VERSION 5.7 ;
NAMESCASESENSITIVE ON ;
BUSBITCHARS "[]" ;
DIVIDERCHAR "|" ;

PROPERTYDEFINITIONS
    LAYER LEF58_TYPE STRING ;
END PROPERTYDEFINITIONS


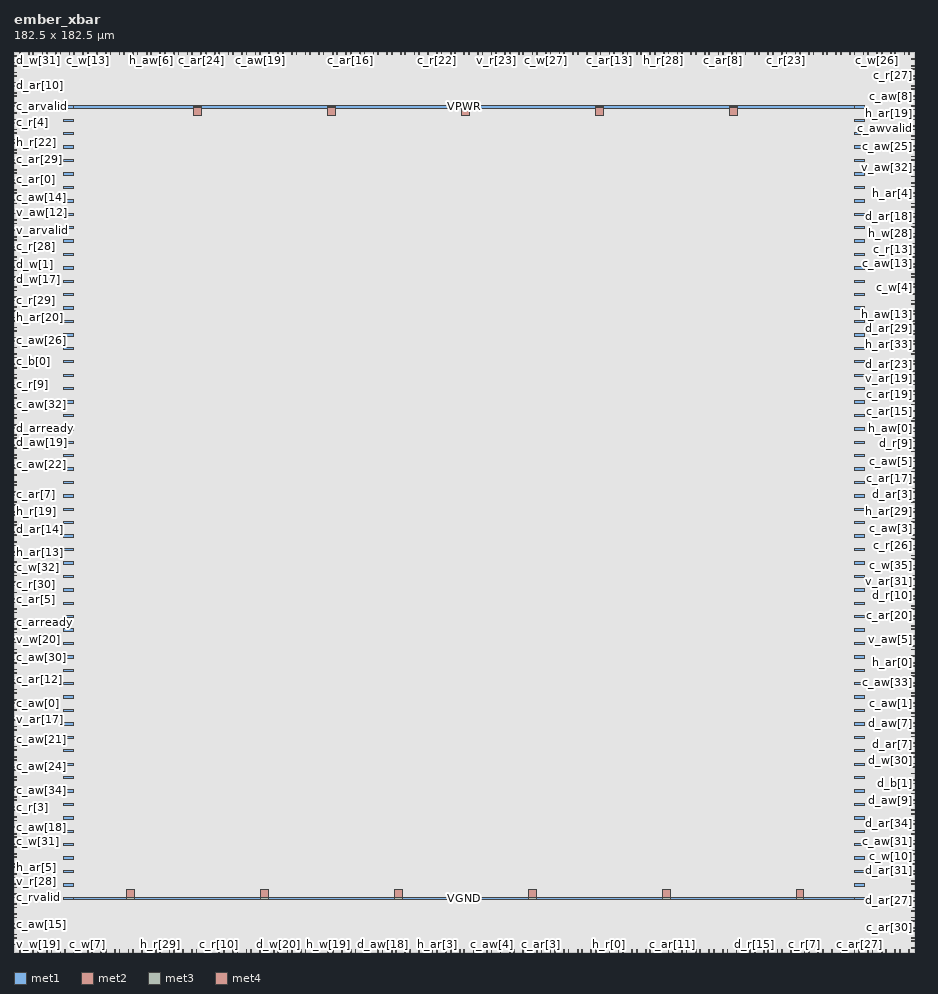
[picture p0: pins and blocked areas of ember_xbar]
MACRO ember_xbar
    CLASS BLOCK ;
    SIZE 182.5 BY 182.5 ;
    SYMMETRY Y ;
    PIN c_ar[0]
        DIRECTION OUTPUT ; 
        USE SIGNAL ; 
        PORT
            LAYER met1 ;
              RECT  0 156.5 0.595 156.64 ;
        END
    END c_ar[0]
    PIN c_ar[10]
        DIRECTION OUTPUT ; 
        USE SIGNAL ; 
        PORT
            LAYER met2 ;
              RECT  21.32 0 21.46 0.485 ;
        END
    END c_ar[10]
    PIN c_ar[11]
        DIRECTION OUTPUT ; 
        USE SIGNAL ; 
        PORT
            LAYER met2 ;
              RECT  133.56 0 133.7 0.485 ;
        END
    END c_ar[11]
    PIN c_ar[12]
        DIRECTION OUTPUT ; 
        USE SIGNAL ; 
        PORT
            LAYER met1 ;
              RECT  0 55.18 0.595 55.32 ;
        END
    END c_ar[12]
    PIN c_ar[13]
        DIRECTION OUTPUT ; 
        USE SIGNAL ; 
        PORT
            LAYER met2 ;
              RECT  120.68 182.015 120.82 182.5 ;
        END
    END c_ar[13]
    PIN c_ar[14]
        DIRECTION OUTPUT ; 
        USE SIGNAL ; 
        PORT
            LAYER met1 ;
              RECT  0 130.66 0.595 130.8 ;
        END
    END c_ar[14]
    PIN c_ar[15]
        DIRECTION OUTPUT ; 
        USE SIGNAL ; 
        PORT
            LAYER met1 ;
              RECT  181.905 109.58 182.5 109.72 ;
        END
    END c_ar[15]
    PIN c_ar[16]
        DIRECTION OUTPUT ; 
        USE SIGNAL ; 
        PORT
            LAYER met2 ;
              RECT  68.24 182.015 68.38 182.5 ;
        END
    END c_ar[16]
    PIN c_ar[17]
        DIRECTION OUTPUT ; 
        USE SIGNAL ; 
        PORT
            LAYER met1 ;
              RECT  181.905 95.98 182.5 96.12 ;
        END
    END c_ar[17]
    PIN c_ar[18]
        DIRECTION OUTPUT ; 
        USE SIGNAL ; 
        PORT
            LAYER met2 ;
              RECT  169.44 182.015 169.58 182.5 ;
        END
    END c_ar[18]
    PIN c_ar[19]
        DIRECTION OUTPUT ; 
        USE SIGNAL ; 
        PORT
            LAYER met1 ;
              RECT  181.905 112.98 182.5 113.12 ;
        END
    END c_ar[19]
    PIN c_ar[1]
        DIRECTION OUTPUT ; 
        USE SIGNAL ; 
        PORT
            LAYER met1 ;
              RECT  181.905 147.66 182.5 147.8 ;
        END
    END c_ar[1]
    PIN c_ar[20]
        DIRECTION OUTPUT ; 
        USE SIGNAL ; 
        PORT
            LAYER met1 ;
              RECT  181.905 68.1 182.5 68.24 ;
        END
    END c_ar[20]
    PIN c_ar[21]
        DIRECTION OUTPUT ; 
        USE SIGNAL ; 
        PORT
            LAYER met2 ;
              RECT  146.44 0 146.58 0.485 ;
        END
    END c_ar[21]
    PIN c_ar[22]
        DIRECTION OUTPUT ; 
        USE SIGNAL ; 
        PORT
            LAYER met2 ;
              RECT  61.8 182.015 61.94 182.5 ;
        END
    END c_ar[22]
    PIN c_ar[23]
        DIRECTION OUTPUT ; 
        USE SIGNAL ; 
        PORT
            LAYER met2 ;
              RECT  2.92 182.015 3.06 182.5 ;
        END
    END c_ar[23]
    PIN c_ar[24]
        DIRECTION OUTPUT ; 
        USE SIGNAL ; 
        PORT
            LAYER met2 ;
              RECT  37.88 182.015 38.02 182.5 ;
        END
    END c_ar[24]
    PIN c_ar[25]
        DIRECTION OUTPUT ; 
        USE SIGNAL ; 
        PORT
            LAYER met2 ;
              RECT  28.68 0 28.82 0.485 ;
        END
    END c_ar[25]
    PIN c_ar[26]
        DIRECTION OUTPUT ; 
        USE SIGNAL ; 
        PORT
            LAYER met2 ;
              RECT  2 0 2.14 0.485 ;
        END
    END c_ar[26]
    PIN c_ar[27]
        DIRECTION OUTPUT ; 
        USE SIGNAL ; 
        PORT
            LAYER met2 ;
              RECT  171.28 0 171.42 0.485 ;
        END
    END c_ar[27]
    PIN c_ar[28]
        DIRECTION OUTPUT ; 
        USE SIGNAL ; 
        PORT
            LAYER met1 ;
              RECT  181.905 89.86 182.5 90 ;
        END
    END c_ar[28]
    PIN c_ar[29]
        DIRECTION OUTPUT ; 
        USE SIGNAL ; 
        PORT
            LAYER met1 ;
              RECT  0 160.58 0.595 160.72 ;
        END
    END c_ar[29]
    PIN c_ar[2]
        DIRECTION OUTPUT ; 
        USE SIGNAL ; 
        PORT
            LAYER met2 ;
              RECT  24.08 0 24.22 0.485 ;
        END
    END c_ar[2]
    PIN c_ar[30]
        DIRECTION OUTPUT ; 
        USE SIGNAL ; 
        PORT
            LAYER met1 ;
              RECT  181.905 4.86 182.5 5 ;
        END
    END c_ar[30]
    PIN c_ar[31]
        DIRECTION OUTPUT ; 
        USE SIGNAL ; 
        PORT
            LAYER met2 ;
              RECT  6.6 182.015 6.74 182.5 ;
        END
    END c_ar[31]
    PIN c_ar[32]
        DIRECTION OUTPUT ; 
        USE SIGNAL ; 
        PORT
            LAYER met1 ;
              RECT  181.905 141.54 182.5 141.68 ;
        END
    END c_ar[32]
    PIN c_ar[33]
        DIRECTION OUTPUT ; 
        USE SIGNAL ; 
        PORT
            LAYER met2 ;
              RECT  94.92 182.015 95.06 182.5 ;
        END
    END c_ar[33]
    PIN c_ar[34]
        DIRECTION OUTPUT ; 
        USE SIGNAL ; 
        PORT
            LAYER met1 ;
              RECT  181.905 113.66 182.5 113.8 ;
        END
    END c_ar[34]
    PIN c_ar[3]
        DIRECTION OUTPUT ; 
        USE SIGNAL ; 
        PORT
            LAYER met2 ;
              RECT  106.88 0 107.02 0.485 ;
        END
    END c_ar[3]
    PIN c_ar[4]
        DIRECTION OUTPUT ; 
        USE SIGNAL ; 
        PORT
            LAYER met2 ;
              RECT  105.96 0 106.1 0.485 ;
        END
    END c_ar[4]
    PIN c_ar[5]
        DIRECTION OUTPUT ; 
        USE SIGNAL ; 
        PORT
            LAYER met1 ;
              RECT  0 71.5 0.595 71.64 ;
        END
    END c_ar[5]
    PIN c_ar[6]
        DIRECTION OUTPUT ; 
        USE SIGNAL ; 
        PORT
            LAYER met2 ;
              RECT  5.68 182.015 5.82 182.5 ;
        END
    END c_ar[6]
    PIN c_ar[7]
        DIRECTION OUTPUT ; 
        USE SIGNAL ; 
        PORT
            LAYER met1 ;
              RECT  0 91.22 0.595 91.36 ;
        END
    END c_ar[7]
    PIN c_ar[8]
        DIRECTION OUTPUT ; 
        USE SIGNAL ; 
        PORT
            LAYER met2 ;
              RECT  143.68 182.015 143.82 182.5 ;
        END
    END c_ar[8]
    PIN c_ar[9]
        DIRECTION OUTPUT ; 
        USE SIGNAL ; 
        PORT
            LAYER met2 ;
              RECT  79.28 0 79.42 0.485 ;
        END
    END c_ar[9]
    PIN c_arready
        DIRECTION INPUT ; 
        USE SIGNAL ; 
        PORT
            LAYER met1 ;
              RECT  0 66.74 0.595 66.88 ;
        END
    END c_arready
    PIN c_arvalid
        DIRECTION OUTPUT ; 
        USE SIGNAL ; 
        PORT
            LAYER met1 ;
              RECT  0 171.46 0.595 171.6 ;
        END
    END c_arvalid
    PIN c_aw[0]
        DIRECTION OUTPUT ; 
        USE SIGNAL ; 
        PORT
            LAYER met1 ;
              RECT  0 50.42 0.595 50.56 ;
        END
    END c_aw[0]
    PIN c_aw[10]
        DIRECTION OUTPUT ; 
        USE SIGNAL ; 
        PORT
            LAYER met1 ;
              RECT  181.905 67.42 182.5 67.56 ;
        END
    END c_aw[10]
    PIN c_aw[11]
        DIRECTION OUTPUT ; 
        USE SIGNAL ; 
        PORT
            LAYER met2 ;
              RECT  167.6 182.015 167.74 182.5 ;
        END
    END c_aw[11]
    PIN c_aw[12]
        DIRECTION OUTPUT ; 
        USE SIGNAL ; 
        PORT
            LAYER met2 ;
              RECT  67.32 182.015 67.46 182.5 ;
        END
    END c_aw[12]
    PIN c_aw[13]
        DIRECTION OUTPUT ; 
        USE SIGNAL ; 
        PORT
            LAYER met1 ;
              RECT  181.905 139.5 182.5 139.64 ;
        END
    END c_aw[13]
    PIN c_aw[14]
        DIRECTION OUTPUT ; 
        USE SIGNAL ; 
        PORT
            LAYER met1 ;
              RECT  0 154.46 0.595 154.6 ;
        END
    END c_aw[14]
    PIN c_aw[15]
        DIRECTION OUTPUT ; 
        USE SIGNAL ; 
        PORT
            LAYER met1 ;
              RECT  0 5.54 0.595 5.68 ;
        END
    END c_aw[15]
    PIN c_aw[16]
        DIRECTION OUTPUT ; 
        USE SIGNAL ; 
        PORT
            LAYER met2 ;
              RECT  163.92 182.015 164.06 182.5 ;
        END
    END c_aw[16]
    PIN c_aw[17]
        DIRECTION OUTPUT ; 
        USE SIGNAL ; 
        PORT
            LAYER met1 ;
              RECT  0 13.7 0.595 13.84 ;
        END
    END c_aw[17]
    PIN c_aw[18]
        DIRECTION OUTPUT ; 
        USE SIGNAL ; 
        PORT
            LAYER met1 ;
              RECT  0 25.26 0.595 25.4 ;
        END
    END c_aw[18]
    PIN c_aw[19]
        DIRECTION OUTPUT ; 
        USE SIGNAL ; 
        PORT
            LAYER met2 ;
              RECT  49.84 182.015 49.98 182.5 ;
        END
    END c_aw[19]
    PIN c_aw[1]
        DIRECTION OUTPUT ; 
        USE SIGNAL ; 
        PORT
            LAYER met1 ;
              RECT  181.905 50.42 182.5 50.56 ;
        END
    END c_aw[1]
    PIN c_aw[20]
        DIRECTION OUTPUT ; 
        USE SIGNAL ; 
        PORT
            LAYER met2 ;
              RECT  94 182.015 94.14 182.5 ;
        END
    END c_aw[20]
    PIN c_aw[21]
        DIRECTION OUTPUT ; 
        USE SIGNAL ; 
        PORT
            LAYER met1 ;
              RECT  0 42.94 0.595 43.08 ;
        END
    END c_aw[21]
    PIN c_aw[22]
        DIRECTION OUTPUT ; 
        USE SIGNAL ; 
        PORT
            LAYER met1 ;
              RECT  0 98.7 0.595 98.84 ;
        END
    END c_aw[22]
    PIN c_aw[23]
        DIRECTION OUTPUT ; 
        USE SIGNAL ; 
        PORT
            LAYER met1 ;
              RECT  181.905 6.9 182.5 7.04 ;
        END
    END c_aw[23]
    PIN c_aw[24]
        DIRECTION OUTPUT ; 
        USE SIGNAL ; 
        PORT
            LAYER met1 ;
              RECT  0 37.5 0.595 37.64 ;
        END
    END c_aw[24]
    PIN c_aw[25]
        DIRECTION OUTPUT ; 
        USE SIGNAL ; 
        PORT
            LAYER met1 ;
              RECT  181.905 163.3 182.5 163.44 ;
        END
    END c_aw[25]
    PIN c_aw[26]
        DIRECTION OUTPUT ; 
        USE SIGNAL ; 
        PORT
            LAYER met1 ;
              RECT  0 123.86 0.595 124 ;
        END
    END c_aw[26]
    PIN c_aw[27]
        DIRECTION OUTPUT ; 
        USE SIGNAL ; 
        PORT
            LAYER met1 ;
              RECT  0 179.62 0.595 179.76 ;
        END
    END c_aw[27]
    PIN c_aw[28]
        DIRECTION OUTPUT ; 
        USE SIGNAL ; 
        PORT
            LAYER met2 ;
              RECT  8.44 182.015 8.58 182.5 ;
        END
    END c_aw[28]
    PIN c_aw[29]
        DIRECTION OUTPUT ; 
        USE SIGNAL ; 
        PORT
            LAYER met2 ;
              RECT  125.28 0 125.42 0.485 ;
        END
    END c_aw[29]
    PIN c_aw[2]
        DIRECTION OUTPUT ; 
        USE SIGNAL ; 
        PORT
            LAYER met1 ;
              RECT  181.905 166.7 182.5 166.84 ;
        END
    END c_aw[2]
    PIN c_aw[30]
        DIRECTION OUTPUT ; 
        USE SIGNAL ; 
        PORT
            LAYER met1 ;
              RECT  0 61.3 0.595 61.44 ;
        END
    END c_aw[30]
    PIN c_aw[31]
        DIRECTION OUTPUT ; 
        USE SIGNAL ; 
        PORT
            LAYER met1 ;
              RECT  181.905 23.9 182.5 24.04 ;
        END
    END c_aw[31]
    PIN c_aw[32]
        DIRECTION OUTPUT ; 
        USE SIGNAL ; 
        PORT
            LAYER met1 ;
              RECT  0 110.94 0.595 111.08 ;
        END
    END c_aw[32]
    PIN c_aw[33]
        DIRECTION OUTPUT ; 
        USE SIGNAL ; 
        PORT
            LAYER met1 ;
              RECT  181.905 54.5 182.5 54.64 ;
        END
    END c_aw[33]
    PIN c_aw[34]
        DIRECTION OUTPUT ; 
        USE SIGNAL ; 
        PORT
            LAYER met1 ;
              RECT  0 32.74 0.595 32.88 ;
        END
    END c_aw[34]
    PIN c_aw[3]
        DIRECTION OUTPUT ; 
        USE SIGNAL ; 
        PORT
            LAYER met1 ;
              RECT  181.905 85.78 182.5 85.92 ;
        END
    END c_aw[3]
    PIN c_aw[4]
        DIRECTION OUTPUT ; 
        USE SIGNAL ; 
        PORT
            LAYER met2 ;
              RECT  96.76 0 96.9 0.485 ;
        END
    END c_aw[4]
    PIN c_aw[5]
        DIRECTION OUTPUT ; 
        USE SIGNAL ; 
        PORT
            LAYER met1 ;
              RECT  181.905 99.38 182.5 99.52 ;
        END
    END c_aw[5]
    PIN c_aw[6]
        DIRECTION OUTPUT ; 
        USE SIGNAL ; 
        PORT
            LAYER met2 ;
              RECT  89.4 182.015 89.54 182.5 ;
        END
    END c_aw[6]
    PIN c_aw[7]
        DIRECTION OUTPUT ; 
        USE SIGNAL ; 
        PORT
            LAYER met2 ;
              RECT  101.36 0 101.5 0.485 ;
        END
    END c_aw[7]
    PIN c_aw[8]
        DIRECTION OUTPUT ; 
        USE SIGNAL ; 
        PORT
            LAYER met1 ;
              RECT  181.905 173.5 182.5 173.64 ;
        END
    END c_aw[8]
    PIN c_aw[9]
        DIRECTION OUTPUT ; 
        USE SIGNAL ; 
        PORT
            LAYER met1 ;
              RECT  181.905 19.82 182.5 19.96 ;
        END
    END c_aw[9]
    PIN c_awready
        DIRECTION INPUT ; 
        USE SIGNAL ; 
        PORT
            LAYER met1 ;
              RECT  181.905 100.06 182.5 100.2 ;
        END
    END c_awready
    PIN c_awvalid
        DIRECTION OUTPUT ; 
        USE SIGNAL ; 
        PORT
            LAYER met1 ;
              RECT  181.905 165.34 182.5 165.48 ;
        END
    END c_awvalid
    PIN c_b[0]
        DIRECTION INPUT ; 
        USE SIGNAL ; 
        PORT
            LAYER met1 ;
              RECT  0 121.14 0.595 121.28 ;
        END
    END c_b[0]
    PIN c_b[1]
        DIRECTION INPUT ; 
        USE SIGNAL ; 
        PORT
            LAYER met1 ;
              RECT  181.905 26.62 182.5 26.76 ;
        END
    END c_b[1]
    PIN c_bready
        DIRECTION OUTPUT ; 
        USE SIGNAL ; 
        PORT
            LAYER met1 ;
              RECT  0 136.1 0.595 136.24 ;
        END
    END c_bready
    PIN c_bvalid
        DIRECTION INPUT ; 
        USE SIGNAL ; 
        PORT
            LAYER met2 ;
              RECT  78.36 182.015 78.5 182.5 ;
        END
    END c_bvalid
    PIN c_r[0]
        DIRECTION INPUT ; 
        USE SIGNAL ; 
        PORT
            LAYER met1 ;
              RECT  0 118.42 0.595 118.56 ;
        END
    END c_r[0]
    PIN c_r[10]
        DIRECTION INPUT ; 
        USE SIGNAL ; 
        PORT
            LAYER met2 ;
              RECT  41.56 0 41.7 0.485 ;
        END
    END c_r[10]
    PIN c_r[11]
        DIRECTION INPUT ; 
        USE SIGNAL ; 
        PORT
            LAYER met2 ;
              RECT  113.32 182.015 113.46 182.5 ;
        END
    END c_r[11]
    PIN c_r[12]
        DIRECTION INPUT ; 
        USE SIGNAL ; 
        PORT
            LAYER met1 ;
              RECT  0 44.98 0.595 45.12 ;
        END
    END c_r[12]
    PIN c_r[13]
        DIRECTION INPUT ; 
        USE SIGNAL ; 
        PORT
            LAYER met1 ;
              RECT  181.905 140.86 182.5 141 ;
        END
    END c_r[13]
    PIN c_r[14]
        DIRECTION INPUT ; 
        USE SIGNAL ; 
        PORT
            LAYER met2 ;
              RECT  137.24 182.015 137.38 182.5 ;
        END
    END c_r[14]
    PIN c_r[15]
        DIRECTION INPUT ; 
        USE SIGNAL ; 
        PORT
            LAYER met2 ;
              RECT  20.4 0 20.54 0.485 ;
        END
    END c_r[15]
    PIN c_r[16]
        DIRECTION INPUT ; 
        USE SIGNAL ; 
        PORT
            LAYER met2 ;
              RECT  123.44 182.015 123.58 182.5 ;
        END
    END c_r[16]
    PIN c_r[17]
        DIRECTION INPUT ; 
        USE SIGNAL ; 
        PORT
            LAYER met2 ;
              RECT  68.24 0 68.38 0.485 ;
        END
    END c_r[17]
    PIN c_r[18]
        DIRECTION INPUT ; 
        USE SIGNAL ; 
        PORT
            LAYER met1 ;
              RECT  0 39.54 0.595 39.68 ;
        END
    END c_r[18]
    PIN c_r[19]
        DIRECTION INPUT ; 
        USE SIGNAL ; 
        PORT
            LAYER met1 ;
              RECT  181.905 127.26 182.5 127.4 ;
        END
    END c_r[19]
    PIN c_r[1]
        DIRECTION INPUT ; 
        USE SIGNAL ; 
        PORT
            LAYER met1 ;
              RECT  0 69.46 0.595 69.6 ;
        END
    END c_r[1]
    PIN c_r[20]
        DIRECTION INPUT ; 
        USE SIGNAL ; 
        PORT
            LAYER met1 ;
              RECT  0 94.62 0.595 94.76 ;
        END
    END c_r[20]
    PIN c_r[21]
        DIRECTION INPUT ; 
        USE SIGNAL ; 
        PORT
            LAYER met2 ;
              RECT  163.92 0 164.06 0.485 ;
        END
    END c_r[21]
    PIN c_r[22]
        DIRECTION INPUT ; 
        USE SIGNAL ; 
        PORT
            LAYER met2 ;
              RECT  85.72 182.015 85.86 182.5 ;
        END
    END c_r[22]
    PIN c_r[23]
        DIRECTION INPUT ; 
        USE SIGNAL ; 
        PORT
            LAYER met2 ;
              RECT  156.56 182.015 156.7 182.5 ;
        END
    END c_r[23]
    PIN c_r[24]
        DIRECTION INPUT ; 
        USE SIGNAL ; 
        PORT
            LAYER met2 ;
              RECT  95.84 0 95.98 0.485 ;
        END
    END c_r[24]
    PIN c_r[25]
        DIRECTION INPUT ; 
        USE SIGNAL ; 
        PORT
            LAYER met2 ;
              RECT  81.12 182.015 81.26 182.5 ;
        END
    END c_r[25]
    PIN c_r[26]
        DIRECTION INPUT ; 
        USE SIGNAL ; 
        PORT
            LAYER met1 ;
              RECT  181.905 82.38 182.5 82.52 ;
        END
    END c_r[26]
    PIN c_r[27]
        DIRECTION INPUT ; 
        USE SIGNAL ; 
        PORT
            LAYER met1 ;
              RECT  181.905 177.58 182.5 177.72 ;
        END
    END c_r[27]
    PIN c_r[28]
        DIRECTION INPUT ; 
        USE SIGNAL ; 
        PORT
            LAYER met1 ;
              RECT  0 142.9 0.595 143.04 ;
        END
    END c_r[28]
    PIN c_r[29]
        DIRECTION INPUT ; 
        USE SIGNAL ; 
        PORT
            LAYER met1 ;
              RECT  0 132.02 0.595 132.16 ;
        END
    END c_r[29]
    PIN c_r[2]
        DIRECTION INPUT ; 
        USE SIGNAL ; 
        PORT
            LAYER met1 ;
              RECT  0 51.1 0.595 51.24 ;
        END
    END c_r[2]
    PIN c_r[30]
        DIRECTION INPUT ; 
        USE SIGNAL ; 
        PORT
            LAYER met1 ;
              RECT  0 72.86 0.595 73 ;
        END
    END c_r[30]
    PIN c_r[31]
        DIRECTION INPUT ; 
        USE SIGNAL ; 
        PORT
            LAYER met2 ;
              RECT  56.28 182.015 56.42 182.5 ;
        END
    END c_r[31]
    PIN c_r[32]
        DIRECTION INPUT ; 
        USE SIGNAL ; 
        PORT
            LAYER met2 ;
              RECT  13.04 0 13.18 0.485 ;
        END
    END c_r[32]
    PIN c_r[33]
        DIRECTION INPUT ; 
        USE SIGNAL ; 
        PORT
            LAYER met1 ;
              RECT  181.905 125.9 182.5 126.04 ;
        END
    END c_r[33]
    PIN c_r[3]
        DIRECTION INPUT ; 
        USE SIGNAL ; 
        PORT
            LAYER met1 ;
              RECT  0 30.7 0.595 30.84 ;
        END
    END c_r[3]
    PIN c_r[4]
        DIRECTION INPUT ; 
        USE SIGNAL ; 
        PORT
            LAYER met1 ;
              RECT  0 168.06 0.595 168.2 ;
        END
    END c_r[4]
    PIN c_r[5]
        DIRECTION INPUT ; 
        USE SIGNAL ; 
        PORT
            LAYER met1 ;
              RECT  181.905 13.7 182.5 13.84 ;
        END
    END c_r[5]
    PIN c_r[6]
        DIRECTION INPUT ; 
        USE SIGNAL ; 
        PORT
            LAYER met1 ;
              RECT  181.905 123.86 182.5 124 ;
        END
    END c_r[6]
    PIN c_r[7]
        DIRECTION INPUT ; 
        USE SIGNAL ; 
        PORT
            LAYER met2 ;
              RECT  160.24 0 160.38 0.485 ;
        END
    END c_r[7]
    PIN c_r[8]
        DIRECTION INPUT ; 
        USE SIGNAL ; 
        PORT
            LAYER met1 ;
              RECT  181.905 97.34 182.5 97.48 ;
        END
    END c_r[8]
    PIN c_r[9]
        DIRECTION INPUT ; 
        USE SIGNAL ; 
        PORT
            LAYER met1 ;
              RECT  0 115.02 0.595 115.16 ;
        END
    END c_r[9]
    PIN c_rready
        DIRECTION OUTPUT ; 
        USE SIGNAL ; 
        PORT
            LAYER met1 ;
              RECT  0 88.5 0.595 88.64 ;
        END
    END c_rready
    PIN c_rvalid
        DIRECTION INPUT ; 
        USE SIGNAL ; 
        PORT
            LAYER met1 ;
              RECT  0 10.98 0.595 11.12 ;
        END
    END c_rvalid
    PIN c_w[0]
        DIRECTION OUTPUT ; 
        USE SIGNAL ; 
        PORT
            LAYER met2 ;
              RECT  108.72 0 108.86 0.485 ;
        END
    END c_w[0]
    PIN c_w[10]
        DIRECTION OUTPUT ; 
        USE SIGNAL ; 
        PORT
            LAYER met1 ;
              RECT  181.905 17.78 182.5 17.92 ;
        END
    END c_w[10]
    PIN c_w[11]
        DIRECTION OUTPUT ; 
        USE SIGNAL ; 
        PORT
            LAYER met1 ;
              RECT  181.905 51.78 182.5 51.92 ;
        END
    END c_w[11]
    PIN c_w[12]
        DIRECTION OUTPUT ; 
        USE SIGNAL ; 
        PORT
            LAYER met1 ;
              RECT  0 6.9 0.595 7.04 ;
        END
    END c_w[12]
    PIN c_w[13]
        DIRECTION OUTPUT ; 
        USE SIGNAL ; 
        PORT
            LAYER met2 ;
              RECT  14.88 182.015 15.02 182.5 ;
        END
    END c_w[13]
    PIN c_w[14]
        DIRECTION OUTPUT ; 
        USE SIGNAL ; 
        PORT
            LAYER met1 ;
              RECT  0 178.26 0.595 178.4 ;
        END
    END c_w[14]
    PIN c_w[15]
        DIRECTION OUTPUT ; 
        USE SIGNAL ; 
        PORT
            LAYER met1 ;
              RECT  181.905 24.58 182.5 24.72 ;
        END
    END c_w[15]
    PIN c_w[16]
        DIRECTION OUTPUT ; 
        USE SIGNAL ; 
        PORT
            LAYER met2 ;
              RECT  82.04 182.015 82.18 182.5 ;
        END
    END c_w[16]
    PIN c_w[17]
        DIRECTION OUTPUT ; 
        USE SIGNAL ; 
        PORT
            LAYER met2 ;
              RECT  76.52 182.015 76.66 182.5 ;
        END
    END c_w[17]
    PIN c_w[18]
        DIRECTION OUTPUT ; 
        USE SIGNAL ; 
        PORT
            LAYER met2 ;
              RECT  163 0 163.14 0.485 ;
        END
    END c_w[18]
    PIN c_w[19]
        DIRECTION OUTPUT ; 
        USE SIGNAL ; 
        PORT
            LAYER met2 ;
              RECT  88.48 182.015 88.62 182.5 ;
        END
    END c_w[19]
    PIN c_w[1]
        DIRECTION OUTPUT ; 
        USE SIGNAL ; 
        PORT
            LAYER met1 ;
              RECT  181.905 174.86 182.5 175 ;
        END
    END c_w[1]
    PIN c_w[20]
        DIRECTION OUTPUT ; 
        USE SIGNAL ; 
        PORT
            LAYER met1 ;
              RECT  0 170.1 0.595 170.24 ;
        END
    END c_w[20]
    PIN c_w[21]
        DIRECTION OUTPUT ; 
        USE SIGNAL ; 
        PORT
            LAYER met2 ;
              RECT  142.76 182.015 142.9 182.5 ;
        END
    END c_w[21]
    PIN c_w[22]
        DIRECTION OUTPUT ; 
        USE SIGNAL ; 
        PORT
            LAYER met2 ;
              RECT  98.6 0 98.74 0.485 ;
        END
    END c_w[22]
    PIN c_w[23]
        DIRECTION OUTPUT ; 
        USE SIGNAL ; 
        PORT
            LAYER met1 ;
              RECT  181.905 179.62 182.5 179.76 ;
        END
    END c_w[23]
    PIN c_w[24]
        DIRECTION OUTPUT ; 
        USE SIGNAL ; 
        PORT
            LAYER met2 ;
              RECT  145.52 182.015 145.66 182.5 ;
        END
    END c_w[24]
    PIN c_w[25]
        DIRECTION OUTPUT ; 
        USE SIGNAL ; 
        PORT
            LAYER met2 ;
              RECT  51.68 182.015 51.82 182.5 ;
        END
    END c_w[25]
    PIN c_w[26]
        DIRECTION OUTPUT ; 
        USE SIGNAL ; 
        PORT
            LAYER met2 ;
              RECT  174.96 182.015 175.1 182.5 ;
        END
    END c_w[26]
    PIN c_w[27]
        DIRECTION OUTPUT ; 
        USE SIGNAL ; 
        PORT
            LAYER met2 ;
              RECT  107.8 182.015 107.94 182.5 ;
        END
    END c_w[27]
    PIN c_w[28]
        DIRECTION OUTPUT ; 
        USE SIGNAL ; 
        PORT
            LAYER met2 ;
              RECT  87.56 0 87.7 0.485 ;
        END
    END c_w[28]
    PIN c_w[29]
        DIRECTION OUTPUT ; 
        USE SIGNAL ; 
        PORT
            LAYER met2 ;
              RECT  158.4 0 158.54 0.485 ;
        END
    END c_w[29]
    PIN c_w[2]
        DIRECTION OUTPUT ; 
        USE SIGNAL ; 
        PORT
            LAYER met2 ;
              RECT  42.48 0 42.62 0.485 ;
        END
    END c_w[2]
    PIN c_w[30]
        DIRECTION OUTPUT ; 
        USE SIGNAL ; 
        PORT
            LAYER met2 ;
              RECT  126.2 0 126.34 0.485 ;
        END
    END c_w[30]
    PIN c_w[31]
        DIRECTION OUTPUT ; 
        USE SIGNAL ; 
        PORT
            LAYER met1 ;
              RECT  0 23.9 0.595 24.04 ;
        END
    END c_w[31]
    PIN c_w[32]
        DIRECTION OUTPUT ; 
        USE SIGNAL ; 
        PORT
            LAYER met1 ;
              RECT  0 76.26 0.595 76.4 ;
        END
    END c_w[32]
    PIN c_w[33]
        DIRECTION OUTPUT ; 
        USE SIGNAL ; 
        PORT
            LAYER met2 ;
              RECT  18.56 182.015 18.7 182.5 ;
        END
    END c_w[33]
    PIN c_w[34]
        DIRECTION OUTPUT ; 
        USE SIGNAL ; 
        PORT
            LAYER met1 ;
              RECT  0 114.34 0.595 114.48 ;
        END
    END c_w[34]
    PIN c_w[35]
        DIRECTION OUTPUT ; 
        USE SIGNAL ; 
        PORT
            LAYER met1 ;
              RECT  181.905 78.3 182.5 78.44 ;
        END
    END c_w[35]
    PIN c_w[3]
        DIRECTION OUTPUT ; 
        USE SIGNAL ; 
        PORT
            LAYER met2 ;
              RECT  178.64 0 178.78 0.485 ;
        END
    END c_w[3]
    PIN c_w[4]
        DIRECTION OUTPUT ; 
        USE SIGNAL ; 
        PORT
            LAYER met1 ;
              RECT  181.905 134.74 182.5 134.88 ;
        END
    END c_w[4]
    PIN c_w[5]
        DIRECTION OUTPUT ; 
        USE SIGNAL ; 
        PORT
            LAYER met1 ;
              RECT  0 21.86 0.595 22 ;
        END
    END c_w[5]
    PIN c_w[6]
        DIRECTION OUTPUT ; 
        USE SIGNAL ; 
        PORT
            LAYER met1 ;
              RECT  0 117.06 0.595 117.2 ;
        END
    END c_w[6]
    PIN c_w[7]
        DIRECTION OUTPUT ; 
        USE SIGNAL ; 
        PORT
            LAYER met2 ;
              RECT  14.88 0 15.02 0.485 ;
        END
    END c_w[7]
    PIN c_w[8]
        DIRECTION OUTPUT ; 
        USE SIGNAL ; 
        PORT
            LAYER met1 ;
              RECT  181.905 49.74 182.5 49.88 ;
        END
    END c_w[8]
    PIN c_w[9]
        DIRECTION OUTPUT ; 
        USE SIGNAL ; 
        PORT
            LAYER met1 ;
              RECT  181.905 91.9 182.5 92.04 ;
        END
    END c_w[9]
    PIN c_wready
        DIRECTION INPUT ; 
        USE SIGNAL ; 
        PORT
            LAYER met2 ;
              RECT  178.64 182.015 178.78 182.5 ;
        END
    END c_wready
    PIN c_wvalid
        DIRECTION OUTPUT ; 
        USE SIGNAL ; 
        PORT
            LAYER met1 ;
              RECT  181.905 20.5 182.5 20.64 ;
        END
    END c_wvalid
    PIN clk
        DIRECTION INPUT ; 
        USE SIGNAL ; 
        PORT
            LAYER met2 ;
              RECT  177.72 182.015 177.86 182.5 ;
        END
    END clk
    PIN d_ar[0]
        DIRECTION INPUT ; 
        USE SIGNAL ; 
        PORT
            LAYER met2 ;
              RECT  170.36 182.015 170.5 182.5 ;
        END
    END d_ar[0]
    PIN d_ar[10]
        DIRECTION INPUT ; 
        USE SIGNAL ; 
        PORT
            LAYER met1 ;
              RECT  0 174.18 0.595 174.32 ;
        END
    END d_ar[10]
    PIN d_ar[11]
        DIRECTION INPUT ; 
        USE SIGNAL ; 
        PORT
            LAYER met2 ;
              RECT  11.2 182.015 11.34 182.5 ;
        END
    END d_ar[11]
    PIN d_ar[12]
        DIRECTION INPUT ; 
        USE SIGNAL ; 
        PORT
            LAYER met1 ;
              RECT  0 158.54 0.595 158.68 ;
        END
    END d_ar[12]
    PIN d_ar[13]
        DIRECTION INPUT ; 
        USE SIGNAL ; 
        PORT
            LAYER met2 ;
              RECT  72.84 182.015 72.98 182.5 ;
        END
    END d_ar[13]
    PIN d_ar[14]
        DIRECTION INPUT ; 
        USE SIGNAL ; 
        PORT
            LAYER met1 ;
              RECT  0 87.14 0.595 87.28 ;
        END
    END d_ar[14]
    PIN d_ar[15]
        DIRECTION INPUT ; 
        USE SIGNAL ; 
        PORT
            LAYER met2 ;
              RECT  88.48 0 88.62 0.485 ;
        END
    END d_ar[15]
    PIN d_ar[16]
        DIRECTION INPUT ; 
        USE SIGNAL ; 
        PORT
            LAYER met1 ;
              RECT  181.905 75.58 182.5 75.72 ;
        END
    END d_ar[16]
    PIN d_ar[17]
        DIRECTION INPUT ; 
        USE SIGNAL ; 
        PORT
            LAYER met2 ;
              RECT  50.76 0 50.9 0.485 ;
        END
    END d_ar[17]
    PIN d_ar[18]
        DIRECTION INPUT ; 
        USE SIGNAL ; 
        PORT
            LAYER met1 ;
              RECT  181.905 149.02 182.5 149.16 ;
        END
    END d_ar[18]
    PIN d_ar[19]
        DIRECTION INPUT ; 
        USE SIGNAL ; 
        PORT
            LAYER met1 ;
              RECT  0 124.54 0.595 124.68 ;
        END
    END d_ar[19]
    PIN d_ar[1]
        DIRECTION INPUT ; 
        USE SIGNAL ; 
        PORT
            LAYER met2 ;
              RECT  140.92 0 141.06 0.485 ;
        END
    END d_ar[1]
    PIN d_ar[20]
        DIRECTION INPUT ; 
        USE SIGNAL ; 
        PORT
            LAYER met1 ;
              RECT  0 15.06 0.595 15.2 ;
        END
    END d_ar[20]
    PIN d_ar[21]
        DIRECTION INPUT ; 
        USE SIGNAL ; 
        PORT
            LAYER met1 ;
              RECT  0 49.06 0.595 49.2 ;
        END
    END d_ar[21]
    PIN d_ar[22]
        DIRECTION INPUT ; 
        USE SIGNAL ; 
        PORT
            LAYER met1 ;
              RECT  181.905 4.18 182.5 4.32 ;
        END
    END d_ar[22]
    PIN d_ar[23]
        DIRECTION INPUT ; 
        USE SIGNAL ; 
        PORT
            LAYER met1 ;
              RECT  181.905 119.1 182.5 119.24 ;
        END
    END d_ar[23]
    PIN d_ar[24]
        DIRECTION INPUT ; 
        USE SIGNAL ; 
        PORT
            LAYER met1 ;
              RECT  0 125.9 0.595 126.04 ;
        END
    END d_ar[24]
    PIN d_ar[25]
        DIRECTION INPUT ; 
        USE SIGNAL ; 
        PORT
            LAYER met2 ;
              RECT  12.12 182.015 12.26 182.5 ;
        END
    END d_ar[25]
    PIN d_ar[26]
        DIRECTION INPUT ; 
        USE SIGNAL ; 
        PORT
            LAYER met2 ;
              RECT  111.48 182.015 111.62 182.5 ;
        END
    END d_ar[26]
    PIN d_ar[27]
        DIRECTION INPUT ; 
        USE SIGNAL ; 
        PORT
            LAYER met1 ;
              RECT  181.905 10.3 182.5 10.44 ;
        END
    END d_ar[27]
    PIN d_ar[28]
        DIRECTION INPUT ; 
        USE SIGNAL ; 
        PORT
            LAYER met1 ;
              RECT  0 181.66 0.595 181.8 ;
        END
    END d_ar[28]
    PIN d_ar[29]
        DIRECTION INPUT ; 
        USE SIGNAL ; 
        PORT
            LAYER met1 ;
              RECT  181.905 127.94 182.5 128.08 ;
        END
    END d_ar[29]
    PIN d_ar[2]
        DIRECTION INPUT ; 
        USE SIGNAL ; 
        PORT
            LAYER met1 ;
              RECT  181.905 162.62 182.5 162.76 ;
        END
    END d_ar[2]
    PIN d_ar[30]
        DIRECTION INPUT ; 
        USE SIGNAL ; 
        PORT
            LAYER met1 ;
              RECT  181.905 15.74 182.5 15.88 ;
        END
    END d_ar[30]
    PIN d_ar[31]
        DIRECTION INPUT ; 
        USE SIGNAL ; 
        PORT
            LAYER met1 ;
              RECT  181.905 16.42 182.5 16.56 ;
        END
    END d_ar[31]
    PIN d_ar[32]
        DIRECTION INPUT ; 
        USE SIGNAL ; 
        PORT
            LAYER met1 ;
              RECT  181.905 119.78 182.5 119.92 ;
        END
    END d_ar[32]
    PIN d_ar[33]
        DIRECTION INPUT ; 
        USE SIGNAL ; 
        PORT
            LAYER met2 ;
              RECT  57.2 182.015 57.34 182.5 ;
        END
    END d_ar[33]
    PIN d_ar[34]
        DIRECTION INPUT ; 
        USE SIGNAL ; 
        PORT
            LAYER met1 ;
              RECT  181.905 25.94 182.5 26.08 ;
        END
    END d_ar[34]
    PIN d_ar[3]
        DIRECTION INPUT ; 
        USE SIGNAL ; 
        PORT
            LAYER met1 ;
              RECT  181.905 91.22 182.5 91.36 ;
        END
    END d_ar[3]
    PIN d_ar[4]
        DIRECTION INPUT ; 
        USE SIGNAL ; 
        PORT
            LAYER met2 ;
              RECT  172.2 182.015 172.34 182.5 ;
        END
    END d_ar[4]
    PIN d_ar[5]
        DIRECTION INPUT ; 
        USE SIGNAL ; 
        PORT
            LAYER met1 ;
              RECT  181.905 65.38 182.5 65.52 ;
        END
    END d_ar[5]
    PIN d_ar[6]
        DIRECTION INPUT ; 
        USE SIGNAL ; 
        PORT
            LAYER met1 ;
              RECT  0 138.14 0.595 138.28 ;
        END
    END d_ar[6]
    PIN d_ar[7]
        DIRECTION INPUT ; 
        USE SIGNAL ; 
        PORT
            LAYER met1 ;
              RECT  181.905 43.62 182.5 43.76 ;
        END
    END d_ar[7]
    PIN d_ar[8]
        DIRECTION INPUT ; 
        USE SIGNAL ; 
        PORT
            LAYER met1 ;
              RECT  0 45.66 0.595 45.8 ;
        END
    END d_ar[8]
    PIN d_ar[9]
        DIRECTION INPUT ; 
        USE SIGNAL ; 
        PORT
            LAYER met2 ;
              RECT  100.44 0 100.58 0.485 ;
        END
    END d_ar[9]
    PIN d_arready
        DIRECTION OUTPUT ; 
        USE SIGNAL ; 
        PORT
            LAYER met1 ;
              RECT  0 106.18 0.595 106.32 ;
        END
    END d_arready
    PIN d_arvalid
        DIRECTION INPUT ; 
        USE SIGNAL ; 
        PORT
            LAYER met2 ;
              RECT  60.88 0 61.02 0.485 ;
        END
    END d_arvalid
    PIN d_aw[0]
        DIRECTION INPUT ; 
        USE SIGNAL ; 
        PORT
            LAYER met1 ;
              RECT  181.905 103.46 182.5 103.6 ;
        END
    END d_aw[0]
    PIN d_aw[10]
        DIRECTION INPUT ; 
        USE SIGNAL ; 
        PORT
            LAYER met2 ;
              RECT  36.04 182.015 36.18 182.5 ;
        END
    END d_aw[10]
    PIN d_aw[11]
        DIRECTION INPUT ; 
        USE SIGNAL ; 
        PORT
            LAYER met1 ;
              RECT  181.905 48.38 182.5 48.52 ;
        END
    END d_aw[11]
    PIN d_aw[12]
        DIRECTION INPUT ; 
        USE SIGNAL ; 
        PORT
            LAYER met2 ;
              RECT  122.52 0 122.66 0.485 ;
        END
    END d_aw[12]
    PIN d_aw[13]
        DIRECTION INPUT ; 
        USE SIGNAL ; 
        PORT
            LAYER met1 ;
              RECT  181.905 138.82 182.5 138.96 ;
        END
    END d_aw[13]
    PIN d_aw[14]
        DIRECTION INPUT ; 
        USE SIGNAL ; 
        PORT
            LAYER met1 ;
              RECT  181.905 129.98 182.5 130.12 ;
        END
    END d_aw[14]
    PIN d_aw[15]
        DIRECTION INPUT ; 
        USE SIGNAL ; 
        PORT
            LAYER met2 ;
              RECT  26.84 0 26.98 0.485 ;
        END
    END d_aw[15]
    PIN d_aw[16]
        DIRECTION INPUT ; 
        USE SIGNAL ; 
        PORT
            LAYER met1 ;
              RECT  0 95.3 0.595 95.44 ;
        END
    END d_aw[16]
    PIN d_aw[17]
        DIRECTION INPUT ; 
        USE SIGNAL ; 
        PORT
            LAYER met1 ;
              RECT  0 151.74 0.595 151.88 ;
        END
    END d_aw[17]
    PIN d_aw[18]
        DIRECTION INPUT ; 
        USE SIGNAL ; 
        PORT
            LAYER met2 ;
              RECT  74.68 0 74.82 0.485 ;
        END
    END d_aw[18]
    PIN d_aw[19]
        DIRECTION INPUT ; 
        USE SIGNAL ; 
        PORT
            LAYER met1 ;
              RECT  0 104.82 0.595 104.96 ;
        END
    END d_aw[19]
    PIN d_aw[1]
        DIRECTION INPUT ; 
        USE SIGNAL ; 
        PORT
            LAYER met2 ;
              RECT  93.08 0 93.22 0.485 ;
        END
    END d_aw[1]
    PIN d_aw[20]
        DIRECTION INPUT ; 
        USE SIGNAL ; 
        PORT
            LAYER met1 ;
              RECT  0 59.26 0.595 59.4 ;
        END
    END d_aw[20]
    PIN d_aw[21]
        DIRECTION INPUT ; 
        USE SIGNAL ; 
        PORT
            LAYER met2 ;
              RECT  41.56 182.015 41.7 182.5 ;
        END
    END d_aw[21]
    PIN d_aw[22]
        DIRECTION INPUT ; 
        USE SIGNAL ; 
        PORT
            LAYER met2 ;
              RECT  165.76 0 165.9 0.485 ;
        END
    END d_aw[22]
    PIN d_aw[23]
        DIRECTION INPUT ; 
        USE SIGNAL ; 
        PORT
            LAYER met2 ;
              RECT  124.36 182.015 124.5 182.5 ;
        END
    END d_aw[23]
    PIN d_aw[24]
        DIRECTION INPUT ; 
        USE SIGNAL ; 
        PORT
            LAYER met2 ;
              RECT  52.6 0 52.74 0.485 ;
        END
    END d_aw[24]
    PIN d_aw[25]
        DIRECTION INPUT ; 
        USE SIGNAL ; 
        PORT
            LAYER met1 ;
              RECT  0 19.82 0.595 19.96 ;
        END
    END d_aw[25]
    PIN d_aw[26]
        DIRECTION INPUT ; 
        USE SIGNAL ; 
        PORT
            LAYER met2 ;
              RECT  69.16 0 69.3 0.485 ;
        END
    END d_aw[26]
    PIN d_aw[27]
        DIRECTION INPUT ; 
        USE SIGNAL ; 
        PORT
            LAYER met1 ;
              RECT  0 152.42 0.595 152.56 ;
        END
    END d_aw[27]
    PIN d_aw[28]
        DIRECTION INPUT ; 
        USE SIGNAL ; 
        PORT
            LAYER met1 ;
              RECT  0 38.86 0.595 39 ;
        END
    END d_aw[28]
    PIN d_aw[29]
        DIRECTION INPUT ; 
        USE SIGNAL ; 
        PORT
            LAYER met1 ;
              RECT  0 112.98 0.595 113.12 ;
        END
    END d_aw[29]
    PIN d_aw[2]
        DIRECTION INPUT ; 
        USE SIGNAL ; 
        PORT
            LAYER met1 ;
              RECT  181.905 70.14 182.5 70.28 ;
        END
    END d_aw[2]
    PIN d_aw[30]
        DIRECTION INPUT ; 
        USE SIGNAL ; 
        PORT
            LAYER met1 ;
              RECT  0 74.22 0.595 74.36 ;
        END
    END d_aw[30]
    PIN d_aw[31]
        DIRECTION INPUT ; 
        USE SIGNAL ; 
        PORT
            LAYER met2 ;
              RECT  44.32 182.015 44.46 182.5 ;
        END
    END d_aw[31]
    PIN d_aw[32]
        DIRECTION INPUT ; 
        USE SIGNAL ; 
        PORT
            LAYER met1 ;
              RECT  0 159.9 0.595 160.04 ;
        END
    END d_aw[32]
    PIN d_aw[33]
        DIRECTION INPUT ; 
        USE SIGNAL ; 
        PORT
            LAYER met1 ;
              RECT  0 76.94 0.595 77.08 ;
        END
    END d_aw[33]
    PIN d_aw[34]
        DIRECTION INPUT ; 
        USE SIGNAL ; 
        PORT
            LAYER met1 ;
              RECT  181.905 22.54 182.5 22.68 ;
        END
    END d_aw[34]
    PIN d_aw[3]
        DIRECTION INPUT ; 
        USE SIGNAL ; 
        PORT
            LAYER met1 ;
              RECT  0 28.66 0.595 28.8 ;
        END
    END d_aw[3]
    PIN d_aw[4]
        DIRECTION INPUT ; 
        USE SIGNAL ; 
        PORT
            LAYER met1 ;
              RECT  0 176.22 0.595 176.36 ;
        END
    END d_aw[4]
    PIN d_aw[5]
        DIRECTION INPUT ; 
        USE SIGNAL ; 
        PORT
            LAYER met1 ;
              RECT  181.905 21.86 182.5 22 ;
        END
    END d_aw[5]
    PIN d_aw[6]
        DIRECTION INPUT ; 
        USE SIGNAL ; 
        PORT
            LAYER met2 ;
              RECT  157.48 0 157.62 0.485 ;
        END
    END d_aw[6]
    PIN d_aw[7]
        DIRECTION INPUT ; 
        USE SIGNAL ; 
        PORT
            LAYER met1 ;
              RECT  181.905 46.34 182.5 46.48 ;
        END
    END d_aw[7]
    PIN d_aw[8]
        DIRECTION INPUT ; 
        USE SIGNAL ; 
        PORT
            LAYER met1 ;
              RECT  0 52.46 0.595 52.6 ;
        END
    END d_aw[8]
    PIN d_aw[9]
        DIRECTION INPUT ; 
        USE SIGNAL ; 
        PORT
            LAYER met1 ;
              RECT  181.905 30.7 182.5 30.84 ;
        END
    END d_aw[9]
    PIN d_awready
        DIRECTION OUTPUT ; 
        USE SIGNAL ; 
        PORT
            LAYER met1 ;
              RECT  181.905 117.06 182.5 117.2 ;
        END
    END d_awready
    PIN d_awvalid
        DIRECTION INPUT ; 
        USE SIGNAL ; 
        PORT
            LAYER met2 ;
              RECT  110.56 182.015 110.7 182.5 ;
        END
    END d_awvalid
    PIN d_b[0]
        DIRECTION OUTPUT ; 
        USE SIGNAL ; 
        PORT
            LAYER met1 ;
              RECT  181.905 159.22 182.5 159.36 ;
        END
    END d_b[0]
    PIN d_b[1]
        DIRECTION OUTPUT ; 
        USE SIGNAL ; 
        PORT
            LAYER met1 ;
              RECT  181.905 34.1 182.5 34.24 ;
        END
    END d_b[1]
    PIN d_bready
        DIRECTION INPUT ; 
        USE SIGNAL ; 
        PORT
            LAYER met1 ;
              RECT  0 144.94 0.595 145.08 ;
        END
    END d_bready
    PIN d_bvalid
        DIRECTION OUTPUT ; 
        USE SIGNAL ; 
        PORT
            LAYER met2 ;
              RECT  138.16 182.015 138.3 182.5 ;
        END
    END d_bvalid
    PIN d_r[0]
        DIRECTION OUTPUT ; 
        USE SIGNAL ; 
        PORT
            LAYER met1 ;
              RECT  0 149.7 0.595 149.84 ;
        END
    END d_r[0]
    PIN d_r[10]
        DIRECTION OUTPUT ; 
        USE SIGNAL ; 
        PORT
            LAYER met1 ;
              RECT  181.905 72.18 182.5 72.32 ;
        END
    END d_r[10]
    PIN d_r[11]
        DIRECTION OUTPUT ; 
        USE SIGNAL ; 
        PORT
            LAYER met1 ;
              RECT  0 1.46 0.595 1.6 ;
        END
    END d_r[11]
    PIN d_r[12]
        DIRECTION OUTPUT ; 
        USE SIGNAL ; 
        PORT
            LAYER met2 ;
              RECT  9.36 182.015 9.5 182.5 ;
        END
    END d_r[12]
    PIN d_r[13]
        DIRECTION OUTPUT ; 
        USE SIGNAL ; 
        PORT
            LAYER met2 ;
              RECT  23.16 0 23.3 0.485 ;
        END
    END d_r[13]
    PIN d_r[14]
        DIRECTION OUTPUT ; 
        USE SIGNAL ; 
        PORT
            LAYER met1 ;
              RECT  181.905 167.38 182.5 167.52 ;
        END
    END d_r[14]
    PIN d_r[15]
        DIRECTION OUTPUT ; 
        USE SIGNAL ; 
        PORT
            LAYER met2 ;
              RECT  150.12 0 150.26 0.485 ;
        END
    END d_r[15]
    PIN d_r[16]
        DIRECTION OUTPUT ; 
        USE SIGNAL ; 
        PORT
            LAYER met1 ;
              RECT  181.905 93.26 182.5 93.4 ;
        END
    END d_r[16]
    PIN d_r[17]
        DIRECTION OUTPUT ; 
        USE SIGNAL ; 
        PORT
            LAYER met2 ;
              RECT  59.96 182.015 60.1 182.5 ;
        END
    END d_r[17]
    PIN d_r[18]
        DIRECTION OUTPUT ; 
        USE SIGNAL ; 
        PORT
            LAYER met2 ;
              RECT  132.64 0 132.78 0.485 ;
        END
    END d_r[18]
    PIN d_r[19]
        DIRECTION OUTPUT ; 
        USE SIGNAL ; 
        PORT
            LAYER met1 ;
              RECT  181.905 77.62 182.5 77.76 ;
        END
    END d_r[19]
    PIN d_r[1]
        DIRECTION OUTPUT ; 
        USE SIGNAL ; 
        PORT
            LAYER met2 ;
              RECT  128.04 0 128.18 0.485 ;
        END
    END d_r[1]
    PIN d_r[20]
        DIRECTION OUTPUT ; 
        USE SIGNAL ; 
        PORT
            LAYER met1 ;
              RECT  0 53.14 0.595 53.28 ;
        END
    END d_r[20]
    PIN d_r[21]
        DIRECTION OUTPUT ; 
        USE SIGNAL ; 
        PORT
            LAYER met2 ;
              RECT  158.4 182.015 158.54 182.5 ;
        END
    END d_r[21]
    PIN d_r[22]
        DIRECTION OUTPUT ; 
        USE SIGNAL ; 
        PORT
            LAYER met2 ;
              RECT  102.28 182.015 102.42 182.5 ;
        END
    END d_r[22]
    PIN d_r[23]
        DIRECTION OUTPUT ; 
        USE SIGNAL ; 
        PORT
            LAYER met2 ;
              RECT  179.56 0 179.7 0.485 ;
        END
    END d_r[23]
    PIN d_r[24]
        DIRECTION OUTPUT ; 
        USE SIGNAL ; 
        PORT
            LAYER met2 ;
              RECT  173.12 0 173.26 0.485 ;
        END
    END d_r[24]
    PIN d_r[25]
        DIRECTION OUTPUT ; 
        USE SIGNAL ; 
        PORT
            LAYER met2 ;
              RECT  12.12 0 12.26 0.485 ;
        END
    END d_r[25]
    PIN d_r[26]
        DIRECTION OUTPUT ; 
        USE SIGNAL ; 
        PORT
            LAYER met1 ;
              RECT  181.905 80.34 182.5 80.48 ;
        END
    END d_r[26]
    PIN d_r[27]
        DIRECTION OUTPUT ; 
        USE SIGNAL ; 
        PORT
            LAYER met1 ;
              RECT  181.905 180.98 182.5 181.12 ;
        END
    END d_r[27]
    PIN d_r[28]
        DIRECTION OUTPUT ; 
        USE SIGNAL ; 
        PORT
            LAYER met1 ;
              RECT  0 102.78 0.595 102.92 ;
        END
    END d_r[28]
    PIN d_r[29]
        DIRECTION OUTPUT ; 
        USE SIGNAL ; 
        PORT
            LAYER met2 ;
              RECT  10.28 0 10.42 0.485 ;
        END
    END d_r[29]
    PIN d_r[2]
        DIRECTION OUTPUT ; 
        USE SIGNAL ; 
        PORT
            LAYER met1 ;
              RECT  181.905 121.14 182.5 121.28 ;
        END
    END d_r[2]
    PIN d_r[30]
        DIRECTION OUTPUT ; 
        USE SIGNAL ; 
        PORT
            LAYER met2 ;
              RECT  86.64 182.015 86.78 182.5 ;
        END
    END d_r[30]
    PIN d_r[31]
        DIRECTION OUTPUT ; 
        USE SIGNAL ; 
        PORT
            LAYER met1 ;
              RECT  0 142.22 0.595 142.36 ;
        END
    END d_r[31]
    PIN d_r[32]
        DIRECTION OUTPUT ; 
        USE SIGNAL ; 
        PORT
            LAYER met1 ;
              RECT  181.905 133.38 182.5 133.52 ;
        END
    END d_r[32]
    PIN d_r[33]
        DIRECTION OUTPUT ; 
        USE SIGNAL ; 
        PORT
            LAYER met1 ;
              RECT  0 67.42 0.595 67.56 ;
        END
    END d_r[33]
    PIN d_r[3]
        DIRECTION OUTPUT ; 
        USE SIGNAL ; 
        PORT
            LAYER met1 ;
              RECT  181.905 87.14 182.5 87.28 ;
        END
    END d_r[3]
    PIN d_r[4]
        DIRECTION OUTPUT ; 
        USE SIGNAL ; 
        PORT
            LAYER met2 ;
              RECT  126.2 182.015 126.34 182.5 ;
        END
    END d_r[4]
    PIN d_r[5]
        DIRECTION OUTPUT ; 
        USE SIGNAL ; 
        PORT
            LAYER met2 ;
              RECT  71 0 71.14 0.485 ;
        END
    END d_r[5]
    PIN d_r[6]
        DIRECTION OUTPUT ; 
        USE SIGNAL ; 
        PORT
            LAYER met1 ;
              RECT  181.905 2.14 182.5 2.28 ;
        END
    END d_r[6]
    PIN d_r[7]
        DIRECTION OUTPUT ; 
        USE SIGNAL ; 
        PORT
            LAYER met1 ;
              RECT  0 62.66 0.595 62.8 ;
        END
    END d_r[7]
    PIN d_r[8]
        DIRECTION OUTPUT ; 
        USE SIGNAL ; 
        PORT
            LAYER met2 ;
              RECT  36.96 0 37.1 0.485 ;
        END
    END d_r[8]
    PIN d_r[9]
        DIRECTION OUTPUT ; 
        USE SIGNAL ; 
        PORT
            LAYER met1 ;
              RECT  181.905 101.42 182.5 101.56 ;
        END
    END d_r[9]
    PIN d_rready
        DIRECTION INPUT ; 
        USE SIGNAL ; 
        PORT
            LAYER met2 ;
              RECT  38.8 182.015 38.94 182.5 ;
        END
    END d_rready
    PIN d_rvalid
        DIRECTION OUTPUT ; 
        USE SIGNAL ; 
        PORT
            LAYER met2 ;
              RECT  154.72 0 154.86 0.485 ;
        END
    END d_rvalid
    PIN d_w[0]
        DIRECTION INPUT ; 
        USE SIGNAL ; 
        PORT
            LAYER met2 ;
              RECT  161.16 0 161.3 0.485 ;
        END
    END d_w[0]
    PIN d_w[10]
        DIRECTION INPUT ; 
        USE SIGNAL ; 
        PORT
            LAYER met1 ;
              RECT  0 122.5 0.595 122.64 ;
        END
    END d_w[10]
    PIN d_w[11]
        DIRECTION INPUT ; 
        USE SIGNAL ; 
        PORT
            LAYER met1 ;
              RECT  0 57.22 0.595 57.36 ;
        END
    END d_w[11]
    PIN d_w[12]
        DIRECTION INPUT ; 
        USE SIGNAL ; 
        PORT
            LAYER met2 ;
              RECT  53.52 182.015 53.66 182.5 ;
        END
    END d_w[12]
    PIN d_w[13]
        DIRECTION INPUT ; 
        USE SIGNAL ; 
        PORT
            LAYER met1 ;
              RECT  181.905 74.22 182.5 74.36 ;
        END
    END d_w[13]
    PIN d_w[14]
        DIRECTION INPUT ; 
        USE SIGNAL ; 
        PORT
            LAYER met1 ;
              RECT  181.905 83.74 182.5 83.88 ;
        END
    END d_w[14]
    PIN d_w[15]
        DIRECTION INPUT ; 
        USE SIGNAL ; 
        PORT
            LAYER met2 ;
              RECT  32.36 0 32.5 0.485 ;
        END
    END d_w[15]
    PIN d_w[16]
        DIRECTION INPUT ; 
        USE SIGNAL ; 
        PORT
            LAYER met2 ;
              RECT  7.52 0 7.66 0.485 ;
        END
    END d_w[16]
    PIN d_w[17]
        DIRECTION INPUT ; 
        USE SIGNAL ; 
        PORT
            LAYER met1 ;
              RECT  0 134.74 0.595 134.88 ;
        END
    END d_w[17]
    PIN d_w[18]
        DIRECTION INPUT ; 
        USE SIGNAL ; 
        PORT
            LAYER met1 ;
              RECT  0 161.94 0.595 162.08 ;
        END
    END d_w[18]
    PIN d_w[19]
        DIRECTION INPUT ; 
        USE SIGNAL ; 
        PORT
            LAYER met1 ;
              RECT  181.905 52.46 182.5 52.6 ;
        END
    END d_w[19]
    PIN d_w[1]
        DIRECTION INPUT ; 
        USE SIGNAL ; 
        PORT
            LAYER met1 ;
              RECT  0 140.86 0.595 141 ;
        END
    END d_w[1]
    PIN d_w[20]
        DIRECTION INPUT ; 
        USE SIGNAL ; 
        PORT
            LAYER met2 ;
              RECT  53.52 0 53.66 0.485 ;
        END
    END d_w[20]
    PIN d_w[21]
        DIRECTION INPUT ; 
        USE SIGNAL ; 
        PORT
            LAYER met1 ;
              RECT  181.905 169.42 182.5 169.56 ;
        END
    END d_w[21]
    PIN d_w[22]
        DIRECTION INPUT ; 
        USE SIGNAL ; 
        PORT
            LAYER met2 ;
              RECT  141.84 0 141.98 0.485 ;
        END
    END d_w[22]
    PIN d_w[23]
        DIRECTION INPUT ; 
        USE SIGNAL ; 
        PORT
            LAYER met1 ;
              RECT  181.905 144.94 182.5 145.08 ;
        END
    END d_w[23]
    PIN d_w[24]
        DIRECTION INPUT ; 
        USE SIGNAL ; 
        PORT
            LAYER met2 ;
              RECT  38.8 0 38.94 0.485 ;
        END
    END d_w[24]
    PIN d_w[25]
        DIRECTION INPUT ; 
        USE SIGNAL ; 
        PORT
            LAYER met1 ;
              RECT  181.905 42.26 182.5 42.4 ;
        END
    END d_w[25]
    PIN d_w[26]
        DIRECTION INPUT ; 
        USE SIGNAL ; 
        PORT
            LAYER met1 ;
              RECT  0 3.5 0.595 3.64 ;
        END
    END d_w[26]
    PIN d_w[27]
        DIRECTION INPUT ; 
        USE SIGNAL ; 
        PORT
            LAYER met2 ;
              RECT  135.4 0 135.54 0.485 ;
        END
    END d_w[27]
    PIN d_w[28]
        DIRECTION INPUT ; 
        USE SIGNAL ; 
        PORT
            LAYER met2 ;
              RECT  47.08 182.015 47.22 182.5 ;
        END
    END d_w[28]
    PIN d_w[29]
        DIRECTION INPUT ; 
        USE SIGNAL ; 
        PORT
            LAYER met1 ;
              RECT  0 70.82 0.595 70.96 ;
        END
    END d_w[29]
    PIN d_w[2]
        DIRECTION INPUT ; 
        USE SIGNAL ; 
        PORT
            LAYER met1 ;
              RECT  0 2.82 0.595 2.96 ;
        END
    END d_w[2]
    PIN d_w[30]
        DIRECTION INPUT ; 
        USE SIGNAL ; 
        PORT
            LAYER met1 ;
              RECT  181.905 40.22 182.5 40.36 ;
        END
    END d_w[30]
    PIN d_w[31]
        DIRECTION INPUT ; 
        USE SIGNAL ; 
        PORT
            LAYER met2 ;
              RECT  1.08 182.015 1.22 182.5 ;
        END
    END d_w[31]
    PIN d_w[32]
        DIRECTION INPUT ; 
        USE SIGNAL ; 
        PORT
            LAYER met2 ;
              RECT  91.24 0 91.38 0.485 ;
        END
    END d_w[32]
    PIN d_w[33]
        DIRECTION INPUT ; 
        USE SIGNAL ; 
        PORT
            LAYER met1 ;
              RECT  181.905 39.54 182.5 39.68 ;
        END
    END d_w[33]
    PIN d_w[34]
        DIRECTION INPUT ; 
        USE SIGNAL ; 
        PORT
            LAYER met1 ;
              RECT  181.905 8.94 182.5 9.08 ;
        END
    END d_w[34]
    PIN d_w[35]
        DIRECTION INPUT ; 
        USE SIGNAL ; 
        PORT
            LAYER met1 ;
              RECT  0 175.54 0.595 175.68 ;
        END
    END d_w[35]
    PIN d_w[3]
        DIRECTION INPUT ; 
        USE SIGNAL ; 
        PORT
            LAYER met2 ;
              RECT  43.4 182.015 43.54 182.5 ;
        END
    END d_w[3]
    PIN d_w[4]
        DIRECTION INPUT ; 
        USE SIGNAL ; 
        PORT
            LAYER met1 ;
              RECT  181.905 93.94 182.5 94.08 ;
        END
    END d_w[4]
    PIN d_w[5]
        DIRECTION INPUT ; 
        USE SIGNAL ; 
        PORT
            LAYER met1 ;
              RECT  181.905 28.66 182.5 28.8 ;
        END
    END d_w[5]
    PIN d_w[6]
        DIRECTION INPUT ; 
        USE SIGNAL ; 
        PORT
            LAYER met2 ;
              RECT  25 182.015 25.14 182.5 ;
        END
    END d_w[6]
    PIN d_w[7]
        DIRECTION INPUT ; 
        USE SIGNAL ; 
        PORT
            LAYER met1 ;
              RECT  0 65.38 0.595 65.52 ;
        END
    END d_w[7]
    PIN d_w[8]
        DIRECTION INPUT ; 
        USE SIGNAL ; 
        PORT
            LAYER met2 ;
              RECT  55.36 0 55.5 0.485 ;
        END
    END d_w[8]
    PIN d_w[9]
        DIRECTION INPUT ; 
        USE SIGNAL ; 
        PORT
            LAYER met2 ;
              RECT  100.44 182.015 100.58 182.5 ;
        END
    END d_w[9]
    PIN d_wready
        DIRECTION OUTPUT ; 
        USE SIGNAL ; 
        PORT
            LAYER met2 ;
              RECT  117.92 182.015 118.06 182.5 ;
        END
    END d_wready
    PIN d_wvalid
        DIRECTION INPUT ; 
        USE SIGNAL ; 
        PORT
            LAYER met2 ;
              RECT  144.6 0 144.74 0.485 ;
        END
    END d_wvalid
    PIN h_ar[0]
        DIRECTION INPUT ; 
        USE SIGNAL ; 
        PORT
            LAYER met1 ;
              RECT  181.905 58.58 182.5 58.72 ;
        END
    END h_ar[0]
    PIN h_ar[10]
        DIRECTION INPUT ; 
        USE SIGNAL ; 
        PORT
            LAYER met1 ;
              RECT  0 106.86 0.595 107 ;
        END
    END h_ar[10]
    PIN h_ar[11]
        DIRECTION INPUT ; 
        USE SIGNAL ; 
        PORT
            LAYER met1 ;
              RECT  0 164.66 0.595 164.8 ;
        END
    END h_ar[11]
    PIN h_ar[12]
        DIRECTION INPUT ; 
        USE SIGNAL ; 
        PORT
            LAYER met1 ;
              RECT  0 168.74 0.595 168.88 ;
        END
    END h_ar[12]
    PIN h_ar[13]
        DIRECTION INPUT ; 
        USE SIGNAL ; 
        PORT
            LAYER met1 ;
              RECT  0 81.02 0.595 81.16 ;
        END
    END h_ar[13]
    PIN h_ar[14]
        DIRECTION INPUT ; 
        USE SIGNAL ; 
        PORT
            LAYER met1 ;
              RECT  0 84.42 0.595 84.56 ;
        END
    END h_ar[14]
    PIN h_ar[15]
        DIRECTION INPUT ; 
        USE SIGNAL ; 
        PORT
            LAYER met2 ;
              RECT  44.32 0 44.46 0.485 ;
        END
    END h_ar[15]
    PIN h_ar[16]
        DIRECTION INPUT ; 
        USE SIGNAL ; 
        PORT
            LAYER met1 ;
              RECT  0 166.7 0.595 166.84 ;
        END
    END h_ar[16]
    PIN h_ar[17]
        DIRECTION INPUT ; 
        USE SIGNAL ; 
        PORT
            LAYER met2 ;
              RECT  4.76 0 4.9 0.485 ;
        END
    END h_ar[17]
    PIN h_ar[18]
        DIRECTION INPUT ; 
        USE SIGNAL ; 
        PORT
            LAYER met2 ;
              RECT  45.24 0 45.38 0.485 ;
        END
    END h_ar[18]
    PIN h_ar[19]
        DIRECTION INPUT ; 
        USE SIGNAL ; 
        PORT
            LAYER met1 ;
              RECT  181.905 171.46 182.5 171.6 ;
        END
    END h_ar[19]
    PIN h_ar[1]
        DIRECTION INPUT ; 
        USE SIGNAL ; 
        PORT
            LAYER met2 ;
              RECT  129.88 182.015 130.02 182.5 ;
        END
    END h_ar[1]
    PIN h_ar[20]
        DIRECTION INPUT ; 
        USE SIGNAL ; 
        PORT
            LAYER met1 ;
              RECT  0 128.62 0.595 128.76 ;
        END
    END h_ar[20]
    PIN h_ar[21]
        DIRECTION INPUT ; 
        USE SIGNAL ; 
        PORT
            LAYER met1 ;
              RECT  0 31.38 0.595 31.52 ;
        END
    END h_ar[21]
    PIN h_ar[22]
        DIRECTION INPUT ; 
        USE SIGNAL ; 
        PORT
            LAYER met2 ;
              RECT  76.52 0 76.66 0.485 ;
        END
    END h_ar[22]
    PIN h_ar[23]
        DIRECTION INPUT ; 
        USE SIGNAL ; 
        PORT
            LAYER met1 ;
              RECT  0 56.54 0.595 56.68 ;
        END
    END h_ar[23]
    PIN h_ar[24]
        DIRECTION INPUT ; 
        USE SIGNAL ; 
        PORT
            LAYER met1 ;
              RECT  0 147.66 0.595 147.8 ;
        END
    END h_ar[24]
    PIN h_ar[25]
        DIRECTION INPUT ; 
        USE SIGNAL ; 
        PORT
            LAYER met2 ;
              RECT  135.4 182.015 135.54 182.5 ;
        END
    END h_ar[25]
    PIN h_ar[26]
        DIRECTION INPUT ; 
        USE SIGNAL ; 
        PORT
            LAYER met2 ;
              RECT  128.96 182.015 129.1 182.5 ;
        END
    END h_ar[26]
    PIN h_ar[27]
        DIRECTION INPUT ; 
        USE SIGNAL ; 
        PORT
            LAYER met1 ;
              RECT  181.905 164.66 182.5 164.8 ;
        END
    END h_ar[27]
    PIN h_ar[28]
        DIRECTION INPUT ; 
        USE SIGNAL ; 
        PORT
            LAYER met1 ;
              RECT  181.905 146.98 182.5 147.12 ;
        END
    END h_ar[28]
    PIN h_ar[29]
        DIRECTION INPUT ; 
        USE SIGNAL ; 
        PORT
            LAYER met1 ;
              RECT  181.905 89.18 182.5 89.32 ;
        END
    END h_ar[29]
    PIN h_ar[2]
        DIRECTION INPUT ; 
        USE SIGNAL ; 
        PORT
            LAYER met2 ;
              RECT  92.16 182.015 92.3 182.5 ;
        END
    END h_ar[2]
    PIN h_ar[30]
        DIRECTION INPUT ; 
        USE SIGNAL ; 
        PORT
            LAYER met2 ;
              RECT  118.84 182.015 118.98 182.5 ;
        END
    END h_ar[30]
    PIN h_ar[31]
        DIRECTION INPUT ; 
        USE SIGNAL ; 
        PORT
            LAYER met2 ;
              RECT  173.12 182.015 173.26 182.5 ;
        END
    END h_ar[31]
    PIN h_ar[32]
        DIRECTION INPUT ; 
        USE SIGNAL ; 
        PORT
            LAYER met1 ;
              RECT  181.905 56.54 182.5 56.68 ;
        END
    END h_ar[32]
    PIN h_ar[33]
        DIRECTION INPUT ; 
        USE SIGNAL ; 
        PORT
            LAYER met1 ;
              RECT  181.905 123.18 182.5 123.32 ;
        END
    END h_ar[33]
    PIN h_ar[34]
        DIRECTION INPUT ; 
        USE SIGNAL ; 
        PORT
            LAYER met1 ;
              RECT  0 8.94 0.595 9.08 ;
        END
    END h_ar[34]
    PIN h_ar[3]
        DIRECTION INPUT ; 
        USE SIGNAL ; 
        PORT
            LAYER met2 ;
              RECT  85.72 0 85.86 0.485 ;
        END
    END h_ar[3]
    PIN h_ar[4]
        DIRECTION INPUT ; 
        USE SIGNAL ; 
        PORT
            LAYER met1 ;
              RECT  181.905 153.78 182.5 153.92 ;
        END
    END h_ar[4]
    PIN h_ar[5]
        DIRECTION INPUT ; 
        USE SIGNAL ; 
        PORT
            LAYER met1 ;
              RECT  0 17.1 0.595 17.24 ;
        END
    END h_ar[5]
    PIN h_ar[6]
        DIRECTION INPUT ; 
        USE SIGNAL ; 
        PORT
            LAYER met2 ;
              RECT  176.8 0 176.94 0.485 ;
        END
    END h_ar[6]
    PIN h_ar[7]
        DIRECTION INPUT ; 
        USE SIGNAL ; 
        PORT
            LAYER met1 ;
              RECT  181.905 95.3 182.5 95.44 ;
        END
    END h_ar[7]
    PIN h_ar[8]
        DIRECTION INPUT ; 
        USE SIGNAL ; 
        PORT
            LAYER met1 ;
              RECT  181.905 104.14 182.5 104.28 ;
        END
    END h_ar[8]
    PIN h_ar[9]
        DIRECTION INPUT ; 
        USE SIGNAL ; 
        PORT
            LAYER met2 ;
              RECT  84.8 0 84.94 0.485 ;
        END
    END h_ar[9]
    PIN h_arready
        DIRECTION OUTPUT ; 
        USE SIGNAL ; 
        PORT
            LAYER met1 ;
              RECT  0 78.98 0.595 79.12 ;
        END
    END h_arready
    PIN h_arvalid
        DIRECTION INPUT ; 
        USE SIGNAL ; 
        PORT
            LAYER met1 ;
              RECT  0 64.7 0.595 64.84 ;
        END
    END h_arvalid
    PIN h_aw[0]
        DIRECTION INPUT ; 
        USE SIGNAL ; 
        PORT
            LAYER met1 ;
              RECT  181.905 106.18 182.5 106.32 ;
        END
    END h_aw[0]
    PIN h_aw[10]
        DIRECTION INPUT ; 
        USE SIGNAL ; 
        PORT
            LAYER met1 ;
              RECT  0 54.5 0.595 54.64 ;
        END
    END h_aw[10]
    PIN h_aw[11]
        DIRECTION INPUT ; 
        USE SIGNAL ; 
        PORT
            LAYER met2 ;
              RECT  48.92 182.015 49.06 182.5 ;
        END
    END h_aw[11]
    PIN h_aw[12]
        DIRECTION INPUT ; 
        USE SIGNAL ; 
        PORT
            LAYER met1 ;
              RECT  181.905 125.22 182.5 125.36 ;
        END
    END h_aw[12]
    PIN h_aw[13]
        DIRECTION INPUT ; 
        USE SIGNAL ; 
        PORT
            LAYER met1 ;
              RECT  181.905 129.3 182.5 129.44 ;
        END
    END h_aw[13]
    PIN h_aw[14]
        DIRECTION INPUT ; 
        USE SIGNAL ; 
        PORT
            LAYER met1 ;
              RECT  181.905 151.06 182.5 151.2 ;
        END
    END h_aw[14]
    PIN h_aw[15]
        DIRECTION INPUT ; 
        USE SIGNAL ; 
        PORT
            LAYER met1 ;
              RECT  181.905 55.86 182.5 56 ;
        END
    END h_aw[15]
    PIN h_aw[16]
        DIRECTION INPUT ; 
        USE SIGNAL ; 
        PORT
            LAYER met1 ;
              RECT  0 86.46 0.595 86.6 ;
        END
    END h_aw[16]
    PIN h_aw[17]
        DIRECTION INPUT ; 
        USE SIGNAL ; 
        PORT
            LAYER met1 ;
              RECT  181.905 84.42 182.5 84.56 ;
        END
    END h_aw[17]
    PIN h_aw[18]
        DIRECTION INPUT ; 
        USE SIGNAL ; 
        PORT
            LAYER met1 ;
              RECT  0 136.78 0.595 136.92 ;
        END
    END h_aw[18]
    PIN h_aw[19]
        DIRECTION INPUT ; 
        USE SIGNAL ; 
        PORT
            LAYER met2 ;
              RECT  143.68 0 143.82 0.485 ;
        END
    END h_aw[19]
    PIN h_aw[1]
        DIRECTION INPUT ; 
        USE SIGNAL ; 
        PORT
            LAYER met2 ;
              RECT  3.84 182.015 3.98 182.5 ;
        END
    END h_aw[1]
    PIN h_aw[20]
        DIRECTION INPUT ; 
        USE SIGNAL ; 
        PORT
            LAYER met2 ;
              RECT  166.68 182.015 166.82 182.5 ;
        END
    END h_aw[20]
    PIN h_aw[21]
        DIRECTION INPUT ; 
        USE SIGNAL ; 
        PORT
            LAYER met2 ;
              RECT  159.32 182.015 159.46 182.5 ;
        END
    END h_aw[21]
    PIN h_aw[22]
        DIRECTION INPUT ; 
        USE SIGNAL ; 
        PORT
            LAYER met2 ;
              RECT  54.44 182.015 54.58 182.5 ;
        END
    END h_aw[22]
    PIN h_aw[23]
        DIRECTION INPUT ; 
        USE SIGNAL ; 
        PORT
            LAYER met1 ;
              RECT  181.905 61.98 182.5 62.12 ;
        END
    END h_aw[23]
    PIN h_aw[24]
        DIRECTION INPUT ; 
        USE SIGNAL ; 
        PORT
            LAYER met1 ;
              RECT  0 13.02 0.595 13.16 ;
        END
    END h_aw[24]
    PIN h_aw[25]
        DIRECTION INPUT ; 
        USE SIGNAL ; 
        PORT
            LAYER met2 ;
              RECT  123.44 0 123.58 0.485 ;
        END
    END h_aw[25]
    PIN h_aw[26]
        DIRECTION INPUT ; 
        USE SIGNAL ; 
        PORT
            LAYER met2 ;
              RECT  62.72 182.015 62.86 182.5 ;
        END
    END h_aw[26]
    PIN h_aw[27]
        DIRECTION INPUT ; 
        USE SIGNAL ; 
        PORT
            LAYER met1 ;
              RECT  181.905 64.02 182.5 64.16 ;
        END
    END h_aw[27]
    PIN h_aw[28]
        DIRECTION INPUT ; 
        USE SIGNAL ; 
        PORT
            LAYER met1 ;
              RECT  181.905 10.98 182.5 11.12 ;
        END
    END h_aw[28]
    PIN h_aw[29]
        DIRECTION INPUT ; 
        USE SIGNAL ; 
        PORT
            LAYER met1 ;
              RECT  0 172.14 0.595 172.28 ;
        END
    END h_aw[29]
    PIN h_aw[2]
        DIRECTION INPUT ; 
        USE SIGNAL ; 
        PORT
            LAYER met1 ;
              RECT  181.905 98.02 182.5 98.16 ;
        END
    END h_aw[2]
    PIN h_aw[30]
        DIRECTION INPUT ; 
        USE SIGNAL ; 
        PORT
            LAYER met2 ;
              RECT  13.96 182.015 14.1 182.5 ;
        END
    END h_aw[30]
    PIN h_aw[31]
        DIRECTION INPUT ; 
        USE SIGNAL ; 
        PORT
            LAYER met2 ;
              RECT  73.76 182.015 73.9 182.5 ;
        END
    END h_aw[31]
    PIN h_aw[32]
        DIRECTION INPUT ; 
        USE SIGNAL ; 
        PORT
            LAYER met1 ;
              RECT  181.905 158.54 182.5 158.68 ;
        END
    END h_aw[32]
    PIN h_aw[33]
        DIRECTION INPUT ; 
        USE SIGNAL ; 
        PORT
            LAYER met1 ;
              RECT  0 36.82 0.595 36.96 ;
        END
    END h_aw[33]
    PIN h_aw[34]
        DIRECTION INPUT ; 
        USE SIGNAL ; 
        PORT
            LAYER met2 ;
              RECT  105.04 182.015 105.18 182.5 ;
        END
    END h_aw[34]
    PIN h_aw[3]
        DIRECTION INPUT ; 
        USE SIGNAL ; 
        PORT
            LAYER met2 ;
              RECT  83.88 182.015 84.02 182.5 ;
        END
    END h_aw[3]
    PIN h_aw[4]
        DIRECTION INPUT ; 
        USE SIGNAL ; 
        PORT
            LAYER met2 ;
              RECT  134.48 182.015 134.62 182.5 ;
        END
    END h_aw[4]
    PIN h_aw[5]
        DIRECTION INPUT ; 
        USE SIGNAL ; 
        PORT
            LAYER met2 ;
              RECT  34.2 0 34.34 0.485 ;
        END
    END h_aw[5]
    PIN h_aw[6]
        DIRECTION INPUT ; 
        USE SIGNAL ; 
        PORT
            LAYER met2 ;
              RECT  27.76 182.015 27.9 182.5 ;
        END
    END h_aw[6]
    PIN h_aw[7]
        DIRECTION INPUT ; 
        USE SIGNAL ; 
        PORT
            LAYER met1 ;
              RECT  0 40.9 0.595 41.04 ;
        END
    END h_aw[7]
    PIN h_aw[8]
        DIRECTION INPUT ; 
        USE SIGNAL ; 
        PORT
            LAYER met1 ;
              RECT  0 27.3 0.595 27.44 ;
        END
    END h_aw[8]
    PIN h_aw[9]
        DIRECTION INPUT ; 
        USE SIGNAL ; 
        PORT
            LAYER met1 ;
              RECT  0 96.66 0.595 96.8 ;
        END
    END h_aw[9]
    PIN h_awready
        DIRECTION OUTPUT ; 
        USE SIGNAL ; 
        PORT
            LAYER met2 ;
              RECT  33.28 182.015 33.42 182.5 ;
        END
    END h_awready
    PIN h_awvalid
        DIRECTION INPUT ; 
        USE SIGNAL ; 
        PORT
            LAYER met1 ;
              RECT  181.905 81.7 182.5 81.84 ;
        END
    END h_awvalid
    PIN h_b[0]
        DIRECTION OUTPUT ; 
        USE SIGNAL ; 
        PORT
            LAYER met2 ;
              RECT  103.2 0 103.34 0.485 ;
        END
    END h_b[0]
    PIN h_b[1]
        DIRECTION OUTPUT ; 
        USE SIGNAL ; 
        PORT
            LAYER met1 ;
              RECT  181.905 69.46 182.5 69.6 ;
        END
    END h_b[1]
    PIN h_bready
        DIRECTION INPUT ; 
        USE SIGNAL ; 
        PORT
            LAYER met1 ;
              RECT  0 100.74 0.595 100.88 ;
        END
    END h_bready
    PIN h_bvalid
        DIRECTION OUTPUT ; 
        USE SIGNAL ; 
        PORT
            LAYER met2 ;
              RECT  21.32 182.015 21.46 182.5 ;
        END
    END h_bvalid
    PIN h_r[0]
        DIRECTION OUTPUT ; 
        USE SIGNAL ; 
        PORT
            LAYER met2 ;
              RECT  120.68 0 120.82 0.485 ;
        END
    END h_r[0]
    PIN h_r[10]
        DIRECTION OUTPUT ; 
        USE SIGNAL ; 
        PORT
            LAYER met2 ;
              RECT  30.52 182.015 30.66 182.5 ;
        END
    END h_r[10]
    PIN h_r[11]
        DIRECTION OUTPUT ; 
        USE SIGNAL ; 
        PORT
            LAYER met2 ;
              RECT  24.08 182.015 24.22 182.5 ;
        END
    END h_r[11]
    PIN h_r[12]
        DIRECTION OUTPUT ; 
        USE SIGNAL ; 
        PORT
            LAYER met2 ;
              RECT  181.4 0 181.54 0.485 ;
        END
    END h_r[12]
    PIN h_r[13]
        DIRECTION OUTPUT ; 
        USE SIGNAL ; 
        PORT
            LAYER met1 ;
              RECT  181.905 30.02 182.5 30.16 ;
        END
    END h_r[13]
    PIN h_r[14]
        DIRECTION OUTPUT ; 
        USE SIGNAL ; 
        PORT
            LAYER met2 ;
              RECT  175.88 182.015 176.02 182.5 ;
        END
    END h_r[14]
    PIN h_r[15]
        DIRECTION OUTPUT ; 
        USE SIGNAL ; 
        PORT
            LAYER met2 ;
              RECT  40.64 182.015 40.78 182.5 ;
        END
    END h_r[15]
    PIN h_r[16]
        DIRECTION OUTPUT ; 
        USE SIGNAL ; 
        PORT
            LAYER met2 ;
              RECT  119.76 0 119.9 0.485 ;
        END
    END h_r[16]
    PIN h_r[17]
        DIRECTION OUTPUT ; 
        USE SIGNAL ; 
        PORT
            LAYER met2 ;
              RECT  15.8 0 15.94 0.485 ;
        END
    END h_r[17]
    PIN h_r[18]
        DIRECTION OUTPUT ; 
        USE SIGNAL ; 
        PORT
            LAYER met2 ;
              RECT  161.16 182.015 161.3 182.5 ;
        END
    END h_r[18]
    PIN h_r[19]
        DIRECTION OUTPUT ; 
        USE SIGNAL ; 
        PORT
            LAYER met1 ;
              RECT  0 89.18 0.595 89.32 ;
        END
    END h_r[19]
    PIN h_r[1]
        DIRECTION OUTPUT ; 
        USE SIGNAL ; 
        PORT
            LAYER met2 ;
              RECT  66.4 0 66.54 0.485 ;
        END
    END h_r[1]
    PIN h_r[20]
        DIRECTION OUTPUT ; 
        USE SIGNAL ; 
        PORT
            LAYER met1 ;
              RECT  0 119.1 0.595 119.24 ;
        END
    END h_r[20]
    PIN h_r[21]
        DIRECTION OUTPUT ; 
        USE SIGNAL ; 
        PORT
            LAYER met1 ;
              RECT  181.905 105.5 182.5 105.64 ;
        END
    END h_r[21]
    PIN h_r[22]
        DIRECTION OUTPUT ; 
        USE SIGNAL ; 
        PORT
            LAYER met1 ;
              RECT  0 162.62 0.595 162.76 ;
        END
    END h_r[22]
    PIN h_r[23]
        DIRECTION OUTPUT ; 
        USE SIGNAL ; 
        PORT
            LAYER met1 ;
              RECT  0 43.62 0.595 43.76 ;
        END
    END h_r[23]
    PIN h_r[24]
        DIRECTION OUTPUT ; 
        USE SIGNAL ; 
        PORT
            LAYER met1 ;
              RECT  0 7.58 0.595 7.72 ;
        END
    END h_r[24]
    PIN h_r[25]
        DIRECTION OUTPUT ; 
        USE SIGNAL ; 
        PORT
            LAYER met2 ;
              RECT  114.24 0 114.38 0.485 ;
        END
    END h_r[25]
    PIN h_r[26]
        DIRECTION OUTPUT ; 
        USE SIGNAL ; 
        PORT
            LAYER met2 ;
              RECT  164.84 182.015 164.98 182.5 ;
        END
    END h_r[26]
    PIN h_r[27]
        DIRECTION OUTPUT ; 
        USE SIGNAL ; 
        PORT
            LAYER met1 ;
              RECT  0 19.14 0.595 19.28 ;
        END
    END h_r[27]
    PIN h_r[28]
        DIRECTION OUTPUT ; 
        USE SIGNAL ; 
        PORT
            LAYER met2 ;
              RECT  131.72 182.015 131.86 182.5 ;
        END
    END h_r[28]
    PIN h_r[29]
        DIRECTION OUTPUT ; 
        USE SIGNAL ; 
        PORT
            LAYER met2 ;
              RECT  29.6 0 29.74 0.485 ;
        END
    END h_r[29]
    PIN h_r[2]
        DIRECTION OUTPUT ; 
        USE SIGNAL ; 
        PORT
            LAYER met2 ;
              RECT  170.36 0 170.5 0.485 ;
        END
    END h_r[2]
    PIN h_r[30]
        DIRECTION OUTPUT ; 
        USE SIGNAL ; 
        PORT
            LAYER met1 ;
              RECT  0 134.06 0.595 134.2 ;
        END
    END h_r[30]
    PIN h_r[31]
        DIRECTION OUTPUT ; 
        USE SIGNAL ; 
        PORT
            LAYER met1 ;
              RECT  181.905 110.94 182.5 111.08 ;
        END
    END h_r[31]
    PIN h_r[32]
        DIRECTION OUTPUT ; 
        USE SIGNAL ; 
        PORT
            LAYER met1 ;
              RECT  181.905 61.3 182.5 61.44 ;
        END
    END h_r[32]
    PIN h_r[33]
        DIRECTION OUTPUT ; 
        USE SIGNAL ; 
        PORT
            LAYER met1 ;
              RECT  0 34.78 0.595 34.92 ;
        END
    END h_r[33]
    PIN h_r[3]
        DIRECTION OUTPUT ; 
        USE SIGNAL ; 
        PORT
            LAYER met2 ;
              RECT  104.12 0 104.26 0.485 ;
        END
    END h_r[3]
    PIN h_r[4]
        DIRECTION OUTPUT ; 
        USE SIGNAL ; 
        PORT
            LAYER met2 ;
              RECT  152.88 0 153.02 0.485 ;
        END
    END h_r[4]
    PIN h_r[5]
        DIRECTION OUTPUT ; 
        USE SIGNAL ; 
        PORT
            LAYER met2 ;
              RECT  80.2 0 80.34 0.485 ;
        END
    END h_r[5]
    PIN h_r[6]
        DIRECTION OUTPUT ; 
        USE SIGNAL ; 
        PORT
            LAYER met1 ;
              RECT  0 85.1 0.595 85.24 ;
        END
    END h_r[6]
    PIN h_r[7]
        DIRECTION OUTPUT ; 
        USE SIGNAL ; 
        PORT
            LAYER met2 ;
              RECT  117 0 117.14 0.485 ;
        END
    END h_r[7]
    PIN h_r[8]
        DIRECTION OUTPUT ; 
        USE SIGNAL ; 
        PORT
            LAYER met1 ;
              RECT  0 126.58 0.595 126.72 ;
        END
    END h_r[8]
    PIN h_r[9]
        DIRECTION OUTPUT ; 
        USE SIGNAL ; 
        PORT
            LAYER met1 ;
              RECT  0 153.78 0.595 153.92 ;
        END
    END h_r[9]
    PIN h_rready
        DIRECTION INPUT ; 
        USE SIGNAL ; 
        PORT
            LAYER met2 ;
              RECT  58.12 0 58.26 0.485 ;
        END
    END h_rready
    PIN h_rvalid
        DIRECTION OUTPUT ; 
        USE SIGNAL ; 
        PORT
            LAYER met1 ;
              RECT  0 21.18 0.595 21.32 ;
        END
    END h_rvalid
    PIN h_w[0]
        DIRECTION INPUT ; 
        USE SIGNAL ; 
        PORT
            LAYER met1 ;
              RECT  181.905 41.58 182.5 41.72 ;
        END
    END h_w[0]
    PIN h_w[10]
        DIRECTION INPUT ; 
        USE SIGNAL ; 
        PORT
            LAYER met1 ;
              RECT  181.905 59.94 182.5 60.08 ;
        END
    END h_w[10]
    PIN h_w[11]
        DIRECTION INPUT ; 
        USE SIGNAL ; 
        PORT
            LAYER met2 ;
              RECT  82.04 0 82.18 0.485 ;
        END
    END h_w[11]
    PIN h_w[12]
        DIRECTION INPUT ; 
        USE SIGNAL ; 
        PORT
            LAYER met2 ;
              RECT  151.96 0 152.1 0.485 ;
        END
    END h_w[12]
    PIN h_w[13]
        DIRECTION INPUT ; 
        USE SIGNAL ; 
        PORT
            LAYER met2 ;
              RECT  175.88 0 176.02 0.485 ;
        END
    END h_w[13]
    PIN h_w[14]
        DIRECTION INPUT ; 
        USE SIGNAL ; 
        PORT
            LAYER met1 ;
              RECT  0 29.34 0.595 29.48 ;
        END
    END h_w[14]
    PIN h_w[15]
        DIRECTION INPUT ; 
        USE SIGNAL ; 
        PORT
            LAYER met1 ;
              RECT  181.905 107.54 182.5 107.68 ;
        END
    END h_w[15]
    PIN h_w[16]
        DIRECTION INPUT ; 
        USE SIGNAL ; 
        PORT
            LAYER met2 ;
              RECT  138.16 0 138.3 0.485 ;
        END
    END h_w[16]
    PIN h_w[17]
        DIRECTION INPUT ; 
        USE SIGNAL ; 
        PORT
            LAYER met2 ;
              RECT  146.44 182.015 146.58 182.5 ;
        END
    END h_w[17]
    PIN h_w[18]
        DIRECTION INPUT ; 
        USE SIGNAL ; 
        PORT
            LAYER met1 ;
              RECT  181.905 0.78 182.5 0.92 ;
        END
    END h_w[18]
    PIN h_w[19]
        DIRECTION INPUT ; 
        USE SIGNAL ; 
        PORT
            LAYER met2 ;
              RECT  63.64 0 63.78 0.485 ;
        END
    END h_w[19]
    PIN h_w[1]
        DIRECTION INPUT ; 
        USE SIGNAL ; 
        PORT
            LAYER met2 ;
              RECT  168.52 0 168.66 0.485 ;
        END
    END h_w[1]
    PIN h_w[20]
        DIRECTION INPUT ; 
        USE SIGNAL ; 
        PORT
            LAYER met2 ;
              RECT  148.28 182.015 148.42 182.5 ;
        END
    END h_w[20]
    PIN h_w[21]
        DIRECTION INPUT ; 
        USE SIGNAL ; 
        PORT
            LAYER met1 ;
              RECT  181.905 27.98 182.5 28.12 ;
        END
    END h_w[21]
    PIN h_w[22]
        DIRECTION INPUT ; 
        USE SIGNAL ; 
        PORT
            LAYER met2 ;
              RECT  35.12 182.015 35.26 182.5 ;
        END
    END h_w[22]
    PIN h_w[23]
        DIRECTION INPUT ; 
        USE SIGNAL ; 
        PORT
            LAYER met1 ;
              RECT  181.905 45.66 182.5 45.8 ;
        END
    END h_w[23]
    PIN h_w[24]
        DIRECTION INPUT ; 
        USE SIGNAL ; 
        PORT
            LAYER met2 ;
              RECT  56.28 0 56.42 0.485 ;
        END
    END h_w[24]
    PIN h_w[25]
        DIRECTION INPUT ; 
        USE SIGNAL ; 
        PORT
            LAYER met2 ;
              RECT  64.56 182.015 64.7 182.5 ;
        END
    END h_w[25]
    PIN h_w[26]
        DIRECTION INPUT ; 
        USE SIGNAL ; 
        PORT
            LAYER met1 ;
              RECT  181.905 115.02 182.5 115.16 ;
        END
    END h_w[26]
    PIN h_w[27]
        DIRECTION INPUT ; 
        USE SIGNAL ; 
        PORT
            LAYER met2 ;
              RECT  132.64 182.015 132.78 182.5 ;
        END
    END h_w[27]
    PIN h_w[28]
        DIRECTION INPUT ; 
        USE SIGNAL ; 
        PORT
            LAYER met1 ;
              RECT  181.905 145.62 182.5 145.76 ;
        END
    END h_w[28]
    PIN h_w[29]
        DIRECTION INPUT ; 
        USE SIGNAL ; 
        PORT
            LAYER met1 ;
              RECT  0 82.38 0.595 82.52 ;
        END
    END h_w[29]
    PIN h_w[2]
        DIRECTION INPUT ; 
        USE SIGNAL ; 
        PORT
            LAYER met2 ;
              RECT  91.24 182.015 91.38 182.5 ;
        END
    END h_w[2]
    PIN h_w[30]
        DIRECTION INPUT ; 
        USE SIGNAL ; 
        PORT
            LAYER met2 ;
              RECT  112.4 0 112.54 0.485 ;
        END
    END h_w[30]
    PIN h_w[31]
        DIRECTION INPUT ; 
        USE SIGNAL ; 
        PORT
            LAYER met1 ;
              RECT  181.905 87.82 182.5 87.96 ;
        END
    END h_w[31]
    PIN h_w[32]
        DIRECTION INPUT ; 
        USE SIGNAL ; 
        PORT
            LAYER met1 ;
              RECT  181.905 115.7 182.5 115.84 ;
        END
    END h_w[32]
    PIN h_w[33]
        DIRECTION INPUT ; 
        USE SIGNAL ; 
        PORT
            LAYER met2 ;
              RECT  77.44 0 77.58 0.485 ;
        END
    END h_w[33]
    PIN h_w[34]
        DIRECTION INPUT ; 
        USE SIGNAL ; 
        PORT
            LAYER met1 ;
              RECT  181.905 155.82 182.5 155.96 ;
        END
    END h_w[34]
    PIN h_w[35]
        DIRECTION INPUT ; 
        USE SIGNAL ; 
        PORT
            LAYER met1 ;
              RECT  0 108.22 0.595 108.36 ;
        END
    END h_w[35]
    PIN h_w[3]
        DIRECTION INPUT ; 
        USE SIGNAL ; 
        PORT
            LAYER met1 ;
              RECT  181.905 66.06 182.5 66.2 ;
        END
    END h_w[3]
    PIN h_w[4]
        DIRECTION INPUT ; 
        USE SIGNAL ; 
        PORT
            LAYER met2 ;
              RECT  96.76 182.015 96.9 182.5 ;
        END
    END h_w[4]
    PIN h_w[5]
        DIRECTION INPUT ; 
        USE SIGNAL ; 
        PORT
            LAYER met2 ;
              RECT  115.16 0 115.3 0.485 ;
        END
    END h_w[5]
    PIN h_w[6]
        DIRECTION INPUT ; 
        USE SIGNAL ; 
        PORT
            LAYER met1 ;
              RECT  181.905 53.82 182.5 53.96 ;
        END
    END h_w[6]
    PIN h_w[7]
        DIRECTION INPUT ; 
        USE SIGNAL ; 
        PORT
            LAYER met2 ;
              RECT  64.56 0 64.7 0.485 ;
        END
    END h_w[7]
    PIN h_w[8]
        DIRECTION INPUT ; 
        USE SIGNAL ; 
        PORT
            LAYER met1 ;
              RECT  181.905 172.82 182.5 172.96 ;
        END
    END h_w[8]
    PIN h_w[9]
        DIRECTION INPUT ; 
        USE SIGNAL ; 
        PORT
            LAYER met1 ;
              RECT  0 104.14 0.595 104.28 ;
        END
    END h_w[9]
    PIN h_wready
        DIRECTION OUTPUT ; 
        USE SIGNAL ; 
        PORT
            LAYER met1 ;
              RECT  0 74.9 0.595 75.04 ;
        END
    END h_wready
    PIN h_wvalid
        DIRECTION INPUT ; 
        USE SIGNAL ; 
        PORT
            LAYER met1 ;
              RECT  0 100.06 0.595 100.2 ;
        END
    END h_wvalid
    PIN rst_n
        DIRECTION INPUT ; 
        USE SIGNAL ; 
        PORT
            LAYER met2 ;
              RECT  153.8 182.015 153.94 182.5 ;
        END
    END rst_n
    PIN v_ar[0]
        DIRECTION OUTPUT ; 
        USE SIGNAL ; 
        PORT
            LAYER met2 ;
              RECT  139.08 0 139.22 0.485 ;
        END
    END v_ar[0]
    PIN v_ar[10]
        DIRECTION OUTPUT ; 
        USE SIGNAL ; 
        PORT
            LAYER met1 ;
              RECT  181.905 111.62 182.5 111.76 ;
        END
    END v_ar[10]
    PIN v_ar[11]
        DIRECTION OUTPUT ; 
        USE SIGNAL ; 
        PORT
            LAYER met2 ;
              RECT  180.48 182.015 180.62 182.5 ;
        END
    END v_ar[11]
    PIN v_ar[12]
        DIRECTION OUTPUT ; 
        USE SIGNAL ; 
        PORT
            LAYER met2 ;
              RECT  155.64 182.015 155.78 182.5 ;
        END
    END v_ar[12]
    PIN v_ar[13]
        DIRECTION OUTPUT ; 
        USE SIGNAL ; 
        PORT
            LAYER met1 ;
              RECT  0 157.86 0.595 158 ;
        END
    END v_ar[13]
    PIN v_ar[14]
        DIRECTION OUTPUT ; 
        USE SIGNAL ; 
        PORT
            LAYER met2 ;
              RECT  181.4 182.015 181.54 182.5 ;
        END
    END v_ar[14]
    PIN v_ar[15]
        DIRECTION OUTPUT ; 
        USE SIGNAL ; 
        PORT
            LAYER met2 ;
              RECT  26.84 182.015 26.98 182.5 ;
        END
    END v_ar[15]
    PIN v_ar[16]
        DIRECTION OUTPUT ; 
        USE SIGNAL ; 
        PORT
            LAYER met2 ;
              RECT  71.92 0 72.06 0.485 ;
        END
    END v_ar[16]
    PIN v_ar[17]
        DIRECTION OUTPUT ; 
        USE SIGNAL ; 
        PORT
            LAYER met1 ;
              RECT  0 47.02 0.595 47.16 ;
        END
    END v_ar[17]
    PIN v_ar[18]
        DIRECTION OUTPUT ; 
        USE SIGNAL ; 
        PORT
            LAYER met1 ;
              RECT  181.905 76.26 182.5 76.4 ;
        END
    END v_ar[18]
    PIN v_ar[19]
        DIRECTION OUTPUT ; 
        USE SIGNAL ; 
        PORT
            LAYER met1 ;
              RECT  181.905 117.74 182.5 117.88 ;
        END
    END v_ar[19]
    PIN v_ar[1]
        DIRECTION OUTPUT ; 
        USE SIGNAL ; 
        PORT
            LAYER met2 ;
              RECT  70.08 182.015 70.22 182.5 ;
        END
    END v_ar[1]
    PIN v_ar[20]
        DIRECTION OUTPUT ; 
        USE SIGNAL ; 
        PORT
            LAYER met2 ;
              RECT  167.6 0 167.74 0.485 ;
        END
    END v_ar[20]
    PIN v_ar[21]
        DIRECTION OUTPUT ; 
        USE SIGNAL ; 
        PORT
            LAYER met1 ;
              RECT  181.905 153.1 182.5 153.24 ;
        END
    END v_ar[21]
    PIN v_ar[22]
        DIRECTION OUTPUT ; 
        USE SIGNAL ; 
        PORT
            LAYER met1 ;
              RECT  0 60.62 0.595 60.76 ;
        END
    END v_ar[22]
    PIN v_ar[23]
        DIRECTION OUTPUT ; 
        USE SIGNAL ; 
        PORT
            LAYER met2 ;
              RECT  162.08 182.015 162.22 182.5 ;
        END
    END v_ar[23]
    PIN v_ar[24]
        DIRECTION OUTPUT ; 
        USE SIGNAL ; 
        PORT
            LAYER met1 ;
              RECT  181.905 168.74 182.5 168.88 ;
        END
    END v_ar[24]
    PIN v_ar[25]
        DIRECTION OUTPUT ; 
        USE SIGNAL ; 
        PORT
            LAYER met1 ;
              RECT  181.905 14.38 182.5 14.52 ;
        END
    END v_ar[25]
    PIN v_ar[26]
        DIRECTION OUTPUT ; 
        USE SIGNAL ; 
        PORT
            LAYER met1 ;
              RECT  0 163.98 0.595 164.12 ;
        END
    END v_ar[26]
    PIN v_ar[27]
        DIRECTION OUTPUT ; 
        USE SIGNAL ; 
        PORT
            LAYER met1 ;
              RECT  0 132.7 0.595 132.84 ;
        END
    END v_ar[27]
    PIN v_ar[28]
        DIRECTION OUTPUT ; 
        USE SIGNAL ; 
        PORT
            LAYER met1 ;
              RECT  181.905 36.14 182.5 36.28 ;
        END
    END v_ar[28]
    PIN v_ar[29]
        DIRECTION OUTPUT ; 
        USE SIGNAL ; 
        PORT
            LAYER met2 ;
              RECT  39.72 0 39.86 0.485 ;
        END
    END v_ar[29]
    PIN v_ar[2]
        DIRECTION OUTPUT ; 
        USE SIGNAL ; 
        PORT
            LAYER met2 ;
              RECT  59.04 0 59.18 0.485 ;
        END
    END v_ar[2]
    PIN v_ar[30]
        DIRECTION OUTPUT ; 
        USE SIGNAL ; 
        PORT
            LAYER met1 ;
              RECT  181.905 18.46 182.5 18.6 ;
        END
    END v_ar[30]
    PIN v_ar[31]
        DIRECTION OUTPUT ; 
        USE SIGNAL ; 
        PORT
            LAYER met1 ;
              RECT  181.905 73.54 182.5 73.68 ;
        END
    END v_ar[31]
    PIN v_ar[32]
        DIRECTION OUTPUT ; 
        USE SIGNAL ; 
        PORT
            LAYER met1 ;
              RECT  181.905 155.14 182.5 155.28 ;
        END
    END v_ar[32]
    PIN v_ar[33]
        DIRECTION OUTPUT ; 
        USE SIGNAL ; 
        PORT
            LAYER met1 ;
              RECT  0 108.9 0.595 109.04 ;
        END
    END v_ar[33]
    PIN v_ar[34]
        DIRECTION OUTPUT ; 
        USE SIGNAL ; 
        PORT
            LAYER met2 ;
              RECT  65.48 182.015 65.62 182.5 ;
        END
    END v_ar[34]
    PIN v_ar[3]
        DIRECTION OUTPUT ; 
        USE SIGNAL ; 
        PORT
            LAYER met2 ;
              RECT  32.36 182.015 32.5 182.5 ;
        END
    END v_ar[3]
    PIN v_ar[4]
        DIRECTION OUTPUT ; 
        USE SIGNAL ; 
        PORT
            LAYER met1 ;
              RECT  0 78.3 0.595 78.44 ;
        END
    END v_ar[4]
    PIN v_ar[5]
        DIRECTION OUTPUT ; 
        USE SIGNAL ; 
        PORT
            LAYER met1 ;
              RECT  181.905 170.78 182.5 170.92 ;
        END
    END v_ar[5]
    PIN v_ar[6]
        DIRECTION OUTPUT ; 
        USE SIGNAL ; 
        PORT
            LAYER met1 ;
              RECT  0 116.38 0.595 116.52 ;
        END
    END v_ar[6]
    PIN v_ar[7]
        DIRECTION OUTPUT ; 
        USE SIGNAL ; 
        PORT
            LAYER met2 ;
              RECT  19.48 182.015 19.62 182.5 ;
        END
    END v_ar[7]
    PIN v_ar[8]
        DIRECTION OUTPUT ; 
        USE SIGNAL ; 
        PORT
            LAYER met1 ;
              RECT  0 23.22 0.595 23.36 ;
        END
    END v_ar[8]
    PIN v_ar[9]
        DIRECTION OUTPUT ; 
        USE SIGNAL ; 
        PORT
            LAYER met1 ;
              RECT  181.905 151.74 182.5 151.88 ;
        END
    END v_ar[9]
    PIN v_arready
        DIRECTION INPUT ; 
        USE SIGNAL ; 
        PORT
            LAYER met2 ;
              RECT  114.24 182.015 114.38 182.5 ;
        END
    END v_arready
    PIN v_arvalid
        DIRECTION OUTPUT ; 
        USE SIGNAL ; 
        PORT
            LAYER met1 ;
              RECT  0 146.3 0.595 146.44 ;
        END
    END v_arvalid
    PIN v_aw[0]
        DIRECTION OUTPUT ; 
        USE SIGNAL ; 
        PORT
            LAYER met2 ;
              RECT  140 182.015 140.14 182.5 ;
        END
    END v_aw[0]
    PIN v_aw[10]
        DIRECTION OUTPUT ; 
        USE SIGNAL ; 
        PORT
            LAYER met2 ;
              RECT  151.04 182.015 151.18 182.5 ;
        END
    END v_aw[10]
    PIN v_aw[11]
        DIRECTION OUTPUT ; 
        USE SIGNAL ; 
        PORT
            LAYER met2 ;
              RECT  152.88 182.015 153.02 182.5 ;
        END
    END v_aw[11]
    PIN v_aw[12]
        DIRECTION OUTPUT ; 
        USE SIGNAL ; 
        PORT
            LAYER met1 ;
              RECT  0 148.34 0.595 148.48 ;
        END
    END v_aw[12]
    PIN v_aw[13]
        DIRECTION OUTPUT ; 
        USE SIGNAL ; 
        PORT
            LAYER met2 ;
              RECT  79.28 182.015 79.42 182.5 ;
        END
    END v_aw[13]
    PIN v_aw[14]
        DIRECTION OUTPUT ; 
        USE SIGNAL ; 
        PORT
            LAYER met2 ;
              RECT  9.36 0 9.5 0.485 ;
        END
    END v_aw[14]
    PIN v_aw[15]
        DIRECTION OUTPUT ; 
        USE SIGNAL ; 
        PORT
            LAYER met2 ;
              RECT  3.84 0 3.98 0.485 ;
        END
    END v_aw[15]
    PIN v_aw[16]
        DIRECTION OUTPUT ; 
        USE SIGNAL ; 
        PORT
            LAYER met1 ;
              RECT  181.905 8.26 182.5 8.4 ;
        END
    END v_aw[16]
    PIN v_aw[17]
        DIRECTION OUTPUT ; 
        USE SIGNAL ; 
        PORT
            LAYER met2 ;
              RECT  128.96 0 129.1 0.485 ;
        END
    END v_aw[17]
    PIN v_aw[18]
        DIRECTION OUTPUT ; 
        USE SIGNAL ; 
        PORT
            LAYER met1 ;
              RECT  181.905 57.9 182.5 58.04 ;
        END
    END v_aw[18]
    PIN v_aw[19]
        DIRECTION OUTPUT ; 
        USE SIGNAL ; 
        PORT
            LAYER met1 ;
              RECT  0 83.06 0.595 83.2 ;
        END
    END v_aw[19]
    PIN v_aw[1]
        DIRECTION OUTPUT ; 
        USE SIGNAL ; 
        PORT
            LAYER met1 ;
              RECT  0 110.26 0.595 110.4 ;
        END
    END v_aw[1]
    PIN v_aw[20]
        DIRECTION OUTPUT ; 
        USE SIGNAL ; 
        PORT
            LAYER met1 ;
              RECT  0 150.38 0.595 150.52 ;
        END
    END v_aw[20]
    PIN v_aw[21]
        DIRECTION OUTPUT ; 
        USE SIGNAL ; 
        PORT
            LAYER met1 ;
              RECT  0 68.78 0.595 68.92 ;
        END
    END v_aw[21]
    PIN v_aw[22]
        DIRECTION OUTPUT ; 
        USE SIGNAL ; 
        PORT
            LAYER met1 ;
              RECT  0 58.58 0.595 58.72 ;
        END
    END v_aw[22]
    PIN v_aw[23]
        DIRECTION OUTPUT ; 
        USE SIGNAL ; 
        PORT
            LAYER met2 ;
              RECT  109.64 0 109.78 0.485 ;
        END
    END v_aw[23]
    PIN v_aw[24]
        DIRECTION OUTPUT ; 
        USE SIGNAL ; 
        PORT
            LAYER met2 ;
              RECT  75.6 182.015 75.74 182.5 ;
        END
    END v_aw[24]
    PIN v_aw[25]
        DIRECTION OUTPUT ; 
        USE SIGNAL ; 
        PORT
            LAYER met1 ;
              RECT  181.905 12.34 182.5 12.48 ;
        END
    END v_aw[25]
    PIN v_aw[26]
        DIRECTION OUTPUT ; 
        USE SIGNAL ; 
        PORT
            LAYER met2 ;
              RECT  94 0 94.14 0.485 ;
        END
    END v_aw[26]
    PIN v_aw[27]
        DIRECTION OUTPUT ; 
        USE SIGNAL ; 
        PORT
            LAYER met1 ;
              RECT  0 26.62 0.595 26.76 ;
        END
    END v_aw[27]
    PIN v_aw[28]
        DIRECTION OUTPUT ; 
        USE SIGNAL ; 
        PORT
            LAYER met1 ;
              RECT  181.905 135.42 182.5 135.56 ;
        END
    END v_aw[28]
    PIN v_aw[29]
        DIRECTION OUTPUT ; 
        USE SIGNAL ; 
        PORT
            LAYER met1 ;
              RECT  0 102.1 0.595 102.24 ;
        END
    END v_aw[29]
    PIN v_aw[2]
        DIRECTION OUTPUT ; 
        USE SIGNAL ; 
        PORT
            LAYER met1 ;
              RECT  0 92.58 0.595 92.72 ;
        END
    END v_aw[2]
    PIN v_aw[30]
        DIRECTION OUTPUT ; 
        USE SIGNAL ; 
        PORT
            LAYER met1 ;
              RECT  0 112.3 0.595 112.44 ;
        END
    END v_aw[30]
    PIN v_aw[31]
        DIRECTION OUTPUT ; 
        USE SIGNAL ; 
        PORT
            LAYER met1 ;
              RECT  181.905 44.3 182.5 44.44 ;
        END
    END v_aw[31]
    PIN v_aw[32]
        DIRECTION OUTPUT ; 
        USE SIGNAL ; 
        PORT
            LAYER met1 ;
              RECT  181.905 160.58 182.5 160.72 ;
        END
    END v_aw[32]
    PIN v_aw[33]
        DIRECTION OUTPUT ; 
        USE SIGNAL ; 
        PORT
            LAYER met2 ;
              RECT  46.16 182.015 46.3 182.5 ;
        END
    END v_aw[33]
    PIN v_aw[34]
        DIRECTION OUTPUT ; 
        USE SIGNAL ; 
        PORT
            LAYER met1 ;
              RECT  181.905 137.46 182.5 137.6 ;
        END
    END v_aw[34]
    PIN v_aw[3]
        DIRECTION OUTPUT ; 
        USE SIGNAL ; 
        PORT
            LAYER met1 ;
              RECT  181.905 2.82 182.5 2.96 ;
        END
    END v_aw[3]
    PIN v_aw[4]
        DIRECTION OUTPUT ; 
        USE SIGNAL ; 
        PORT
            LAYER met1 ;
              RECT  0 80.34 0.595 80.48 ;
        END
    END v_aw[4]
    PIN v_aw[5]
        DIRECTION OUTPUT ; 
        USE SIGNAL ; 
        PORT
            LAYER met1 ;
              RECT  181.905 63.34 182.5 63.48 ;
        END
    END v_aw[5]
    PIN v_aw[6]
        DIRECTION OUTPUT ; 
        USE SIGNAL ; 
        PORT
            LAYER met2 ;
              RECT  29.6 182.015 29.74 182.5 ;
        END
    END v_aw[6]
    PIN v_aw[7]
        DIRECTION OUTPUT ; 
        USE SIGNAL ; 
        PORT
            LAYER met1 ;
              RECT  181.905 32.06 182.5 32.2 ;
        END
    END v_aw[7]
    PIN v_aw[8]
        DIRECTION OUTPUT ; 
        USE SIGNAL ; 
        PORT
            LAYER met1 ;
              RECT  0 47.7 0.595 47.84 ;
        END
    END v_aw[8]
    PIN v_aw[9]
        DIRECTION OUTPUT ; 
        USE SIGNAL ; 
        PORT
            LAYER met2 ;
              RECT  31.44 0 31.58 0.485 ;
        END
    END v_aw[9]
    PIN v_awready
        DIRECTION INPUT ; 
        USE SIGNAL ; 
        PORT
            LAYER met1 ;
              RECT  181.905 132.02 182.5 132.16 ;
        END
    END v_awready
    PIN v_awvalid
        DIRECTION OUTPUT ; 
        USE SIGNAL ; 
        PORT
            LAYER met2 ;
              RECT  136.32 0 136.46 0.485 ;
        END
    END v_awvalid
    PIN v_b[0]
        DIRECTION INPUT ; 
        USE SIGNAL ; 
        PORT
            LAYER met2 ;
              RECT  61.8 0 61.94 0.485 ;
        END
    END v_b[0]
    PIN v_b[1]
        DIRECTION INPUT ; 
        USE SIGNAL ; 
        PORT
            LAYER met1 ;
              RECT  0 155.82 0.595 155.96 ;
        END
    END v_b[1]
    PIN v_bready
        DIRECTION OUTPUT ; 
        USE SIGNAL ; 
        PORT
            LAYER met2 ;
              RECT  99.52 182.015 99.66 182.5 ;
        END
    END v_bready
    PIN v_bvalid
        DIRECTION INPUT ; 
        USE SIGNAL ; 
        PORT
            LAYER met1 ;
              RECT  181.905 176.9 182.5 177.04 ;
        END
    END v_bvalid
    PIN v_r[0]
        DIRECTION INPUT ; 
        USE SIGNAL ; 
        PORT
            LAYER met1 ;
              RECT  0 166.02 0.595 166.16 ;
        END
    END v_r[0]
    PIN v_r[10]
        DIRECTION INPUT ; 
        USE SIGNAL ; 
        PORT
            LAYER met1 ;
              RECT  0 140.18 0.595 140.32 ;
        END
    END v_r[10]
    PIN v_r[11]
        DIRECTION INPUT ; 
        USE SIGNAL ; 
        PORT
            LAYER met2 ;
              RECT  59.04 182.015 59.18 182.5 ;
        END
    END v_r[11]
    PIN v_r[12]
        DIRECTION INPUT ; 
        USE SIGNAL ; 
        PORT
            LAYER met1 ;
              RECT  0 120.46 0.595 120.6 ;
        END
    END v_r[12]
    PIN v_r[13]
        DIRECTION INPUT ; 
        USE SIGNAL ; 
        PORT
            LAYER met1 ;
              RECT  0 93.26 0.595 93.4 ;
        END
    END v_r[13]
    PIN v_r[14]
        DIRECTION INPUT ; 
        USE SIGNAL ; 
        PORT
            LAYER met1 ;
              RECT  181.905 157.18 182.5 157.32 ;
        END
    END v_r[14]
    PIN v_r[15]
        DIRECTION INPUT ; 
        USE SIGNAL ; 
        PORT
            LAYER met1 ;
              RECT  181.905 143.58 182.5 143.72 ;
        END
    END v_r[15]
    PIN v_r[16]
        DIRECTION INPUT ; 
        USE SIGNAL ; 
        PORT
            LAYER met1 ;
              RECT  181.905 32.74 182.5 32.88 ;
        END
    END v_r[16]
    PIN v_r[17]
        DIRECTION INPUT ; 
        USE SIGNAL ; 
        PORT
            LAYER met2 ;
              RECT  127.12 182.015 127.26 182.5 ;
        END
    END v_r[17]
    PIN v_r[18]
        DIRECTION INPUT ; 
        USE SIGNAL ; 
        PORT
            LAYER met1 ;
              RECT  181.905 6.22 182.5 6.36 ;
        END
    END v_r[18]
    PIN v_r[19]
        DIRECTION INPUT ; 
        USE SIGNAL ; 
        PORT
            LAYER met1 ;
              RECT  0 138.82 0.595 138.96 ;
        END
    END v_r[19]
    PIN v_r[1]
        DIRECTION INPUT ; 
        USE SIGNAL ; 
        PORT
            LAYER met2 ;
              RECT  25.92 0 26.06 0.485 ;
        END
    END v_r[1]
    PIN v_r[20]
        DIRECTION INPUT ; 
        USE SIGNAL ; 
        PORT
            LAYER met1 ;
              RECT  181.905 136.78 182.5 136.92 ;
        END
    END v_r[20]
    PIN v_r[21]
        DIRECTION INPUT ; 
        USE SIGNAL ; 
        PORT
            LAYER met2 ;
              RECT  90.32 0 90.46 0.485 ;
        END
    END v_r[21]
    PIN v_r[22]
        DIRECTION INPUT ; 
        USE SIGNAL ; 
        PORT
            LAYER met1 ;
              RECT  181.905 108.22 182.5 108.36 ;
        END
    END v_r[22]
    PIN v_r[23]
        DIRECTION INPUT ; 
        USE SIGNAL ; 
        PORT
            LAYER met2 ;
              RECT  97.68 182.015 97.82 182.5 ;
        END
    END v_r[23]
    PIN v_r[24]
        DIRECTION INPUT ; 
        USE SIGNAL ; 
        PORT
            LAYER met2 ;
              RECT  73.76 0 73.9 0.485 ;
        END
    END v_r[24]
    PIN v_r[25]
        DIRECTION INPUT ; 
        USE SIGNAL ; 
        PORT
            LAYER met1 ;
              RECT  181.905 34.78 182.5 34.92 ;
        END
    END v_r[25]
    PIN v_r[26]
        DIRECTION INPUT ; 
        USE SIGNAL ; 
        PORT
            LAYER met1 ;
              RECT  0 180.3 0.595 180.44 ;
        END
    END v_r[26]
    PIN v_r[27]
        DIRECTION INPUT ; 
        USE SIGNAL ; 
        PORT
            LAYER met1 ;
              RECT  0 90.54 0.595 90.68 ;
        END
    END v_r[27]
    PIN v_r[28]
        DIRECTION INPUT ; 
        USE SIGNAL ; 
        PORT
            LAYER met1 ;
              RECT  0 15.74 0.595 15.88 ;
        END
    END v_r[28]
    PIN v_r[29]
        DIRECTION INPUT ; 
        USE SIGNAL ; 
        PORT
            LAYER met2 ;
              RECT  49.84 0 49.98 0.485 ;
        END
    END v_r[29]
    PIN v_r[2]
        DIRECTION INPUT ; 
        USE SIGNAL ; 
        PORT
            LAYER met1 ;
              RECT  0 11.66 0.595 11.8 ;
        END
    END v_r[2]
    PIN v_r[30]
        DIRECTION INPUT ; 
        USE SIGNAL ; 
        PORT
            LAYER met2 ;
              RECT  140.92 182.015 141.06 182.5 ;
        END
    END v_r[30]
    PIN v_r[31]
        DIRECTION INPUT ; 
        USE SIGNAL ; 
        PORT
            LAYER met2 ;
              RECT  36.04 0 36.18 0.485 ;
        END
    END v_r[31]
    PIN v_r[32]
        DIRECTION INPUT ; 
        USE SIGNAL ; 
        PORT
            LAYER met2 ;
              RECT  150.12 182.015 150.26 182.5 ;
        END
    END v_r[32]
    PIN v_r[33]
        DIRECTION INPUT ; 
        USE SIGNAL ; 
        PORT
            LAYER met1 ;
              RECT  181.905 161.26 182.5 161.4 ;
        END
    END v_r[33]
    PIN v_r[3]
        DIRECTION INPUT ; 
        USE SIGNAL ; 
        PORT
            LAYER met1 ;
              RECT  0 4.86 0.595 5 ;
        END
    END v_r[3]
    PIN v_r[4]
        DIRECTION INPUT ; 
        USE SIGNAL ; 
        PORT
            LAYER met1 ;
              RECT  0 177.58 0.595 177.72 ;
        END
    END v_r[4]
    PIN v_r[5]
        DIRECTION INPUT ; 
        USE SIGNAL ; 
        PORT
            LAYER met1 ;
              RECT  181.905 131.34 182.5 131.48 ;
        END
    END v_r[5]
    PIN v_r[6]
        DIRECTION INPUT ; 
        USE SIGNAL ; 
        PORT
            LAYER met1 ;
              RECT  181.905 79.66 182.5 79.8 ;
        END
    END v_r[6]
    PIN v_r[7]
        DIRECTION INPUT ; 
        USE SIGNAL ; 
        PORT
            LAYER met1 ;
              RECT  181.905 37.5 182.5 37.64 ;
        END
    END v_r[7]
    PIN v_r[8]
        DIRECTION INPUT ; 
        USE SIGNAL ; 
        PORT
            LAYER met2 ;
              RECT  111.48 0 111.62 0.485 ;
        END
    END v_r[8]
    PIN v_r[9]
        DIRECTION INPUT ; 
        USE SIGNAL ; 
        PORT
            LAYER met2 ;
              RECT  121.6 182.015 121.74 182.5 ;
        END
    END v_r[9]
    PIN v_rready
        DIRECTION OUTPUT ; 
        USE SIGNAL ; 
        PORT
            LAYER met1 ;
              RECT  181.905 175.54 182.5 175.68 ;
        END
    END v_rready
    PIN v_rvalid
        DIRECTION INPUT ; 
        USE SIGNAL ; 
        PORT
            LAYER met1 ;
              RECT  181.905 38.18 182.5 38.32 ;
        END
    END v_rvalid
    PIN v_w[0]
        DIRECTION OUTPUT ; 
        USE SIGNAL ; 
        PORT
            LAYER met2 ;
              RECT  18.56 0 18.7 0.485 ;
        END
    END v_w[0]
    PIN v_w[10]
        DIRECTION OUTPUT ; 
        USE SIGNAL ; 
        PORT
            LAYER met1 ;
              RECT  181.905 121.82 182.5 121.96 ;
        END
    END v_w[10]
    PIN v_w[11]
        DIRECTION OUTPUT ; 
        USE SIGNAL ; 
        PORT
            LAYER met2 ;
              RECT  6.6 0 6.74 0.485 ;
        END
    END v_w[11]
    PIN v_w[12]
        DIRECTION OUTPUT ; 
        USE SIGNAL ; 
        PORT
            LAYER met1 ;
              RECT  181.905 178.94 182.5 179.08 ;
        END
    END v_w[12]
    PIN v_w[13]
        DIRECTION OUTPUT ; 
        USE SIGNAL ; 
        PORT
            LAYER met2 ;
              RECT  116.08 182.015 116.22 182.5 ;
        END
    END v_w[13]
    PIN v_w[14]
        DIRECTION OUTPUT ; 
        USE SIGNAL ; 
        PORT
            LAYER met1 ;
              RECT  181.905 47.7 182.5 47.84 ;
        END
    END v_w[14]
    PIN v_w[15]
        DIRECTION OUTPUT ; 
        USE SIGNAL ; 
        PORT
            LAYER met1 ;
              RECT  0 17.78 0.595 17.92 ;
        END
    END v_w[15]
    PIN v_w[16]
        DIRECTION OUTPUT ; 
        USE SIGNAL ; 
        PORT
            LAYER met2 ;
              RECT  149.2 0 149.34 0.485 ;
        END
    END v_w[16]
    PIN v_w[17]
        DIRECTION OUTPUT ; 
        USE SIGNAL ; 
        PORT
            LAYER met1 ;
              RECT  0 35.46 0.595 35.6 ;
        END
    END v_w[17]
    PIN v_w[18]
        DIRECTION OUTPUT ; 
        USE SIGNAL ; 
        PORT
            LAYER met2 ;
              RECT  147.36 0 147.5 0.485 ;
        END
    END v_w[18]
    PIN v_w[19]
        DIRECTION OUTPUT ; 
        USE SIGNAL ; 
        PORT
            LAYER met2 ;
              RECT  1.08 0 1.22 0.485 ;
        END
    END v_w[19]
    PIN v_w[1]
        DIRECTION OUTPUT ; 
        USE SIGNAL ; 
        PORT
            LAYER met2 ;
              RECT  174.04 0 174.18 0.485 ;
        END
    END v_w[1]
    PIN v_w[20]
        DIRECTION OUTPUT ; 
        USE SIGNAL ; 
        PORT
            LAYER met1 ;
              RECT  0 63.34 0.595 63.48 ;
        END
    END v_w[20]
    PIN v_w[21]
        DIRECTION OUTPUT ; 
        USE SIGNAL ; 
        PORT
            LAYER met1 ;
              RECT  0 127.94 0.595 128.08 ;
        END
    END v_w[21]
    PIN v_w[22]
        DIRECTION OUTPUT ; 
        USE SIGNAL ; 
        PORT
            LAYER met2 ;
              RECT  16.72 182.015 16.86 182.5 ;
        END
    END v_w[22]
    PIN v_w[23]
        DIRECTION OUTPUT ; 
        USE SIGNAL ; 
        PORT
            LAYER met1 ;
              RECT  0 41.58 0.595 41.72 ;
        END
    END v_w[23]
    PIN v_w[24]
        DIRECTION OUTPUT ; 
        USE SIGNAL ; 
        PORT
            LAYER met2 ;
              RECT  47.08 0 47.22 0.485 ;
        END
    END v_w[24]
    PIN v_w[25]
        DIRECTION OUTPUT ; 
        USE SIGNAL ; 
        PORT
            LAYER met2 ;
              RECT  17.64 0 17.78 0.485 ;
        END
    END v_w[25]
    PIN v_w[26]
        DIRECTION OUTPUT ; 
        USE SIGNAL ; 
        PORT
            LAYER met2 ;
              RECT  71 182.015 71.14 182.5 ;
        END
    END v_w[26]
    PIN v_w[27]
        DIRECTION OUTPUT ; 
        USE SIGNAL ; 
        PORT
            LAYER met2 ;
              RECT  22.24 182.015 22.38 182.5 ;
        END
    END v_w[27]
    PIN v_w[28]
        DIRECTION OUTPUT ; 
        USE SIGNAL ; 
        PORT
            LAYER met2 ;
              RECT  117.92 0 118.06 0.485 ;
        END
    END v_w[28]
    PIN v_w[29]
        DIRECTION OUTPUT ; 
        USE SIGNAL ; 
        PORT
            LAYER met2 ;
              RECT  108.72 182.015 108.86 182.5 ;
        END
    END v_w[29]
    PIN v_w[2]
        DIRECTION OUTPUT ; 
        USE SIGNAL ; 
        PORT
            LAYER met1 ;
              RECT  181.905 71.5 182.5 71.64 ;
        END
    END v_w[2]
    PIN v_w[30]
        DIRECTION OUTPUT ; 
        USE SIGNAL ; 
        PORT
            LAYER met1 ;
              RECT  0 98.02 0.595 98.16 ;
        END
    END v_w[30]
    PIN v_w[31]
        DIRECTION OUTPUT ; 
        USE SIGNAL ; 
        PORT
            LAYER met1 ;
              RECT  181.905 149.7 182.5 149.84 ;
        END
    END v_w[31]
    PIN v_w[32]
        DIRECTION OUTPUT ; 
        USE SIGNAL ; 
        PORT
            LAYER met2 ;
              RECT  48 0 48.14 0.485 ;
        END
    END v_w[32]
    PIN v_w[33]
        DIRECTION OUTPUT ; 
        USE SIGNAL ; 
        PORT
            LAYER met2 ;
              RECT  82.96 0 83.1 0.485 ;
        END
    END v_w[33]
    PIN v_w[34]
        DIRECTION OUTPUT ; 
        USE SIGNAL ; 
        PORT
            LAYER met1 ;
              RECT  0 9.62 0.595 9.76 ;
        END
    END v_w[34]
    PIN v_w[35]
        DIRECTION OUTPUT ; 
        USE SIGNAL ; 
        PORT
            LAYER met1 ;
              RECT  181.905 142.9 182.5 143.04 ;
        END
    END v_w[35]
    PIN v_w[3]
        DIRECTION OUTPUT ; 
        USE SIGNAL ; 
        PORT
            LAYER met2 ;
              RECT  130.8 0 130.94 0.485 ;
        END
    END v_w[3]
    PIN v_w[4]
        DIRECTION OUTPUT ; 
        USE SIGNAL ; 
        PORT
            LAYER met2 ;
              RECT  105.96 182.015 106.1 182.5 ;
        END
    END v_w[4]
    PIN v_w[5]
        DIRECTION OUTPUT ; 
        USE SIGNAL ; 
        PORT
            LAYER met2 ;
              RECT  103.2 182.015 103.34 182.5 ;
        END
    END v_w[5]
    PIN v_w[6]
        DIRECTION OUTPUT ; 
        USE SIGNAL ; 
        PORT
            LAYER met1 ;
              RECT  0 144.26 0.595 144.4 ;
        END
    END v_w[6]
    PIN v_w[7]
        DIRECTION OUTPUT ; 
        USE SIGNAL ; 
        PORT
            LAYER met1 ;
              RECT  0 173.5 0.595 173.64 ;
        END
    END v_w[7]
    PIN v_w[8]
        DIRECTION OUTPUT ; 
        USE SIGNAL ; 
        PORT
            LAYER met2 ;
              RECT  155.64 0 155.78 0.485 ;
        END
    END v_w[8]
    PIN v_w[9]
        DIRECTION OUTPUT ; 
        USE SIGNAL ; 
        PORT
            LAYER met1 ;
              RECT  0 33.42 0.595 33.56 ;
        END
    END v_w[9]
    PIN v_wready
        DIRECTION INPUT ; 
        USE SIGNAL ; 
        PORT
            LAYER met1 ;
              RECT  0 129.98 0.595 130.12 ;
        END
    END v_wready
    PIN v_wvalid
        DIRECTION OUTPUT ; 
        USE SIGNAL ; 
        PORT
            LAYER met1 ;
              RECT  181.905 102.1 182.5 102.24 ;
        END
    END v_wvalid
    PIN VGND
        DIRECTION INOUT ; 
        USE GROUND ; 
        PORT
            LAYER met2 ;
              RECT  22.92 10.695 24.46 11.065 ;
        END
        PORT
            LAYER met2 ;
              RECT  50.06 10.695 51.6 11.065 ;
        END
        PORT
            LAYER met2 ;
              RECT  77.2 10.695 78.74 11.065 ;
        END
        PORT
            LAYER met2 ;
              RECT  104.34 10.695 105.88 11.065 ;
        END
        PORT
            LAYER met2 ;
              RECT  131.48 10.695 133.02 11.065 ;
        END
        PORT
            LAYER met2 ;
              RECT  158.62 10.695 160.16 11.065 ;
        END
        PORT
            LAYER met3 ;
              RECT  22.9 10.715 24.48 11.045 ;
        END
        PORT
            LAYER met3 ;
              RECT  50.04 10.715 51.62 11.045 ;
        END
        PORT
            LAYER met3 ;
              RECT  77.18 10.715 78.76 11.045 ;
        END
        PORT
            LAYER met3 ;
              RECT  104.32 10.715 105.9 11.045 ;
        END
        PORT
            LAYER met3 ;
              RECT  131.46 10.715 133.04 11.045 ;
        END
        PORT
            LAYER met3 ;
              RECT  158.6 10.715 160.18 11.045 ;
        END
        PORT
            LAYER met1 ;
              RECT  10.12 10.64 172.5 11.12 ;
        END
        PORT
            LAYER met1 ;
              RECT  170.5 10.64 172.5 11.12 ;
        END
        PORT
            LAYER met1 ;
              RECT  10.12 10.64 12.12 11.12 ;
        END
        PORT
            LAYER met1 ;
              RECT  170.5 16.08 172.5 16.56 ;
        END
        PORT
            LAYER met1 ;
              RECT  10.12 16.08 12.12 16.56 ;
        END
        PORT
            LAYER met1 ;
              RECT  170.5 21.52 172.5 22 ;
        END
        PORT
            LAYER met1 ;
              RECT  10.12 21.52 12.12 22 ;
        END
        PORT
            LAYER met1 ;
              RECT  170.5 26.96 172.5 27.44 ;
        END
        PORT
            LAYER met1 ;
              RECT  10.12 26.96 12.12 27.44 ;
        END
        PORT
            LAYER met1 ;
              RECT  170.5 32.4 172.5 32.88 ;
        END
        PORT
            LAYER met1 ;
              RECT  10.12 32.4 12.12 32.88 ;
        END
        PORT
            LAYER met1 ;
              RECT  170.5 37.84 172.5 38.32 ;
        END
        PORT
            LAYER met1 ;
              RECT  10.12 37.84 12.12 38.32 ;
        END
        PORT
            LAYER met1 ;
              RECT  170.5 43.28 172.5 43.76 ;
        END
        PORT
            LAYER met1 ;
              RECT  10.12 43.28 12.12 43.76 ;
        END
        PORT
            LAYER met1 ;
              RECT  170.5 48.72 172.5 49.2 ;
        END
        PORT
            LAYER met1 ;
              RECT  10.12 48.72 12.12 49.2 ;
        END
        PORT
            LAYER met1 ;
              RECT  170.5 54.16 172.5 54.64 ;
        END
        PORT
            LAYER met1 ;
              RECT  10.12 54.16 12.12 54.64 ;
        END
        PORT
            LAYER met1 ;
              RECT  170.5 59.6 172.5 60.08 ;
        END
        PORT
            LAYER met1 ;
              RECT  10.12 59.6 12.12 60.08 ;
        END
        PORT
            LAYER met1 ;
              RECT  170.5 65.04 172.5 65.52 ;
        END
        PORT
            LAYER met1 ;
              RECT  10.12 65.04 12.12 65.52 ;
        END
        PORT
            LAYER met1 ;
              RECT  170.5 70.48 172.5 70.96 ;
        END
        PORT
            LAYER met1 ;
              RECT  10.12 70.48 12.12 70.96 ;
        END
        PORT
            LAYER met1 ;
              RECT  170.5 75.92 172.5 76.4 ;
        END
        PORT
            LAYER met1 ;
              RECT  10.12 75.92 12.12 76.4 ;
        END
        PORT
            LAYER met1 ;
              RECT  170.5 81.36 172.5 81.84 ;
        END
        PORT
            LAYER met1 ;
              RECT  10.12 81.36 12.12 81.84 ;
        END
        PORT
            LAYER met1 ;
              RECT  170.5 86.8 172.5 87.28 ;
        END
        PORT
            LAYER met1 ;
              RECT  10.12 86.8 12.12 87.28 ;
        END
        PORT
            LAYER met1 ;
              RECT  170.5 92.24 172.5 92.72 ;
        END
        PORT
            LAYER met1 ;
              RECT  10.12 92.24 12.12 92.72 ;
        END
        PORT
            LAYER met1 ;
              RECT  170.5 97.68 172.5 98.16 ;
        END
        PORT
            LAYER met1 ;
              RECT  10.12 97.68 12.12 98.16 ;
        END
        PORT
            LAYER met1 ;
              RECT  170.5 103.12 172.5 103.6 ;
        END
        PORT
            LAYER met1 ;
              RECT  10.12 103.12 12.12 103.6 ;
        END
        PORT
            LAYER met1 ;
              RECT  170.5 108.56 172.5 109.04 ;
        END
        PORT
            LAYER met1 ;
              RECT  10.12 108.56 12.12 109.04 ;
        END
        PORT
            LAYER met1 ;
              RECT  170.5 114 172.5 114.48 ;
        END
        PORT
            LAYER met1 ;
              RECT  10.12 114 12.12 114.48 ;
        END
        PORT
            LAYER met1 ;
              RECT  170.5 119.44 172.5 119.92 ;
        END
        PORT
            LAYER met1 ;
              RECT  10.12 119.44 12.12 119.92 ;
        END
        PORT
            LAYER met1 ;
              RECT  170.5 124.88 172.5 125.36 ;
        END
        PORT
            LAYER met1 ;
              RECT  10.12 124.88 12.12 125.36 ;
        END
        PORT
            LAYER met1 ;
              RECT  170.5 130.32 172.5 130.8 ;
        END
        PORT
            LAYER met1 ;
              RECT  10.12 130.32 12.12 130.8 ;
        END
        PORT
            LAYER met1 ;
              RECT  170.5 135.76 172.5 136.24 ;
        END
        PORT
            LAYER met1 ;
              RECT  10.12 135.76 12.12 136.24 ;
        END
        PORT
            LAYER met1 ;
              RECT  170.5 141.2 172.5 141.68 ;
        END
        PORT
            LAYER met1 ;
              RECT  10.12 141.2 12.12 141.68 ;
        END
        PORT
            LAYER met1 ;
              RECT  170.5 146.64 172.5 147.12 ;
        END
        PORT
            LAYER met1 ;
              RECT  10.12 146.64 12.12 147.12 ;
        END
        PORT
            LAYER met1 ;
              RECT  170.5 152.08 172.5 152.56 ;
        END
        PORT
            LAYER met1 ;
              RECT  10.12 152.08 12.12 152.56 ;
        END
        PORT
            LAYER met1 ;
              RECT  170.5 157.52 172.5 158 ;
        END
        PORT
            LAYER met1 ;
              RECT  10.12 157.52 12.12 158 ;
        END
        PORT
            LAYER met1 ;
              RECT  170.5 162.96 172.5 163.44 ;
        END
        PORT
            LAYER met1 ;
              RECT  10.12 162.96 12.12 163.44 ;
        END
        PORT
            LAYER met1 ;
              RECT  170.5 168.4 172.5 168.88 ;
        END
        PORT
            LAYER met1 ;
              RECT  10.12 168.4 12.12 168.88 ;
        END
        PORT
            LAYER met4 ;
              RECT  22.89 10.64 24.49 12.64 ;
        END
        PORT
            LAYER met4 ;
              RECT  50.03 10.64 51.63 12.64 ;
        END
        PORT
            LAYER met4 ;
              RECT  77.17 10.64 78.77 12.64 ;
        END
        PORT
            LAYER met4 ;
              RECT  104.31 10.64 105.91 12.64 ;
        END
        PORT
            LAYER met4 ;
              RECT  131.45 10.64 133.05 12.64 ;
        END
        PORT
            LAYER met4 ;
              RECT  158.59 10.64 160.19 12.64 ;
        END
    END VGND
    PIN VPWR
        DIRECTION INOUT ; 
        USE POWER ; 
        PORT
            LAYER met2 ;
              RECT  36.49 171.175 38.03 171.545 ;
        END
        PORT
            LAYER met2 ;
              RECT  63.63 171.175 65.17 171.545 ;
        END
        PORT
            LAYER met2 ;
              RECT  90.77 171.175 92.31 171.545 ;
        END
        PORT
            LAYER met2 ;
              RECT  117.91 171.175 119.45 171.545 ;
        END
        PORT
            LAYER met2 ;
              RECT  145.05 171.175 146.59 171.545 ;
        END
        PORT
            LAYER met3 ;
              RECT  36.47 171.195 38.05 171.525 ;
        END
        PORT
            LAYER met3 ;
              RECT  63.61 171.195 65.19 171.525 ;
        END
        PORT
            LAYER met3 ;
              RECT  90.75 171.195 92.33 171.525 ;
        END
        PORT
            LAYER met3 ;
              RECT  117.89 171.195 119.47 171.525 ;
        END
        PORT
            LAYER met3 ;
              RECT  145.03 171.195 146.61 171.525 ;
        END
        PORT
            LAYER met1 ;
              RECT  170.5 13.36 172.5 13.84 ;
        END
        PORT
            LAYER met1 ;
              RECT  10.12 13.36 12.12 13.84 ;
        END
        PORT
            LAYER met1 ;
              RECT  170.5 18.8 172.5 19.28 ;
        END
        PORT
            LAYER met1 ;
              RECT  10.12 18.8 12.12 19.28 ;
        END
        PORT
            LAYER met1 ;
              RECT  170.5 24.24 172.5 24.72 ;
        END
        PORT
            LAYER met1 ;
              RECT  10.12 24.24 12.12 24.72 ;
        END
        PORT
            LAYER met1 ;
              RECT  170.5 29.68 172.5 30.16 ;
        END
        PORT
            LAYER met1 ;
              RECT  10.12 29.68 12.12 30.16 ;
        END
        PORT
            LAYER met1 ;
              RECT  170.5 35.12 172.5 35.6 ;
        END
        PORT
            LAYER met1 ;
              RECT  10.12 35.12 12.12 35.6 ;
        END
        PORT
            LAYER met1 ;
              RECT  170.5 40.56 172.5 41.04 ;
        END
        PORT
            LAYER met1 ;
              RECT  10.12 40.56 12.12 41.04 ;
        END
        PORT
            LAYER met1 ;
              RECT  170.5 46 172.5 46.48 ;
        END
        PORT
            LAYER met1 ;
              RECT  10.12 46 12.12 46.48 ;
        END
        PORT
            LAYER met1 ;
              RECT  170.5 51.44 172.5 51.92 ;
        END
        PORT
            LAYER met1 ;
              RECT  10.12 51.44 12.12 51.92 ;
        END
        PORT
            LAYER met1 ;
              RECT  170.5 56.88 172.5 57.36 ;
        END
        PORT
            LAYER met1 ;
              RECT  10.12 56.88 12.12 57.36 ;
        END
        PORT
            LAYER met1 ;
              RECT  170.5 62.32 172.5 62.8 ;
        END
        PORT
            LAYER met1 ;
              RECT  10.12 62.32 12.12 62.8 ;
        END
        PORT
            LAYER met1 ;
              RECT  170.5 67.76 172.5 68.24 ;
        END
        PORT
            LAYER met1 ;
              RECT  10.12 67.76 12.12 68.24 ;
        END
        PORT
            LAYER met1 ;
              RECT  170.5 73.2 172.5 73.68 ;
        END
        PORT
            LAYER met1 ;
              RECT  10.12 73.2 12.12 73.68 ;
        END
        PORT
            LAYER met1 ;
              RECT  170.5 78.64 172.5 79.12 ;
        END
        PORT
            LAYER met1 ;
              RECT  10.12 78.64 12.12 79.12 ;
        END
        PORT
            LAYER met1 ;
              RECT  170.5 84.08 172.5 84.56 ;
        END
        PORT
            LAYER met1 ;
              RECT  10.12 84.08 12.12 84.56 ;
        END
        PORT
            LAYER met1 ;
              RECT  170.5 89.52 172.5 90 ;
        END
        PORT
            LAYER met1 ;
              RECT  10.12 89.52 12.12 90 ;
        END
        PORT
            LAYER met1 ;
              RECT  170.5 94.96 172.5 95.44 ;
        END
        PORT
            LAYER met1 ;
              RECT  10.12 94.96 12.12 95.44 ;
        END
        PORT
            LAYER met1 ;
              RECT  170.5 100.4 172.5 100.88 ;
        END
        PORT
            LAYER met1 ;
              RECT  10.12 100.4 12.12 100.88 ;
        END
        PORT
            LAYER met1 ;
              RECT  170.5 105.84 172.5 106.32 ;
        END
        PORT
            LAYER met1 ;
              RECT  10.12 105.84 12.12 106.32 ;
        END
        PORT
            LAYER met1 ;
              RECT  170.5 111.28 172.5 111.76 ;
        END
        PORT
            LAYER met1 ;
              RECT  10.12 111.28 12.12 111.76 ;
        END
        PORT
            LAYER met1 ;
              RECT  170.5 116.72 172.5 117.2 ;
        END
        PORT
            LAYER met1 ;
              RECT  10.12 116.72 12.12 117.2 ;
        END
        PORT
            LAYER met1 ;
              RECT  170.5 122.16 172.5 122.64 ;
        END
        PORT
            LAYER met1 ;
              RECT  10.12 122.16 12.12 122.64 ;
        END
        PORT
            LAYER met1 ;
              RECT  170.5 127.6 172.5 128.08 ;
        END
        PORT
            LAYER met1 ;
              RECT  10.12 127.6 12.12 128.08 ;
        END
        PORT
            LAYER met1 ;
              RECT  170.5 133.04 172.5 133.52 ;
        END
        PORT
            LAYER met1 ;
              RECT  10.12 133.04 12.12 133.52 ;
        END
        PORT
            LAYER met1 ;
              RECT  170.5 138.48 172.5 138.96 ;
        END
        PORT
            LAYER met1 ;
              RECT  10.12 138.48 12.12 138.96 ;
        END
        PORT
            LAYER met1 ;
              RECT  170.5 143.92 172.5 144.4 ;
        END
        PORT
            LAYER met1 ;
              RECT  10.12 143.92 12.12 144.4 ;
        END
        PORT
            LAYER met1 ;
              RECT  170.5 149.36 172.5 149.84 ;
        END
        PORT
            LAYER met1 ;
              RECT  10.12 149.36 12.12 149.84 ;
        END
        PORT
            LAYER met1 ;
              RECT  170.5 154.8 172.5 155.28 ;
        END
        PORT
            LAYER met1 ;
              RECT  10.12 154.8 12.12 155.28 ;
        END
        PORT
            LAYER met1 ;
              RECT  170.5 160.24 172.5 160.72 ;
        END
        PORT
            LAYER met1 ;
              RECT  10.12 160.24 12.12 160.72 ;
        END
        PORT
            LAYER met1 ;
              RECT  170.5 165.68 172.5 166.16 ;
        END
        PORT
            LAYER met1 ;
              RECT  10.12 165.68 12.12 166.16 ;
        END
        PORT
            LAYER met1 ;
              RECT  10.12 171.12 172.5 171.6 ;
        END
        PORT
            LAYER met1 ;
              RECT  170.5 171.12 172.5 171.6 ;
        END
        PORT
            LAYER met1 ;
              RECT  10.12 171.12 12.12 171.6 ;
        END
        PORT
            LAYER met4 ;
              RECT  36.46 169.6 38.06 171.6 ;
        END
        PORT
            LAYER met4 ;
              RECT  63.6 169.6 65.2 171.6 ;
        END
        PORT
            LAYER met4 ;
              RECT  90.74 169.6 92.34 171.6 ;
        END
        PORT
            LAYER met4 ;
              RECT  117.88 169.6 119.48 171.6 ;
        END
        PORT
            LAYER met4 ;
              RECT  145.02 169.6 146.62 171.6 ;
        END
    END VPWR
    OBS
      LAYER met5 ;
        RECT  0 0 182.5 182.5 ;
      LAYER met4 ;
        RECT  0 171.6 182.5 182.5 ;
        RECT  146.62 169.6 182.5 171.6 ;
        RECT  119.48 169.6 145.02 171.6 ;
        RECT  92.34 169.6 117.88 171.6 ;
        RECT  65.2 169.6 90.74 171.6 ;
        RECT  38.06 169.6 63.6 171.6 ;
        RECT  0 169.6 36.46 171.6 ;
        RECT  0 12.64 182.5 169.6 ;
        RECT  160.19 10.64 182.5 12.64 ;
        RECT  133.05 10.64 158.59 12.64 ;
        RECT  105.91 10.64 131.45 12.64 ;
        RECT  78.77 10.64 104.31 12.64 ;
        RECT  51.63 10.64 77.17 12.64 ;
        RECT  24.49 10.64 50.03 12.64 ;
        RECT  0 10.64 22.89 12.64 ;
        RECT  0 0 182.5 10.64 ;
      LAYER met3 ;
        RECT  0 171.525 182.5 182.5 ;
        RECT  146.61 171.195 182.5 171.525 ;
        RECT  119.47 171.195 145.03 171.525 ;
        RECT  92.33 171.195 117.89 171.525 ;
        RECT  65.19 171.195 90.75 171.525 ;
        RECT  38.05 171.195 63.61 171.525 ;
        RECT  0 171.195 36.47 171.525 ;
        RECT  0 11.045 182.5 171.195 ;
        RECT  160.18 10.715 182.5 11.045 ;
        RECT  133.04 10.715 158.6 11.045 ;
        RECT  105.9 10.715 131.46 11.045 ;
        RECT  78.76 10.715 104.32 11.045 ;
        RECT  51.62 10.715 77.18 11.045 ;
        RECT  24.48 10.715 50.04 11.045 ;
        RECT  0 10.715 22.9 11.045 ;
        RECT  0 0 182.5 10.715 ;
      LAYER met2 ;
        RECT  181.54 182.015 182.5 182.5 ;
        RECT  180.62 182.015 181.4 182.5 ;
        RECT  178.78 182.015 180.48 182.5 ;
        RECT  177.86 182.015 178.64 182.5 ;
        RECT  176.02 182.015 177.72 182.5 ;
        RECT  175.1 182.015 175.88 182.5 ;
        RECT  173.26 182.015 174.96 182.5 ;
        RECT  172.34 182.015 173.12 182.5 ;
        RECT  170.5 182.015 172.2 182.5 ;
        RECT  169.58 182.015 170.36 182.5 ;
        RECT  167.74 182.015 169.44 182.5 ;
        RECT  166.82 182.015 167.6 182.5 ;
        RECT  164.98 182.015 166.68 182.5 ;
        RECT  164.06 182.015 164.84 182.5 ;
        RECT  162.22 182.015 163.92 182.5 ;
        RECT  161.3 182.015 162.08 182.5 ;
        RECT  159.46 182.015 161.16 182.5 ;
        RECT  158.54 182.015 159.32 182.5 ;
        RECT  156.7 182.015 158.4 182.5 ;
        RECT  155.78 182.015 156.56 182.5 ;
        RECT  153.94 182.015 155.64 182.5 ;
        RECT  153.02 182.015 153.8 182.5 ;
        RECT  151.18 182.015 152.88 182.5 ;
        RECT  150.26 182.015 151.04 182.5 ;
        RECT  148.42 182.015 150.12 182.5 ;
        RECT  146.58 182.015 148.28 182.5 ;
        RECT  145.66 182.015 146.44 182.5 ;
        RECT  143.82 182.015 145.52 182.5 ;
        RECT  142.9 182.015 143.68 182.5 ;
        RECT  141.06 182.015 142.76 182.5 ;
        RECT  140.14 182.015 140.92 182.5 ;
        RECT  138.3 182.015 140 182.5 ;
        RECT  137.38 182.015 138.16 182.5 ;
        RECT  135.54 182.015 137.24 182.5 ;
        RECT  134.62 182.015 135.4 182.5 ;
        RECT  132.78 182.015 134.48 182.5 ;
        RECT  131.86 182.015 132.64 182.5 ;
        RECT  130.02 182.015 131.72 182.5 ;
        RECT  129.1 182.015 129.88 182.5 ;
        RECT  127.26 182.015 128.96 182.5 ;
        RECT  126.34 182.015 127.12 182.5 ;
        RECT  124.5 182.015 126.2 182.5 ;
        RECT  123.58 182.015 124.36 182.5 ;
        RECT  121.74 182.015 123.44 182.5 ;
        RECT  120.82 182.015 121.6 182.5 ;
        RECT  118.98 182.015 120.68 182.5 ;
        RECT  118.06 182.015 118.84 182.5 ;
        RECT  116.22 182.015 117.92 182.5 ;
        RECT  114.38 182.015 116.08 182.5 ;
        RECT  113.46 182.015 114.24 182.5 ;
        RECT  111.62 182.015 113.32 182.5 ;
        RECT  110.7 182.015 111.48 182.5 ;
        RECT  108.86 182.015 110.56 182.5 ;
        RECT  107.94 182.015 108.72 182.5 ;
        RECT  106.1 182.015 107.8 182.5 ;
        RECT  105.18 182.015 105.96 182.5 ;
        RECT  103.34 182.015 105.04 182.5 ;
        RECT  102.42 182.015 103.2 182.5 ;
        RECT  100.58 182.015 102.28 182.5 ;
        RECT  99.66 182.015 100.44 182.5 ;
        RECT  97.82 182.015 99.52 182.5 ;
        RECT  96.9 182.015 97.68 182.5 ;
        RECT  95.06 182.015 96.76 182.5 ;
        RECT  94.14 182.015 94.92 182.5 ;
        RECT  92.3 182.015 94 182.5 ;
        RECT  91.38 182.015 92.16 182.5 ;
        RECT  89.54 182.015 91.24 182.5 ;
        RECT  88.62 182.015 89.4 182.5 ;
        RECT  86.78 182.015 88.48 182.5 ;
        RECT  85.86 182.015 86.64 182.5 ;
        RECT  84.02 182.015 85.72 182.5 ;
        RECT  82.18 182.015 83.88 182.5 ;
        RECT  81.26 182.015 82.04 182.5 ;
        RECT  79.42 182.015 81.12 182.5 ;
        RECT  78.5 182.015 79.28 182.5 ;
        RECT  76.66 182.015 78.36 182.5 ;
        RECT  75.74 182.015 76.52 182.5 ;
        RECT  73.9 182.015 75.6 182.5 ;
        RECT  72.98 182.015 73.76 182.5 ;
        RECT  71.14 182.015 72.84 182.5 ;
        RECT  70.22 182.015 71 182.5 ;
        RECT  68.38 182.015 70.08 182.5 ;
        RECT  67.46 182.015 68.24 182.5 ;
        RECT  65.62 182.015 67.32 182.5 ;
        RECT  64.7 182.015 65.48 182.5 ;
        RECT  62.86 182.015 64.56 182.5 ;
        RECT  61.94 182.015 62.72 182.5 ;
        RECT  60.1 182.015 61.8 182.5 ;
        RECT  59.18 182.015 59.96 182.5 ;
        RECT  57.34 182.015 59.04 182.5 ;
        RECT  56.42 182.015 57.2 182.5 ;
        RECT  54.58 182.015 56.28 182.5 ;
        RECT  53.66 182.015 54.44 182.5 ;
        RECT  51.82 182.015 53.52 182.5 ;
        RECT  49.98 182.015 51.68 182.5 ;
        RECT  49.06 182.015 49.84 182.5 ;
        RECT  47.22 182.015 48.92 182.5 ;
        RECT  46.3 182.015 47.08 182.5 ;
        RECT  44.46 182.015 46.16 182.5 ;
        RECT  43.54 182.015 44.32 182.5 ;
        RECT  41.7 182.015 43.4 182.5 ;
        RECT  40.78 182.015 41.56 182.5 ;
        RECT  38.94 182.015 40.64 182.5 ;
        RECT  38.02 182.015 38.8 182.5 ;
        RECT  36.18 182.015 37.88 182.5 ;
        RECT  35.26 182.015 36.04 182.5 ;
        RECT  33.42 182.015 35.12 182.5 ;
        RECT  32.5 182.015 33.28 182.5 ;
        RECT  30.66 182.015 32.36 182.5 ;
        RECT  29.74 182.015 30.52 182.5 ;
        RECT  27.9 182.015 29.6 182.5 ;
        RECT  26.98 182.015 27.76 182.5 ;
        RECT  25.14 182.015 26.84 182.5 ;
        RECT  24.22 182.015 25 182.5 ;
        RECT  22.38 182.015 24.08 182.5 ;
        RECT  21.46 182.015 22.24 182.5 ;
        RECT  19.62 182.015 21.32 182.5 ;
        RECT  18.7 182.015 19.48 182.5 ;
        RECT  16.86 182.015 18.56 182.5 ;
        RECT  15.02 182.015 16.72 182.5 ;
        RECT  14.1 182.015 14.88 182.5 ;
        RECT  12.26 182.015 13.96 182.5 ;
        RECT  11.34 182.015 12.12 182.5 ;
        RECT  9.5 182.015 11.2 182.5 ;
        RECT  8.58 182.015 9.36 182.5 ;
        RECT  6.74 182.015 8.44 182.5 ;
        RECT  5.82 182.015 6.6 182.5 ;
        RECT  3.98 182.015 5.68 182.5 ;
        RECT  3.06 182.015 3.84 182.5 ;
        RECT  1.22 182.015 2.92 182.5 ;
        RECT  0 182.015 1.08 182.5 ;
        RECT  0 171.545 182.5 182.015 ;
        RECT  146.59 171.175 182.5 171.545 ;
        RECT  119.45 171.175 145.05 171.545 ;
        RECT  92.31 171.175 117.91 171.545 ;
        RECT  65.17 171.175 90.77 171.545 ;
        RECT  38.03 171.175 63.63 171.545 ;
        RECT  0 171.175 36.49 171.545 ;
        RECT  0 11.065 182.5 171.175 ;
        RECT  160.16 10.695 182.5 11.065 ;
        RECT  133.02 10.695 158.62 11.065 ;
        RECT  105.88 10.695 131.48 11.065 ;
        RECT  78.74 10.695 104.34 11.065 ;
        RECT  51.6 10.695 77.2 11.065 ;
        RECT  24.46 10.695 50.06 11.065 ;
        RECT  0 10.695 22.92 11.065 ;
        RECT  0 0.485 182.5 10.695 ;
        RECT  181.54 0 182.5 0.485 ;
        RECT  179.7 0 181.4 0.485 ;
        RECT  178.78 0 179.56 0.485 ;
        RECT  176.94 0 178.64 0.485 ;
        RECT  176.02 0 176.8 0.485 ;
        RECT  174.18 0 175.88 0.485 ;
        RECT  173.26 0 174.04 0.485 ;
        RECT  171.42 0 173.12 0.485 ;
        RECT  170.5 0 171.28 0.485 ;
        RECT  168.66 0 170.36 0.485 ;
        RECT  167.74 0 168.52 0.485 ;
        RECT  165.9 0 167.6 0.485 ;
        RECT  164.06 0 165.76 0.485 ;
        RECT  163.14 0 163.92 0.485 ;
        RECT  161.3 0 163 0.485 ;
        RECT  160.38 0 161.16 0.485 ;
        RECT  158.54 0 160.24 0.485 ;
        RECT  157.62 0 158.4 0.485 ;
        RECT  155.78 0 157.48 0.485 ;
        RECT  154.86 0 155.64 0.485 ;
        RECT  153.02 0 154.72 0.485 ;
        RECT  152.1 0 152.88 0.485 ;
        RECT  150.26 0 151.96 0.485 ;
        RECT  149.34 0 150.12 0.485 ;
        RECT  147.5 0 149.2 0.485 ;
        RECT  146.58 0 147.36 0.485 ;
        RECT  144.74 0 146.44 0.485 ;
        RECT  143.82 0 144.6 0.485 ;
        RECT  141.98 0 143.68 0.485 ;
        RECT  141.06 0 141.84 0.485 ;
        RECT  139.22 0 140.92 0.485 ;
        RECT  138.3 0 139.08 0.485 ;
        RECT  136.46 0 138.16 0.485 ;
        RECT  135.54 0 136.32 0.485 ;
        RECT  133.7 0 135.4 0.485 ;
        RECT  132.78 0 133.56 0.485 ;
        RECT  130.94 0 132.64 0.485 ;
        RECT  129.1 0 130.8 0.485 ;
        RECT  128.18 0 128.96 0.485 ;
        RECT  126.34 0 128.04 0.485 ;
        RECT  125.42 0 126.2 0.485 ;
        RECT  123.58 0 125.28 0.485 ;
        RECT  122.66 0 123.44 0.485 ;
        RECT  120.82 0 122.52 0.485 ;
        RECT  119.9 0 120.68 0.485 ;
        RECT  118.06 0 119.76 0.485 ;
        RECT  117.14 0 117.92 0.485 ;
        RECT  115.3 0 117 0.485 ;
        RECT  114.38 0 115.16 0.485 ;
        RECT  112.54 0 114.24 0.485 ;
        RECT  111.62 0 112.4 0.485 ;
        RECT  109.78 0 111.48 0.485 ;
        RECT  108.86 0 109.64 0.485 ;
        RECT  107.02 0 108.72 0.485 ;
        RECT  106.1 0 106.88 0.485 ;
        RECT  104.26 0 105.96 0.485 ;
        RECT  103.34 0 104.12 0.485 ;
        RECT  101.5 0 103.2 0.485 ;
        RECT  100.58 0 101.36 0.485 ;
        RECT  98.74 0 100.44 0.485 ;
        RECT  96.9 0 98.6 0.485 ;
        RECT  95.98 0 96.76 0.485 ;
        RECT  94.14 0 95.84 0.485 ;
        RECT  93.22 0 94 0.485 ;
        RECT  91.38 0 93.08 0.485 ;
        RECT  90.46 0 91.24 0.485 ;
        RECT  88.62 0 90.32 0.485 ;
        RECT  87.7 0 88.48 0.485 ;
        RECT  85.86 0 87.56 0.485 ;
        RECT  84.94 0 85.72 0.485 ;
        RECT  83.1 0 84.8 0.485 ;
        RECT  82.18 0 82.96 0.485 ;
        RECT  80.34 0 82.04 0.485 ;
        RECT  79.42 0 80.2 0.485 ;
        RECT  77.58 0 79.28 0.485 ;
        RECT  76.66 0 77.44 0.485 ;
        RECT  74.82 0 76.52 0.485 ;
        RECT  73.9 0 74.68 0.485 ;
        RECT  72.06 0 73.76 0.485 ;
        RECT  71.14 0 71.92 0.485 ;
        RECT  69.3 0 71 0.485 ;
        RECT  68.38 0 69.16 0.485 ;
        RECT  66.54 0 68.24 0.485 ;
        RECT  64.7 0 66.4 0.485 ;
        RECT  63.78 0 64.56 0.485 ;
        RECT  61.94 0 63.64 0.485 ;
        RECT  61.02 0 61.8 0.485 ;
        RECT  59.18 0 60.88 0.485 ;
        RECT  58.26 0 59.04 0.485 ;
        RECT  56.42 0 58.12 0.485 ;
        RECT  55.5 0 56.28 0.485 ;
        RECT  53.66 0 55.36 0.485 ;
        RECT  52.74 0 53.52 0.485 ;
        RECT  50.9 0 52.6 0.485 ;
        RECT  49.98 0 50.76 0.485 ;
        RECT  48.14 0 49.84 0.485 ;
        RECT  47.22 0 48 0.485 ;
        RECT  45.38 0 47.08 0.485 ;
        RECT  44.46 0 45.24 0.485 ;
        RECT  42.62 0 44.32 0.485 ;
        RECT  41.7 0 42.48 0.485 ;
        RECT  39.86 0 41.56 0.485 ;
        RECT  38.94 0 39.72 0.485 ;
        RECT  37.1 0 38.8 0.485 ;
        RECT  36.18 0 36.96 0.485 ;
        RECT  34.34 0 36.04 0.485 ;
        RECT  32.5 0 34.2 0.485 ;
        RECT  31.58 0 32.36 0.485 ;
        RECT  29.74 0 31.44 0.485 ;
        RECT  28.82 0 29.6 0.485 ;
        RECT  26.98 0 28.68 0.485 ;
        RECT  26.06 0 26.84 0.485 ;
        RECT  24.22 0 25.92 0.485 ;
        RECT  23.3 0 24.08 0.485 ;
        RECT  21.46 0 23.16 0.485 ;
        RECT  20.54 0 21.32 0.485 ;
        RECT  18.7 0 20.4 0.485 ;
        RECT  17.78 0 18.56 0.485 ;
        RECT  15.94 0 17.64 0.485 ;
        RECT  15.02 0 15.8 0.485 ;
        RECT  13.18 0 14.88 0.485 ;
        RECT  12.26 0 13.04 0.485 ;
        RECT  10.42 0 12.12 0.485 ;
        RECT  9.5 0 10.28 0.485 ;
        RECT  7.66 0 9.36 0.485 ;
        RECT  6.74 0 7.52 0.485 ;
        RECT  4.9 0 6.6 0.485 ;
        RECT  3.98 0 4.76 0.485 ;
        RECT  2.14 0 3.84 0.485 ;
        RECT  1.22 0 2 0.485 ;
        RECT  0 0 1.08 0.485 ;
      LAYER met1 ;
        RECT  0 181.8 182.5 182.5 ;
        RECT  0.595 181.66 182.5 181.8 ;
        RECT  0 181.12 182.5 181.66 ;
        RECT  0 180.98 181.905 181.12 ;
        RECT  0 180.44 182.5 180.98 ;
        RECT  0.595 180.3 182.5 180.44 ;
        RECT  0 179.76 182.5 180.3 ;
        RECT  0.595 179.62 181.905 179.76 ;
        RECT  0 179.08 182.5 179.62 ;
        RECT  0 178.94 181.905 179.08 ;
        RECT  0 178.4 182.5 178.94 ;
        RECT  0.595 178.26 182.5 178.4 ;
        RECT  0 177.72 182.5 178.26 ;
        RECT  0.595 177.58 181.905 177.72 ;
        RECT  0 177.04 182.5 177.58 ;
        RECT  0 176.9 181.905 177.04 ;
        RECT  0 176.36 182.5 176.9 ;
        RECT  0.595 176.22 182.5 176.36 ;
        RECT  0 175.68 182.5 176.22 ;
        RECT  0.595 175.54 181.905 175.68 ;
        RECT  0 175 182.5 175.54 ;
        RECT  0 174.86 181.905 175 ;
        RECT  0 174.32 182.5 174.86 ;
        RECT  0.595 174.18 182.5 174.32 ;
        RECT  0 173.64 182.5 174.18 ;
        RECT  0.595 173.5 181.905 173.64 ;
        RECT  0 172.96 182.5 173.5 ;
        RECT  0 172.82 181.905 172.96 ;
        RECT  0 172.28 182.5 172.82 ;
        RECT  0.595 172.14 182.5 172.28 ;
        RECT  0 171.6 182.5 172.14 ;
        RECT  172.5 171.46 181.905 171.6 ;
        RECT  0.595 171.46 10.12 171.6 ;
        RECT  172.5 171.12 182.5 171.46 ;
        RECT  0 171.12 10.12 171.46 ;
        RECT  0 170.92 182.5 171.12 ;
        RECT  0 170.78 181.905 170.92 ;
        RECT  0 170.24 182.5 170.78 ;
        RECT  0.595 170.1 182.5 170.24 ;
        RECT  0 169.56 182.5 170.1 ;
        RECT  0 169.42 181.905 169.56 ;
        RECT  0 168.88 182.5 169.42 ;
        RECT  172.5 168.74 181.905 168.88 ;
        RECT  12.12 168.74 170.5 168.88 ;
        RECT  0.595 168.74 10.12 168.88 ;
        RECT  172.5 168.4 182.5 168.74 ;
        RECT  12.12 168.4 170.5 168.74 ;
        RECT  0 168.4 10.12 168.74 ;
        RECT  0 168.2 182.5 168.4 ;
        RECT  0.595 168.06 182.5 168.2 ;
        RECT  0 167.52 182.5 168.06 ;
        RECT  0 167.38 181.905 167.52 ;
        RECT  0 166.84 182.5 167.38 ;
        RECT  0.595 166.7 181.905 166.84 ;
        RECT  0 166.16 182.5 166.7 ;
        RECT  172.5 166.02 182.5 166.16 ;
        RECT  12.12 166.02 170.5 166.16 ;
        RECT  0.595 166.02 10.12 166.16 ;
        RECT  172.5 165.68 182.5 166.02 ;
        RECT  12.12 165.68 170.5 166.02 ;
        RECT  0 165.68 10.12 166.02 ;
        RECT  0 165.48 182.5 165.68 ;
        RECT  0 165.34 181.905 165.48 ;
        RECT  0 164.8 182.5 165.34 ;
        RECT  0.595 164.66 181.905 164.8 ;
        RECT  0 164.12 182.5 164.66 ;
        RECT  0.595 163.98 182.5 164.12 ;
        RECT  0 163.44 182.5 163.98 ;
        RECT  172.5 163.3 181.905 163.44 ;
        RECT  12.12 163.3 170.5 163.44 ;
        RECT  0 163.3 10.12 163.44 ;
        RECT  172.5 162.96 182.5 163.3 ;
        RECT  12.12 162.96 170.5 163.3 ;
        RECT  0 162.96 10.12 163.3 ;
        RECT  0 162.76 182.5 162.96 ;
        RECT  0.595 162.62 181.905 162.76 ;
        RECT  0 162.08 182.5 162.62 ;
        RECT  0.595 161.94 182.5 162.08 ;
        RECT  0 161.4 182.5 161.94 ;
        RECT  0 161.26 181.905 161.4 ;
        RECT  0 160.72 182.5 161.26 ;
        RECT  172.5 160.58 181.905 160.72 ;
        RECT  12.12 160.58 170.5 160.72 ;
        RECT  0.595 160.58 10.12 160.72 ;
        RECT  172.5 160.24 182.5 160.58 ;
        RECT  12.12 160.24 170.5 160.58 ;
        RECT  0 160.24 10.12 160.58 ;
        RECT  0 160.04 182.5 160.24 ;
        RECT  0.595 159.9 182.5 160.04 ;
        RECT  0 159.36 182.5 159.9 ;
        RECT  0 159.22 181.905 159.36 ;
        RECT  0 158.68 182.5 159.22 ;
        RECT  0.595 158.54 181.905 158.68 ;
        RECT  0 158 182.5 158.54 ;
        RECT  172.5 157.86 182.5 158 ;
        RECT  12.12 157.86 170.5 158 ;
        RECT  0.595 157.86 10.12 158 ;
        RECT  172.5 157.52 182.5 157.86 ;
        RECT  12.12 157.52 170.5 157.86 ;
        RECT  0 157.52 10.12 157.86 ;
        RECT  0 157.32 182.5 157.52 ;
        RECT  0 157.18 181.905 157.32 ;
        RECT  0 156.64 182.5 157.18 ;
        RECT  0.595 156.5 182.5 156.64 ;
        RECT  0 155.96 182.5 156.5 ;
        RECT  0.595 155.82 181.905 155.96 ;
        RECT  0 155.28 182.5 155.82 ;
        RECT  172.5 155.14 181.905 155.28 ;
        RECT  12.12 155.14 170.5 155.28 ;
        RECT  0 155.14 10.12 155.28 ;
        RECT  172.5 154.8 182.5 155.14 ;
        RECT  12.12 154.8 170.5 155.14 ;
        RECT  0 154.8 10.12 155.14 ;
        RECT  0 154.6 182.5 154.8 ;
        RECT  0.595 154.46 182.5 154.6 ;
        RECT  0 153.92 182.5 154.46 ;
        RECT  0.595 153.78 181.905 153.92 ;
        RECT  0 153.24 182.5 153.78 ;
        RECT  0 153.1 181.905 153.24 ;
        RECT  0 152.56 182.5 153.1 ;
        RECT  172.5 152.42 182.5 152.56 ;
        RECT  12.12 152.42 170.5 152.56 ;
        RECT  0.595 152.42 10.12 152.56 ;
        RECT  172.5 152.08 182.5 152.42 ;
        RECT  12.12 152.08 170.5 152.42 ;
        RECT  0 152.08 10.12 152.42 ;
        RECT  0 151.88 182.5 152.08 ;
        RECT  0.595 151.74 181.905 151.88 ;
        RECT  0 151.2 182.5 151.74 ;
        RECT  0 151.06 181.905 151.2 ;
        RECT  0 150.52 182.5 151.06 ;
        RECT  0.595 150.38 182.5 150.52 ;
        RECT  0 149.84 182.5 150.38 ;
        RECT  172.5 149.7 181.905 149.84 ;
        RECT  12.12 149.7 170.5 149.84 ;
        RECT  0.595 149.7 10.12 149.84 ;
        RECT  172.5 149.36 182.5 149.7 ;
        RECT  12.12 149.36 170.5 149.7 ;
        RECT  0 149.36 10.12 149.7 ;
        RECT  0 149.16 182.5 149.36 ;
        RECT  0 149.02 181.905 149.16 ;
        RECT  0 148.48 182.5 149.02 ;
        RECT  0.595 148.34 182.5 148.48 ;
        RECT  0 147.8 182.5 148.34 ;
        RECT  0.595 147.66 181.905 147.8 ;
        RECT  0 147.12 182.5 147.66 ;
        RECT  172.5 146.98 181.905 147.12 ;
        RECT  12.12 146.98 170.5 147.12 ;
        RECT  0 146.98 10.12 147.12 ;
        RECT  172.5 146.64 182.5 146.98 ;
        RECT  12.12 146.64 170.5 146.98 ;
        RECT  0 146.64 10.12 146.98 ;
        RECT  0 146.44 182.5 146.64 ;
        RECT  0.595 146.3 182.5 146.44 ;
        RECT  0 145.76 182.5 146.3 ;
        RECT  0 145.62 181.905 145.76 ;
        RECT  0 145.08 182.5 145.62 ;
        RECT  0.595 144.94 181.905 145.08 ;
        RECT  0 144.4 182.5 144.94 ;
        RECT  172.5 144.26 182.5 144.4 ;
        RECT  12.12 144.26 170.5 144.4 ;
        RECT  0.595 144.26 10.12 144.4 ;
        RECT  172.5 143.92 182.5 144.26 ;
        RECT  12.12 143.92 170.5 144.26 ;
        RECT  0 143.92 10.12 144.26 ;
        RECT  0 143.72 182.5 143.92 ;
        RECT  0 143.58 181.905 143.72 ;
        RECT  0 143.04 182.5 143.58 ;
        RECT  0.595 142.9 181.905 143.04 ;
        RECT  0 142.36 182.5 142.9 ;
        RECT  0.595 142.22 182.5 142.36 ;
        RECT  0 141.68 182.5 142.22 ;
        RECT  172.5 141.54 181.905 141.68 ;
        RECT  12.12 141.54 170.5 141.68 ;
        RECT  0 141.54 10.12 141.68 ;
        RECT  172.5 141.2 182.5 141.54 ;
        RECT  12.12 141.2 170.5 141.54 ;
        RECT  0 141.2 10.12 141.54 ;
        RECT  0 141 182.5 141.2 ;
        RECT  0.595 140.86 181.905 141 ;
        RECT  0 140.32 182.5 140.86 ;
        RECT  0.595 140.18 182.5 140.32 ;
        RECT  0 139.64 182.5 140.18 ;
        RECT  0 139.5 181.905 139.64 ;
        RECT  0 138.96 182.5 139.5 ;
        RECT  172.5 138.82 181.905 138.96 ;
        RECT  12.12 138.82 170.5 138.96 ;
        RECT  0.595 138.82 10.12 138.96 ;
        RECT  172.5 138.48 182.5 138.82 ;
        RECT  12.12 138.48 170.5 138.82 ;
        RECT  0 138.48 10.12 138.82 ;
        RECT  0 138.28 182.5 138.48 ;
        RECT  0.595 138.14 182.5 138.28 ;
        RECT  0 137.6 182.5 138.14 ;
        RECT  0 137.46 181.905 137.6 ;
        RECT  0 136.92 182.5 137.46 ;
        RECT  0.595 136.78 181.905 136.92 ;
        RECT  0 136.24 182.5 136.78 ;
        RECT  172.5 136.1 182.5 136.24 ;
        RECT  12.12 136.1 170.5 136.24 ;
        RECT  0.595 136.1 10.12 136.24 ;
        RECT  172.5 135.76 182.5 136.1 ;
        RECT  12.12 135.76 170.5 136.1 ;
        RECT  0 135.76 10.12 136.1 ;
        RECT  0 135.56 182.5 135.76 ;
        RECT  0 135.42 181.905 135.56 ;
        RECT  0 134.88 182.5 135.42 ;
        RECT  0.595 134.74 181.905 134.88 ;
        RECT  0 134.2 182.5 134.74 ;
        RECT  0.595 134.06 182.5 134.2 ;
        RECT  0 133.52 182.5 134.06 ;
        RECT  172.5 133.38 181.905 133.52 ;
        RECT  12.12 133.38 170.5 133.52 ;
        RECT  0 133.38 10.12 133.52 ;
        RECT  172.5 133.04 182.5 133.38 ;
        RECT  12.12 133.04 170.5 133.38 ;
        RECT  0 133.04 10.12 133.38 ;
        RECT  0 132.84 182.5 133.04 ;
        RECT  0.595 132.7 182.5 132.84 ;
        RECT  0 132.16 182.5 132.7 ;
        RECT  0.595 132.02 181.905 132.16 ;
        RECT  0 131.48 182.5 132.02 ;
        RECT  0 131.34 181.905 131.48 ;
        RECT  0 130.8 182.5 131.34 ;
        RECT  172.5 130.66 182.5 130.8 ;
        RECT  12.12 130.66 170.5 130.8 ;
        RECT  0.595 130.66 10.12 130.8 ;
        RECT  172.5 130.32 182.5 130.66 ;
        RECT  12.12 130.32 170.5 130.66 ;
        RECT  0 130.32 10.12 130.66 ;
        RECT  0 130.12 182.5 130.32 ;
        RECT  0.595 129.98 181.905 130.12 ;
        RECT  0 129.44 182.5 129.98 ;
        RECT  0 129.3 181.905 129.44 ;
        RECT  0 128.76 182.5 129.3 ;
        RECT  0.595 128.62 182.5 128.76 ;
        RECT  0 128.08 182.5 128.62 ;
        RECT  172.5 127.94 181.905 128.08 ;
        RECT  12.12 127.94 170.5 128.08 ;
        RECT  0.595 127.94 10.12 128.08 ;
        RECT  172.5 127.6 182.5 127.94 ;
        RECT  12.12 127.6 170.5 127.94 ;
        RECT  0 127.6 10.12 127.94 ;
        RECT  0 127.4 182.5 127.6 ;
        RECT  0 127.26 181.905 127.4 ;
        RECT  0 126.72 182.5 127.26 ;
        RECT  0.595 126.58 182.5 126.72 ;
        RECT  0 126.04 182.5 126.58 ;
        RECT  0.595 125.9 181.905 126.04 ;
        RECT  0 125.36 182.5 125.9 ;
        RECT  172.5 125.22 181.905 125.36 ;
        RECT  12.12 125.22 170.5 125.36 ;
        RECT  0 125.22 10.12 125.36 ;
        RECT  172.5 124.88 182.5 125.22 ;
        RECT  12.12 124.88 170.5 125.22 ;
        RECT  0 124.88 10.12 125.22 ;
        RECT  0 124.68 182.5 124.88 ;
        RECT  0.595 124.54 182.5 124.68 ;
        RECT  0 124 182.5 124.54 ;
        RECT  0.595 123.86 181.905 124 ;
        RECT  0 123.32 182.5 123.86 ;
        RECT  0 123.18 181.905 123.32 ;
        RECT  0 122.64 182.5 123.18 ;
        RECT  172.5 122.5 182.5 122.64 ;
        RECT  12.12 122.5 170.5 122.64 ;
        RECT  0.595 122.5 10.12 122.64 ;
        RECT  172.5 122.16 182.5 122.5 ;
        RECT  12.12 122.16 170.5 122.5 ;
        RECT  0 122.16 10.12 122.5 ;
        RECT  0 121.96 182.5 122.16 ;
        RECT  0 121.82 181.905 121.96 ;
        RECT  0 121.28 182.5 121.82 ;
        RECT  0.595 121.14 181.905 121.28 ;
        RECT  0 120.6 182.5 121.14 ;
        RECT  0.595 120.46 182.5 120.6 ;
        RECT  0 119.92 182.5 120.46 ;
        RECT  172.5 119.78 181.905 119.92 ;
        RECT  12.12 119.78 170.5 119.92 ;
        RECT  0 119.78 10.12 119.92 ;
        RECT  172.5 119.44 182.5 119.78 ;
        RECT  12.12 119.44 170.5 119.78 ;
        RECT  0 119.44 10.12 119.78 ;
        RECT  0 119.24 182.5 119.44 ;
        RECT  0.595 119.1 181.905 119.24 ;
        RECT  0 118.56 182.5 119.1 ;
        RECT  0.595 118.42 182.5 118.56 ;
        RECT  0 117.88 182.5 118.42 ;
        RECT  0 117.74 181.905 117.88 ;
        RECT  0 117.2 182.5 117.74 ;
        RECT  172.5 117.06 181.905 117.2 ;
        RECT  12.12 117.06 170.5 117.2 ;
        RECT  0.595 117.06 10.12 117.2 ;
        RECT  172.5 116.72 182.5 117.06 ;
        RECT  12.12 116.72 170.5 117.06 ;
        RECT  0 116.72 10.12 117.06 ;
        RECT  0 116.52 182.5 116.72 ;
        RECT  0.595 116.38 182.5 116.52 ;
        RECT  0 115.84 182.5 116.38 ;
        RECT  0 115.7 181.905 115.84 ;
        RECT  0 115.16 182.5 115.7 ;
        RECT  0.595 115.02 181.905 115.16 ;
        RECT  0 114.48 182.5 115.02 ;
        RECT  172.5 114.34 182.5 114.48 ;
        RECT  12.12 114.34 170.5 114.48 ;
        RECT  0.595 114.34 10.12 114.48 ;
        RECT  172.5 114 182.5 114.34 ;
        RECT  12.12 114 170.5 114.34 ;
        RECT  0 114 10.12 114.34 ;
        RECT  0 113.8 182.5 114 ;
        RECT  0 113.66 181.905 113.8 ;
        RECT  0 113.12 182.5 113.66 ;
        RECT  0.595 112.98 181.905 113.12 ;
        RECT  0 112.44 182.5 112.98 ;
        RECT  0.595 112.3 182.5 112.44 ;
        RECT  0 111.76 182.5 112.3 ;
        RECT  172.5 111.62 181.905 111.76 ;
        RECT  12.12 111.62 170.5 111.76 ;
        RECT  0 111.62 10.12 111.76 ;
        RECT  172.5 111.28 182.5 111.62 ;
        RECT  12.12 111.28 170.5 111.62 ;
        RECT  0 111.28 10.12 111.62 ;
        RECT  0 111.08 182.5 111.28 ;
        RECT  0.595 110.94 181.905 111.08 ;
        RECT  0 110.4 182.5 110.94 ;
        RECT  0.595 110.26 182.5 110.4 ;
        RECT  0 109.72 182.5 110.26 ;
        RECT  0 109.58 181.905 109.72 ;
        RECT  0 109.04 182.5 109.58 ;
        RECT  172.5 108.9 182.5 109.04 ;
        RECT  12.12 108.9 170.5 109.04 ;
        RECT  0.595 108.9 10.12 109.04 ;
        RECT  172.5 108.56 182.5 108.9 ;
        RECT  12.12 108.56 170.5 108.9 ;
        RECT  0 108.56 10.12 108.9 ;
        RECT  0 108.36 182.5 108.56 ;
        RECT  0.595 108.22 181.905 108.36 ;
        RECT  0 107.68 182.5 108.22 ;
        RECT  0 107.54 181.905 107.68 ;
        RECT  0 107 182.5 107.54 ;
        RECT  0.595 106.86 182.5 107 ;
        RECT  0 106.32 182.5 106.86 ;
        RECT  172.5 106.18 181.905 106.32 ;
        RECT  12.12 106.18 170.5 106.32 ;
        RECT  0.595 106.18 10.12 106.32 ;
        RECT  172.5 105.84 182.5 106.18 ;
        RECT  12.12 105.84 170.5 106.18 ;
        RECT  0 105.84 10.12 106.18 ;
        RECT  0 105.64 182.5 105.84 ;
        RECT  0 105.5 181.905 105.64 ;
        RECT  0 104.96 182.5 105.5 ;
        RECT  0.595 104.82 182.5 104.96 ;
        RECT  0 104.28 182.5 104.82 ;
        RECT  0.595 104.14 181.905 104.28 ;
        RECT  0 103.6 182.5 104.14 ;
        RECT  172.5 103.46 181.905 103.6 ;
        RECT  12.12 103.46 170.5 103.6 ;
        RECT  0 103.46 10.12 103.6 ;
        RECT  172.5 103.12 182.5 103.46 ;
        RECT  12.12 103.12 170.5 103.46 ;
        RECT  0 103.12 10.12 103.46 ;
        RECT  0 102.92 182.5 103.12 ;
        RECT  0.595 102.78 182.5 102.92 ;
        RECT  0 102.24 182.5 102.78 ;
        RECT  0.595 102.1 181.905 102.24 ;
        RECT  0 101.56 182.5 102.1 ;
        RECT  0 101.42 181.905 101.56 ;
        RECT  0 100.88 182.5 101.42 ;
        RECT  172.5 100.74 182.5 100.88 ;
        RECT  12.12 100.74 170.5 100.88 ;
        RECT  0.595 100.74 10.12 100.88 ;
        RECT  172.5 100.4 182.5 100.74 ;
        RECT  12.12 100.4 170.5 100.74 ;
        RECT  0 100.4 10.12 100.74 ;
        RECT  0 100.2 182.5 100.4 ;
        RECT  0.595 100.06 181.905 100.2 ;
        RECT  0 99.52 182.5 100.06 ;
        RECT  0 99.38 181.905 99.52 ;
        RECT  0 98.84 182.5 99.38 ;
        RECT  0.595 98.7 182.5 98.84 ;
        RECT  0 98.16 182.5 98.7 ;
        RECT  172.5 98.02 181.905 98.16 ;
        RECT  12.12 98.02 170.5 98.16 ;
        RECT  0.595 98.02 10.12 98.16 ;
        RECT  172.5 97.68 182.5 98.02 ;
        RECT  12.12 97.68 170.5 98.02 ;
        RECT  0 97.68 10.12 98.02 ;
        RECT  0 97.48 182.5 97.68 ;
        RECT  0 97.34 181.905 97.48 ;
        RECT  0 96.8 182.5 97.34 ;
        RECT  0.595 96.66 182.5 96.8 ;
        RECT  0 96.12 182.5 96.66 ;
        RECT  0 95.98 181.905 96.12 ;
        RECT  0 95.44 182.5 95.98 ;
        RECT  172.5 95.3 181.905 95.44 ;
        RECT  12.12 95.3 170.5 95.44 ;
        RECT  0.595 95.3 10.12 95.44 ;
        RECT  172.5 94.96 182.5 95.3 ;
        RECT  12.12 94.96 170.5 95.3 ;
        RECT  0 94.96 10.12 95.3 ;
        RECT  0 94.76 182.5 94.96 ;
        RECT  0.595 94.62 182.5 94.76 ;
        RECT  0 94.08 182.5 94.62 ;
        RECT  0 93.94 181.905 94.08 ;
        RECT  0 93.4 182.5 93.94 ;
        RECT  0.595 93.26 181.905 93.4 ;
        RECT  0 92.72 182.5 93.26 ;
        RECT  172.5 92.58 182.5 92.72 ;
        RECT  12.12 92.58 170.5 92.72 ;
        RECT  0.595 92.58 10.12 92.72 ;
        RECT  172.5 92.24 182.5 92.58 ;
        RECT  12.12 92.24 170.5 92.58 ;
        RECT  0 92.24 10.12 92.58 ;
        RECT  0 92.04 182.5 92.24 ;
        RECT  0 91.9 181.905 92.04 ;
        RECT  0 91.36 182.5 91.9 ;
        RECT  0.595 91.22 181.905 91.36 ;
        RECT  0 90.68 182.5 91.22 ;
        RECT  0.595 90.54 182.5 90.68 ;
        RECT  0 90 182.5 90.54 ;
        RECT  172.5 89.86 181.905 90 ;
        RECT  12.12 89.86 170.5 90 ;
        RECT  0 89.86 10.12 90 ;
        RECT  172.5 89.52 182.5 89.86 ;
        RECT  12.12 89.52 170.5 89.86 ;
        RECT  0 89.52 10.12 89.86 ;
        RECT  0 89.32 182.5 89.52 ;
        RECT  0.595 89.18 181.905 89.32 ;
        RECT  0 88.64 182.5 89.18 ;
        RECT  0.595 88.5 182.5 88.64 ;
        RECT  0 87.96 182.5 88.5 ;
        RECT  0 87.82 181.905 87.96 ;
        RECT  0 87.28 182.5 87.82 ;
        RECT  172.5 87.14 181.905 87.28 ;
        RECT  12.12 87.14 170.5 87.28 ;
        RECT  0.595 87.14 10.12 87.28 ;
        RECT  172.5 86.8 182.5 87.14 ;
        RECT  12.12 86.8 170.5 87.14 ;
        RECT  0 86.8 10.12 87.14 ;
        RECT  0 86.6 182.5 86.8 ;
        RECT  0.595 86.46 182.5 86.6 ;
        RECT  0 85.92 182.5 86.46 ;
        RECT  0 85.78 181.905 85.92 ;
        RECT  0 85.24 182.5 85.78 ;
        RECT  0.595 85.1 182.5 85.24 ;
        RECT  0 84.56 182.5 85.1 ;
        RECT  172.5 84.42 181.905 84.56 ;
        RECT  12.12 84.42 170.5 84.56 ;
        RECT  0.595 84.42 10.12 84.56 ;
        RECT  172.5 84.08 182.5 84.42 ;
        RECT  12.12 84.08 170.5 84.42 ;
        RECT  0 84.08 10.12 84.42 ;
        RECT  0 83.88 182.5 84.08 ;
        RECT  0 83.74 181.905 83.88 ;
        RECT  0 83.2 182.5 83.74 ;
        RECT  0.595 83.06 182.5 83.2 ;
        RECT  0 82.52 182.5 83.06 ;
        RECT  0.595 82.38 181.905 82.52 ;
        RECT  0 81.84 182.5 82.38 ;
        RECT  172.5 81.7 181.905 81.84 ;
        RECT  12.12 81.7 170.5 81.84 ;
        RECT  0 81.7 10.12 81.84 ;
        RECT  172.5 81.36 182.5 81.7 ;
        RECT  12.12 81.36 170.5 81.7 ;
        RECT  0 81.36 10.12 81.7 ;
        RECT  0 81.16 182.5 81.36 ;
        RECT  0.595 81.02 182.5 81.16 ;
        RECT  0 80.48 182.5 81.02 ;
        RECT  0.595 80.34 181.905 80.48 ;
        RECT  0 79.8 182.5 80.34 ;
        RECT  0 79.66 181.905 79.8 ;
        RECT  0 79.12 182.5 79.66 ;
        RECT  172.5 78.98 182.5 79.12 ;
        RECT  12.12 78.98 170.5 79.12 ;
        RECT  0.595 78.98 10.12 79.12 ;
        RECT  172.5 78.64 182.5 78.98 ;
        RECT  12.12 78.64 170.5 78.98 ;
        RECT  0 78.64 10.12 78.98 ;
        RECT  0 78.44 182.5 78.64 ;
        RECT  0.595 78.3 181.905 78.44 ;
        RECT  0 77.76 182.5 78.3 ;
        RECT  0 77.62 181.905 77.76 ;
        RECT  0 77.08 182.5 77.62 ;
        RECT  0.595 76.94 182.5 77.08 ;
        RECT  0 76.4 182.5 76.94 ;
        RECT  172.5 76.26 181.905 76.4 ;
        RECT  12.12 76.26 170.5 76.4 ;
        RECT  0.595 76.26 10.12 76.4 ;
        RECT  172.5 75.92 182.5 76.26 ;
        RECT  12.12 75.92 170.5 76.26 ;
        RECT  0 75.92 10.12 76.26 ;
        RECT  0 75.72 182.5 75.92 ;
        RECT  0 75.58 181.905 75.72 ;
        RECT  0 75.04 182.5 75.58 ;
        RECT  0.595 74.9 182.5 75.04 ;
        RECT  0 74.36 182.5 74.9 ;
        RECT  0.595 74.22 181.905 74.36 ;
        RECT  0 73.68 182.5 74.22 ;
        RECT  172.5 73.54 181.905 73.68 ;
        RECT  12.12 73.54 170.5 73.68 ;
        RECT  0 73.54 10.12 73.68 ;
        RECT  172.5 73.2 182.5 73.54 ;
        RECT  12.12 73.2 170.5 73.54 ;
        RECT  0 73.2 10.12 73.54 ;
        RECT  0 73 182.5 73.2 ;
        RECT  0.595 72.86 182.5 73 ;
        RECT  0 72.32 182.5 72.86 ;
        RECT  0 72.18 181.905 72.32 ;
        RECT  0 71.64 182.5 72.18 ;
        RECT  0.595 71.5 181.905 71.64 ;
        RECT  0 70.96 182.5 71.5 ;
        RECT  172.5 70.82 182.5 70.96 ;
        RECT  12.12 70.82 170.5 70.96 ;
        RECT  0.595 70.82 10.12 70.96 ;
        RECT  172.5 70.48 182.5 70.82 ;
        RECT  12.12 70.48 170.5 70.82 ;
        RECT  0 70.48 10.12 70.82 ;
        RECT  0 70.28 182.5 70.48 ;
        RECT  0 70.14 181.905 70.28 ;
        RECT  0 69.6 182.5 70.14 ;
        RECT  0.595 69.46 181.905 69.6 ;
        RECT  0 68.92 182.5 69.46 ;
        RECT  0.595 68.78 182.5 68.92 ;
        RECT  0 68.24 182.5 68.78 ;
        RECT  172.5 68.1 181.905 68.24 ;
        RECT  12.12 68.1 170.5 68.24 ;
        RECT  0 68.1 10.12 68.24 ;
        RECT  172.5 67.76 182.5 68.1 ;
        RECT  12.12 67.76 170.5 68.1 ;
        RECT  0 67.76 10.12 68.1 ;
        RECT  0 67.56 182.5 67.76 ;
        RECT  0.595 67.42 181.905 67.56 ;
        RECT  0 66.88 182.5 67.42 ;
        RECT  0.595 66.74 182.5 66.88 ;
        RECT  0 66.2 182.5 66.74 ;
        RECT  0 66.06 181.905 66.2 ;
        RECT  0 65.52 182.5 66.06 ;
        RECT  172.5 65.38 181.905 65.52 ;
        RECT  12.12 65.38 170.5 65.52 ;
        RECT  0.595 65.38 10.12 65.52 ;
        RECT  172.5 65.04 182.5 65.38 ;
        RECT  12.12 65.04 170.5 65.38 ;
        RECT  0 65.04 10.12 65.38 ;
        RECT  0 64.84 182.5 65.04 ;
        RECT  0.595 64.7 182.5 64.84 ;
        RECT  0 64.16 182.5 64.7 ;
        RECT  0 64.02 181.905 64.16 ;
        RECT  0 63.48 182.5 64.02 ;
        RECT  0.595 63.34 181.905 63.48 ;
        RECT  0 62.8 182.5 63.34 ;
        RECT  172.5 62.66 182.5 62.8 ;
        RECT  12.12 62.66 170.5 62.8 ;
        RECT  0.595 62.66 10.12 62.8 ;
        RECT  172.5 62.32 182.5 62.66 ;
        RECT  12.12 62.32 170.5 62.66 ;
        RECT  0 62.32 10.12 62.66 ;
        RECT  0 62.12 182.5 62.32 ;
        RECT  0 61.98 181.905 62.12 ;
        RECT  0 61.44 182.5 61.98 ;
        RECT  0.595 61.3 181.905 61.44 ;
        RECT  0 60.76 182.5 61.3 ;
        RECT  0.595 60.62 182.5 60.76 ;
        RECT  0 60.08 182.5 60.62 ;
        RECT  172.5 59.94 181.905 60.08 ;
        RECT  12.12 59.94 170.5 60.08 ;
        RECT  0 59.94 10.12 60.08 ;
        RECT  172.5 59.6 182.5 59.94 ;
        RECT  12.12 59.6 170.5 59.94 ;
        RECT  0 59.6 10.12 59.94 ;
        RECT  0 59.4 182.5 59.6 ;
        RECT  0.595 59.26 182.5 59.4 ;
        RECT  0 58.72 182.5 59.26 ;
        RECT  0.595 58.58 181.905 58.72 ;
        RECT  0 58.04 182.5 58.58 ;
        RECT  0 57.9 181.905 58.04 ;
        RECT  0 57.36 182.5 57.9 ;
        RECT  172.5 57.22 182.5 57.36 ;
        RECT  12.12 57.22 170.5 57.36 ;
        RECT  0.595 57.22 10.12 57.36 ;
        RECT  172.5 56.88 182.5 57.22 ;
        RECT  12.12 56.88 170.5 57.22 ;
        RECT  0 56.88 10.12 57.22 ;
        RECT  0 56.68 182.5 56.88 ;
        RECT  0.595 56.54 181.905 56.68 ;
        RECT  0 56 182.5 56.54 ;
        RECT  0 55.86 181.905 56 ;
        RECT  0 55.32 182.5 55.86 ;
        RECT  0.595 55.18 182.5 55.32 ;
        RECT  0 54.64 182.5 55.18 ;
        RECT  172.5 54.5 181.905 54.64 ;
        RECT  12.12 54.5 170.5 54.64 ;
        RECT  0.595 54.5 10.12 54.64 ;
        RECT  172.5 54.16 182.5 54.5 ;
        RECT  12.12 54.16 170.5 54.5 ;
        RECT  0 54.16 10.12 54.5 ;
        RECT  0 53.96 182.5 54.16 ;
        RECT  0 53.82 181.905 53.96 ;
        RECT  0 53.28 182.5 53.82 ;
        RECT  0.595 53.14 182.5 53.28 ;
        RECT  0 52.6 182.5 53.14 ;
        RECT  0.595 52.46 181.905 52.6 ;
        RECT  0 51.92 182.5 52.46 ;
        RECT  172.5 51.78 181.905 51.92 ;
        RECT  12.12 51.78 170.5 51.92 ;
        RECT  0 51.78 10.12 51.92 ;
        RECT  172.5 51.44 182.5 51.78 ;
        RECT  12.12 51.44 170.5 51.78 ;
        RECT  0 51.44 10.12 51.78 ;
        RECT  0 51.24 182.5 51.44 ;
        RECT  0.595 51.1 182.5 51.24 ;
        RECT  0 50.56 182.5 51.1 ;
        RECT  0.595 50.42 181.905 50.56 ;
        RECT  0 49.88 182.5 50.42 ;
        RECT  0 49.74 181.905 49.88 ;
        RECT  0 49.2 182.5 49.74 ;
        RECT  172.5 49.06 182.5 49.2 ;
        RECT  12.12 49.06 170.5 49.2 ;
        RECT  0.595 49.06 10.12 49.2 ;
        RECT  172.5 48.72 182.5 49.06 ;
        RECT  12.12 48.72 170.5 49.06 ;
        RECT  0 48.72 10.12 49.06 ;
        RECT  0 48.52 182.5 48.72 ;
        RECT  0 48.38 181.905 48.52 ;
        RECT  0 47.84 182.5 48.38 ;
        RECT  0.595 47.7 181.905 47.84 ;
        RECT  0 47.16 182.5 47.7 ;
        RECT  0.595 47.02 182.5 47.16 ;
        RECT  0 46.48 182.5 47.02 ;
        RECT  172.5 46.34 181.905 46.48 ;
        RECT  12.12 46.34 170.5 46.48 ;
        RECT  0 46.34 10.12 46.48 ;
        RECT  172.5 46 182.5 46.34 ;
        RECT  12.12 46 170.5 46.34 ;
        RECT  0 46 10.12 46.34 ;
        RECT  0 45.8 182.5 46 ;
        RECT  0.595 45.66 181.905 45.8 ;
        RECT  0 45.12 182.5 45.66 ;
        RECT  0.595 44.98 182.5 45.12 ;
        RECT  0 44.44 182.5 44.98 ;
        RECT  0 44.3 181.905 44.44 ;
        RECT  0 43.76 182.5 44.3 ;
        RECT  172.5 43.62 181.905 43.76 ;
        RECT  12.12 43.62 170.5 43.76 ;
        RECT  0.595 43.62 10.12 43.76 ;
        RECT  172.5 43.28 182.5 43.62 ;
        RECT  12.12 43.28 170.5 43.62 ;
        RECT  0 43.28 10.12 43.62 ;
        RECT  0 43.08 182.5 43.28 ;
        RECT  0.595 42.94 182.5 43.08 ;
        RECT  0 42.4 182.5 42.94 ;
        RECT  0 42.26 181.905 42.4 ;
        RECT  0 41.72 182.5 42.26 ;
        RECT  0.595 41.58 181.905 41.72 ;
        RECT  0 41.04 182.5 41.58 ;
        RECT  172.5 40.9 182.5 41.04 ;
        RECT  12.12 40.9 170.5 41.04 ;
        RECT  0.595 40.9 10.12 41.04 ;
        RECT  172.5 40.56 182.5 40.9 ;
        RECT  12.12 40.56 170.5 40.9 ;
        RECT  0 40.56 10.12 40.9 ;
        RECT  0 40.36 182.5 40.56 ;
        RECT  0 40.22 181.905 40.36 ;
        RECT  0 39.68 182.5 40.22 ;
        RECT  0.595 39.54 181.905 39.68 ;
        RECT  0 39 182.5 39.54 ;
        RECT  0.595 38.86 182.5 39 ;
        RECT  0 38.32 182.5 38.86 ;
        RECT  172.5 38.18 181.905 38.32 ;
        RECT  12.12 38.18 170.5 38.32 ;
        RECT  0 38.18 10.12 38.32 ;
        RECT  172.5 37.84 182.5 38.18 ;
        RECT  12.12 37.84 170.5 38.18 ;
        RECT  0 37.84 10.12 38.18 ;
        RECT  0 37.64 182.5 37.84 ;
        RECT  0.595 37.5 181.905 37.64 ;
        RECT  0 36.96 182.5 37.5 ;
        RECT  0.595 36.82 182.5 36.96 ;
        RECT  0 36.28 182.5 36.82 ;
        RECT  0 36.14 181.905 36.28 ;
        RECT  0 35.6 182.5 36.14 ;
        RECT  172.5 35.46 182.5 35.6 ;
        RECT  12.12 35.46 170.5 35.6 ;
        RECT  0.595 35.46 10.12 35.6 ;
        RECT  172.5 35.12 182.5 35.46 ;
        RECT  12.12 35.12 170.5 35.46 ;
        RECT  0 35.12 10.12 35.46 ;
        RECT  0 34.92 182.5 35.12 ;
        RECT  0.595 34.78 181.905 34.92 ;
        RECT  0 34.24 182.5 34.78 ;
        RECT  0 34.1 181.905 34.24 ;
        RECT  0 33.56 182.5 34.1 ;
        RECT  0.595 33.42 182.5 33.56 ;
        RECT  0 32.88 182.5 33.42 ;
        RECT  172.5 32.74 181.905 32.88 ;
        RECT  12.12 32.74 170.5 32.88 ;
        RECT  0.595 32.74 10.12 32.88 ;
        RECT  172.5 32.4 182.5 32.74 ;
        RECT  12.12 32.4 170.5 32.74 ;
        RECT  0 32.4 10.12 32.74 ;
        RECT  0 32.2 182.5 32.4 ;
        RECT  0 32.06 181.905 32.2 ;
        RECT  0 31.52 182.5 32.06 ;
        RECT  0.595 31.38 182.5 31.52 ;
        RECT  0 30.84 182.5 31.38 ;
        RECT  0.595 30.7 181.905 30.84 ;
        RECT  0 30.16 182.5 30.7 ;
        RECT  172.5 30.02 181.905 30.16 ;
        RECT  12.12 30.02 170.5 30.16 ;
        RECT  0 30.02 10.12 30.16 ;
        RECT  172.5 29.68 182.5 30.02 ;
        RECT  12.12 29.68 170.5 30.02 ;
        RECT  0 29.68 10.12 30.02 ;
        RECT  0 29.48 182.5 29.68 ;
        RECT  0.595 29.34 182.5 29.48 ;
        RECT  0 28.8 182.5 29.34 ;
        RECT  0.595 28.66 181.905 28.8 ;
        RECT  0 28.12 182.5 28.66 ;
        RECT  0 27.98 181.905 28.12 ;
        RECT  0 27.44 182.5 27.98 ;
        RECT  172.5 27.3 182.5 27.44 ;
        RECT  12.12 27.3 170.5 27.44 ;
        RECT  0.595 27.3 10.12 27.44 ;
        RECT  172.5 26.96 182.5 27.3 ;
        RECT  12.12 26.96 170.5 27.3 ;
        RECT  0 26.96 10.12 27.3 ;
        RECT  0 26.76 182.5 26.96 ;
        RECT  0.595 26.62 181.905 26.76 ;
        RECT  0 26.08 182.5 26.62 ;
        RECT  0 25.94 181.905 26.08 ;
        RECT  0 25.4 182.5 25.94 ;
        RECT  0.595 25.26 182.5 25.4 ;
        RECT  0 24.72 182.5 25.26 ;
        RECT  172.5 24.58 181.905 24.72 ;
        RECT  12.12 24.58 170.5 24.72 ;
        RECT  0 24.58 10.12 24.72 ;
        RECT  172.5 24.24 182.5 24.58 ;
        RECT  12.12 24.24 170.5 24.58 ;
        RECT  0 24.24 10.12 24.58 ;
        RECT  0 24.04 182.5 24.24 ;
        RECT  0.595 23.9 181.905 24.04 ;
        RECT  0 23.36 182.5 23.9 ;
        RECT  0.595 23.22 182.5 23.36 ;
        RECT  0 22.68 182.5 23.22 ;
        RECT  0 22.54 181.905 22.68 ;
        RECT  0 22 182.5 22.54 ;
        RECT  172.5 21.86 181.905 22 ;
        RECT  12.12 21.86 170.5 22 ;
        RECT  0.595 21.86 10.12 22 ;
        RECT  172.5 21.52 182.5 21.86 ;
        RECT  12.12 21.52 170.5 21.86 ;
        RECT  0 21.52 10.12 21.86 ;
        RECT  0 21.32 182.5 21.52 ;
        RECT  0.595 21.18 182.5 21.32 ;
        RECT  0 20.64 182.5 21.18 ;
        RECT  0 20.5 181.905 20.64 ;
        RECT  0 19.96 182.5 20.5 ;
        RECT  0.595 19.82 181.905 19.96 ;
        RECT  0 19.28 182.5 19.82 ;
        RECT  172.5 19.14 182.5 19.28 ;
        RECT  12.12 19.14 170.5 19.28 ;
        RECT  0.595 19.14 10.12 19.28 ;
        RECT  172.5 18.8 182.5 19.14 ;
        RECT  12.12 18.8 170.5 19.14 ;
        RECT  0 18.8 10.12 19.14 ;
        RECT  0 18.6 182.5 18.8 ;
        RECT  0 18.46 181.905 18.6 ;
        RECT  0 17.92 182.5 18.46 ;
        RECT  0.595 17.78 181.905 17.92 ;
        RECT  0 17.24 182.5 17.78 ;
        RECT  0.595 17.1 182.5 17.24 ;
        RECT  0 16.56 182.5 17.1 ;
        RECT  172.5 16.42 181.905 16.56 ;
        RECT  12.12 16.42 170.5 16.56 ;
        RECT  0 16.42 10.12 16.56 ;
        RECT  172.5 16.08 182.5 16.42 ;
        RECT  12.12 16.08 170.5 16.42 ;
        RECT  0 16.08 10.12 16.42 ;
        RECT  0 15.88 182.5 16.08 ;
        RECT  0.595 15.74 181.905 15.88 ;
        RECT  0 15.2 182.5 15.74 ;
        RECT  0.595 15.06 182.5 15.2 ;
        RECT  0 14.52 182.5 15.06 ;
        RECT  0 14.38 181.905 14.52 ;
        RECT  0 13.84 182.5 14.38 ;
        RECT  172.5 13.7 181.905 13.84 ;
        RECT  12.12 13.7 170.5 13.84 ;
        RECT  0.595 13.7 10.12 13.84 ;
        RECT  172.5 13.36 182.5 13.7 ;
        RECT  12.12 13.36 170.5 13.7 ;
        RECT  0 13.36 10.12 13.7 ;
        RECT  0 13.16 182.5 13.36 ;
        RECT  0.595 13.02 182.5 13.16 ;
        RECT  0 12.48 182.5 13.02 ;
        RECT  0 12.34 181.905 12.48 ;
        RECT  0 11.8 182.5 12.34 ;
        RECT  0.595 11.66 182.5 11.8 ;
        RECT  0 11.12 182.5 11.66 ;
        RECT  172.5 10.98 181.905 11.12 ;
        RECT  0.595 10.98 10.12 11.12 ;
        RECT  172.5 10.64 182.5 10.98 ;
        RECT  0 10.64 10.12 10.98 ;
        RECT  0 10.44 182.5 10.64 ;
        RECT  0 10.3 181.905 10.44 ;
        RECT  0 9.76 182.5 10.3 ;
        RECT  0.595 9.62 182.5 9.76 ;
        RECT  0 9.08 182.5 9.62 ;
        RECT  0.595 8.94 181.905 9.08 ;
        RECT  0 8.4 182.5 8.94 ;
        RECT  0 8.26 181.905 8.4 ;
        RECT  0 7.72 182.5 8.26 ;
        RECT  0.595 7.58 182.5 7.72 ;
        RECT  0 7.04 182.5 7.58 ;
        RECT  0.595 6.9 181.905 7.04 ;
        RECT  0 6.36 182.5 6.9 ;
        RECT  0 6.22 181.905 6.36 ;
        RECT  0 5.68 182.5 6.22 ;
        RECT  0.595 5.54 182.5 5.68 ;
        RECT  0 5 182.5 5.54 ;
        RECT  0.595 4.86 181.905 5 ;
        RECT  0 4.32 182.5 4.86 ;
        RECT  0 4.18 181.905 4.32 ;
        RECT  0 3.64 182.5 4.18 ;
        RECT  0.595 3.5 182.5 3.64 ;
        RECT  0 2.96 182.5 3.5 ;
        RECT  0.595 2.82 181.905 2.96 ;
        RECT  0 2.28 182.5 2.82 ;
        RECT  0 2.14 181.905 2.28 ;
        RECT  0 1.6 182.5 2.14 ;
        RECT  0.595 1.46 182.5 1.6 ;
        RECT  0 0.92 182.5 1.46 ;
        RECT  0 0.78 181.905 0.92 ;
        RECT  0 0 182.5 0.78 ;
      LAYER li1 ;
        RECT  0 0 182.5 182.5 ;
    END
END ember_xbar
END LIBRARY
